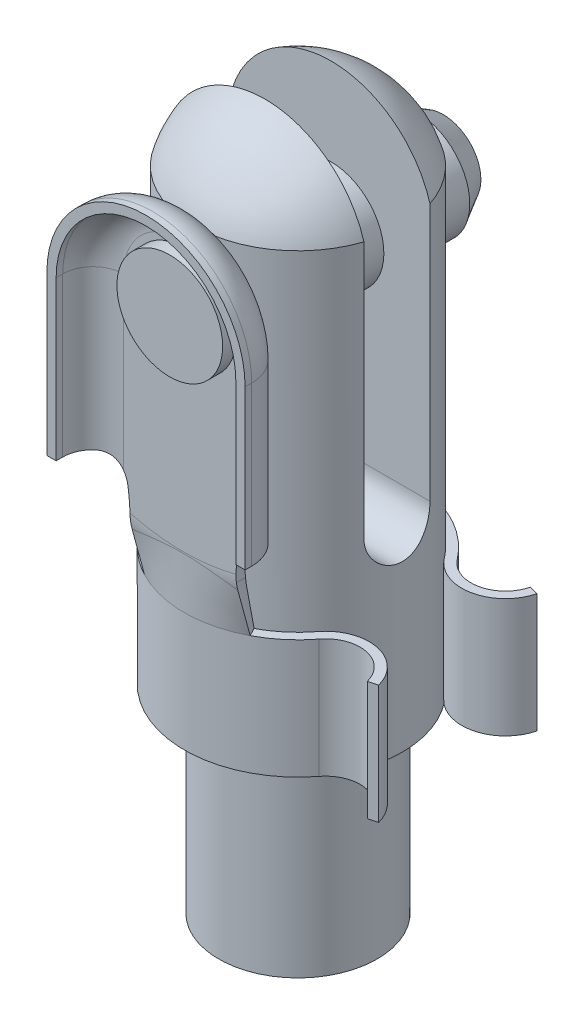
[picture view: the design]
ISO-10303-21;
HEADER;
FILE_DESCRIPTION(('STEP AP214'),'2;1');
FILE_NAME('part.step','',(''),(''),'','','');
FILE_SCHEMA(('AUTOMOTIVE_DESIGN { 1 0 10303 214 1 1 1 1 }'));
ENDSEC;
DATA;
#1=APPLICATION_CONTEXT('core data for automotive mechanical design processes');
#2=APPLICATION_PROTOCOL_DEFINITION('international standard','automotive_design',2000,#1);
#3=PRODUCT_CONTEXT('',#1,'mechanical');
#4=PRODUCT('Part','Part','',(#3));
#5=PRODUCT_RELATED_PRODUCT_CATEGORY('part','',(#4));
#6=PRODUCT_DEFINITION_FORMATION('','',#4);
#7=PRODUCT_DEFINITION_CONTEXT('part definition',#1,'design');
#8=PRODUCT_DEFINITION('design','',#6,#7);
#9=PRODUCT_DEFINITION_SHAPE('','',#8);
#10=(LENGTH_UNIT() NAMED_UNIT(*) SI_UNIT(.MILLI.,.METRE.));
#11=(NAMED_UNIT(*) PLANE_ANGLE_UNIT() SI_UNIT($,.RADIAN.));
#12=(NAMED_UNIT(*) SI_UNIT($,.STERADIAN.) SOLID_ANGLE_UNIT());
#13=UNCERTAINTY_MEASURE_WITH_UNIT(LENGTH_MEASURE(1.E-05),#10,'distance_accuracy_value','');
#14=(GEOMETRIC_REPRESENTATION_CONTEXT(3) GLOBAL_UNCERTAINTY_ASSIGNED_CONTEXT((#13)) GLOBAL_UNIT_ASSIGNED_CONTEXT((#10,
#11,#12)) REPRESENTATION_CONTEXT('',''));
#15=CARTESIAN_POINT('',(0.,0.,0.));
#16=DIRECTION('',(0.,0.,1.));
#17=DIRECTION('',(1.,0.,0.));
#18=AXIS2_PLACEMENT_3D('',#15,#16,#17);
#19=CARTESIAN_POINT('',(0.,22.,4.35));
#20=DIRECTION('',(0.,0.,1.));
#21=DIRECTION('',(1.,0.,0.));
#22=AXIS2_PLACEMENT_3D('',#19,#20,#21);
#23=PLANE('',#22);
#24=CARTESIAN_POINT('',(-10.125,14.,4.35));
#25=DIRECTION('',(0.,0.,-1.));
#26=DIRECTION('',(-1.,0.,0.));
#27=AXIS2_PLACEMENT_3D('',#24,#25,#26);
#28=CIRCLE('',#27,8.12500000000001);
#29=CARTESIAN_POINT('',(-2.08042264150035,15.140350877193,4.35));
#30=VERTEX_POINT('',#29);
#31=CARTESIAN_POINT('',(-2.00490939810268,14.2824068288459,4.35));
#32=VERTEX_POINT('',#31);
#33=EDGE_CURVE('E390',#30,#32,#28,.T.);
#34=ORIENTED_EDGE('',*,*,#33,.T.);
#35=CARTESIAN_POINT('',(3.48211562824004,14.5940291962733,4.35));
#36=CARTESIAN_POINT('',(3.59794180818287,13.9723308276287,4.35));
#37=CARTESIAN_POINT('',(3.69271229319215,13.4636491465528,3.98642597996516));
#38=CARTESIAN_POINT('',(3.36408920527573,14.5720505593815,4.35));
#39=CARTESIAN_POINT('',(3.47870250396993,13.9726457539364,4.35));
#40=CARTESIAN_POINT('',(3.57308567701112,13.474977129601,4.00961729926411));
#41=CARTESIAN_POINT('',(3.2461966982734,14.5493560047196,4.35));
#42=CARTESIAN_POINT('',(3.35875531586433,13.9730784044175,4.35));
#43=CARTESIAN_POINT('',(3.4527952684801,13.4878586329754,4.03300707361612));
#44=CARTESIAN_POINT('',(3.01068838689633,14.5025898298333,4.35));
#45=CARTESIAN_POINT('',(3.1182084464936,13.974228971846,4.35));
#46=CARTESIAN_POINT('',(3.21052336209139,13.5170837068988,4.07940973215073));
#47=CARTESIAN_POINT('',(2.89307257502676,14.4785182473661,4.35));
#48=CARTESIAN_POINT('',(2.9975937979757,13.974945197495,4.35));
#49=CARTESIAN_POINT('',(3.08854191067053,13.5334271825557,4.10242262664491));
#50=CARTESIAN_POINT('',(2.65814533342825,14.4290568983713,4.35));
#51=CARTESIAN_POINT('',(2.75560555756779,13.9767106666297,4.35));
#52=CARTESIAN_POINT('',(2.84254436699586,13.5699278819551,4.14729425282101));
#53=CARTESIAN_POINT('',(2.54083384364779,14.4036674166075,4.35));
#54=CARTESIAN_POINT('',(2.63419382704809,13.9777581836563,4.35));
#55=CARTESIAN_POINT('',(2.71852871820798,13.5900842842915,4.16915323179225));
#56=CARTESIAN_POINT('',(2.30647303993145,14.3517078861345,4.35));
#57=CARTESIAN_POINT('',(2.39056256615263,13.9801899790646,4.35));
#58=CARTESIAN_POINT('',(2.46820849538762,13.6342865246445,4.21063104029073));
#59=CARTESIAN_POINT('',(2.18942372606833,14.3251378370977,4.35));
#60=CARTESIAN_POINT('',(2.26827130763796,13.9815732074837,4.35));
#61=CARTESIAN_POINT('',(2.34190392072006,13.6583323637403,4.23024986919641));
#62=CARTESIAN_POINT('',(2.03983028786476,14.2905384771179,4.35));
#63=CARTESIAN_POINT('',(2.11111568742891,13.9835138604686,4.35));
#64=CARTESIAN_POINT('',(2.17890874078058,13.6913414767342,4.25312173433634));
#65=CARTESIAN_POINT('',(2.00718388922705,14.2829485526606,4.35));
#66=CARTESIAN_POINT('',(2.07683337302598,13.9839470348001,4.35));
#67=CARTESIAN_POINT('',(2.14324163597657,13.6986841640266,4.25797881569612));
#68=CARTESIAN_POINT('',(1.94190588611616,14.2677007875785,4.35));
#69=CARTESIAN_POINT('',(2.00821149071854,13.9848304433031,4.35));
#70=CARTESIAN_POINT('',(2.07174220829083,13.7136250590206,4.26739464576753));
#71=CARTESIAN_POINT('',(1.90927428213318,14.2600429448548,4.35));
#72=CARTESIAN_POINT('',(1.97386929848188,13.9852806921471,4.35));
#73=CARTESIAN_POINT('',(2.03590988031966,13.7212232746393,4.27195338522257));
#74=CARTESIAN_POINT('',(1.87664983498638,14.2523545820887,4.35));
#75=CARTESIAN_POINT('',(1.93948182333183,13.9857380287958,4.35));
#76=CARTESIAN_POINT('',(2.00000000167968,13.7289397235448,4.276349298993));
#77=CARTESIAN_POINT('',(1.7929895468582,14.2326289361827,4.35));
#78=CARTESIAN_POINT('',(1.84827499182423,13.9882844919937,4.35));
#79=CARTESIAN_POINT('',(1.90167102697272,13.7513374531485,4.28869521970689));
#80=CARTESIAN_POINT('',(1.70906782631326,14.2139880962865,4.35));
#81=CARTESIAN_POINT('',(1.75755424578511,13.990321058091,4.35));
#82=CARTESIAN_POINT('',(1.80464823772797,13.7723292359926,4.29867394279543));
#83=CARTESIAN_POINT('',(1.54071808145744,14.1790623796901,4.35));
#84=CARTESIAN_POINT('',(1.57730460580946,13.993609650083,4.35));
#85=CARTESIAN_POINT('',(1.61307967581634,13.8113201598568,4.31497721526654));
#86=CARTESIAN_POINT('',(1.4562899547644,14.1627779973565,4.35));
#87=CARTESIAN_POINT('',(1.48768965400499,13.9948646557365,4.35));
#88=CARTESIAN_POINT('',(1.5185344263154,13.8293186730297,4.32130099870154));
#89=CARTESIAN_POINT('',(1.28700243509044,14.1327641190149,4.35));
#90=CARTESIAN_POINT('',(1.30958141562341,13.9968309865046,4.35));
#91=CARTESIAN_POINT('',(1.33185249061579,13.8621282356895,4.33136895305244));
#92=CARTESIAN_POINT('',(1.20214316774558,14.1190339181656,4.35));
#93=CARTESIAN_POINT('',(1.22102866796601,13.9975437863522,4.35));
#94=CARTESIAN_POINT('',(1.23971514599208,13.8769401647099,4.33511383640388));
#95=CARTESIAN_POINT('',(1.03203881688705,14.0942857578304,4.35));
#96=CARTESIAN_POINT('',(1.0448165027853,13.9986190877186,4.35));
#97=CARTESIAN_POINT('',(1.05747616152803,13.9033699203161,4.34088069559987));
#98=CARTESIAN_POINT('',(0.946793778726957,14.0832674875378,4.35));
#99=CARTESIAN_POINT('',(0.957118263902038,13.9989821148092,4.35));
#100=CARTESIAN_POINT('',(0.967374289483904,13.9149881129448,4.34290286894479));
#101=CARTESIAN_POINT('',(0.778062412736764,14.0642810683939,4.35));
#102=CARTESIAN_POINT('',(0.784558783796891,13.9994927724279,4.35));
#103=CARTESIAN_POINT('',(0.791012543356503,13.9348320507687,4.34586056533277));
#104=CARTESIAN_POINT('',(0.694583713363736,14.0562452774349,4.35));
#105=CARTESIAN_POINT('',(0.699659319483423,13.9996455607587,4.35));
#106=CARTESIAN_POINT('',(0.70471251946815,13.943133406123,4.3468213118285));
#107=CARTESIAN_POINT('',(0.527422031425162,14.0428708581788,4.35));
#108=CARTESIAN_POINT('',(0.530332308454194,13.9998525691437,4.35));
#109=CARTESIAN_POINT('',(0.533226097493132,13.9568710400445,4.34818815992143));
#110=CARTESIAN_POINT('',(0.443739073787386,14.0375319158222,4.35));
#111=CARTESIAN_POINT('',(0.445892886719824,13.9999068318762,4.35));
#112=CARTESIAN_POINT('',(0.44803957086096,13.9623076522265,4.34859432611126));
#113=CARTESIAN_POINT('',(0.240084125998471,14.027876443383,4.35));
#114=CARTESIAN_POINT('',(0.240886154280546,13.9999910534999,4.34999999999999));
#115=CARTESIAN_POINT('',(0.241676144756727,13.9721148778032,4.34925858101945));
#116=CARTESIAN_POINT('',(0.120040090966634,14.0249960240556,4.35));
#117=CARTESIAN_POINT('',(0.120438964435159,14.0000004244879,4.34999999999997));
#118=CARTESIAN_POINT('',(0.120836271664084,13.9750123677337,4.34937707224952));
#119=CARTESIAN_POINT('',(-0.115876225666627,14.0249961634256,4.35));
#120=CARTESIAN_POINT('',(-0.116261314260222,13.999999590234,4.35000000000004));
#121=CARTESIAN_POINT('',(-0.116644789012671,13.9750110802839,4.34937357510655));
#122=CARTESIAN_POINT('',(-0.231748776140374,14.0276803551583,4.35));
#123=CARTESIAN_POINT('',(-0.232521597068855,13.9999900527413,4.35000000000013));
#124=CARTESIAN_POINT('',(-0.233286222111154,13.9723098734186,4.34925978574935));
#125=CARTESIAN_POINT('',(-0.472394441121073,14.0386969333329,4.35));
#126=CARTESIAN_POINT('',(-0.474715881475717,13.9998992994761,4.35000000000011));
#127=CARTESIAN_POINT('',(-0.477021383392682,13.9611282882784,4.34852600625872));
#128=CARTESIAN_POINT('',(-0.597148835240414,14.0474580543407,4.35));
#129=CARTESIAN_POINT('',(-0.600705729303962,13.9998124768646,4.34999999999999));
#130=CARTESIAN_POINT('',(-0.604213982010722,13.9522089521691,4.34786680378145));
#131=CARTESIAN_POINT('',(-0.727751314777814,14.0597811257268,4.35));
#132=CARTESIAN_POINT('',(-0.733480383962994,13.999566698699,4.35));
#133=CARTESIAN_POINT('',(-0.739198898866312,13.9394622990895,4.34634505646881));
#134=CARTESIAN_POINT('',(-0.733901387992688,14.0603687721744,4.35));
#135=CARTESIAN_POINT('',(-0.739735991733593,13.9995547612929,4.35));
#136=CARTESIAN_POINT('',(-0.745559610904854,13.9388541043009,4.34627145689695));
#137=CARTESIAN_POINT('',(-0.764648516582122,14.0633433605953,4.35));
#138=CARTESIAN_POINT('',(-0.771022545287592,13.99949306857,4.35));
#139=CARTESIAN_POINT('',(-0.777381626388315,13.9357735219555,4.34589286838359));
#140=CARTESIAN_POINT('',(-0.789235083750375,14.0658392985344,4.35));
#141=CARTESIAN_POINT('',(-0.796074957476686,13.9994373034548,4.35));
#142=CARTESIAN_POINT('',(-0.802897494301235,13.9331823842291,4.34555611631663));
#143=CARTESIAN_POINT('',(-0.9121236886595,14.0789057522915,4.35));
#144=CARTESIAN_POINT('',(-0.921507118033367,13.9991195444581,4.35));
#145=CARTESIAN_POINT('',(-0.930824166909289,13.9195775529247,4.34367552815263));
#146=CARTESIAN_POINT('',(-1.01024394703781,14.0912319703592,4.35));
#147=CARTESIAN_POINT('',(-1.02229643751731,13.9987408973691,4.35));
#148=CARTESIAN_POINT('',(-1.03422629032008,13.9066211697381,4.34154174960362));
#149=CARTESIAN_POINT('',(-1.23721495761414,14.1239933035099,4.35));
#150=CARTESIAN_POINT('',(-1.25734167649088,13.9973412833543,4.35));
#151=CARTESIAN_POINT('',(-1.27716801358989,13.8716557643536,4.33402001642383));
#152=CARTESIAN_POINT('',(-1.36587424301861,14.1457609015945,4.35));
#153=CARTESIAN_POINT('',(-1.39208331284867,13.9961526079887,4.35));
#154=CARTESIAN_POINT('',(-1.41770410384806,13.848077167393,4.32781054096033));
#155=CARTESIAN_POINT('',(-1.55803971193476,14.1826707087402,4.35));
#156=CARTESIAN_POINT('',(-1.5958083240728,13.993255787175,4.35));
#157=CARTESIAN_POINT('',(-1.63281160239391,13.807294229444,4.31322231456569));
#158=CARTESIAN_POINT('',(-1.62196488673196,14.1956854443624,4.35));
#159=CARTESIAN_POINT('',(-1.66410208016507,13.9921021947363,4.35));
#160=CARTESIAN_POINT('',(-1.70523985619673,13.7927954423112,4.30747961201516));
#161=CARTESIAN_POINT('',(-1.74952508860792,14.2230446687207,4.35));
#162=CARTESIAN_POINT('',(-1.80130821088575,13.9893117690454,4.35));
#163=CARTESIAN_POINT('',(-1.85153549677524,13.7621073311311,4.29373451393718));
#164=CARTESIAN_POINT('',(-1.81316013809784,14.2373890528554,4.35));
#165=CARTESIAN_POINT('',(-1.87026127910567,13.9876733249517,4.35));
#166=CARTESIAN_POINT('',(-1.9254027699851,13.7459181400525,4.28573229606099));
#167=CARTESIAN_POINT('',(-1.8766498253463,14.2523545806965,4.35));
#168=CARTESIAN_POINT('',(-1.93948181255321,13.9857380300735,4.35));
#169=CARTESIAN_POINT('',(-1.99999998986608,13.7289397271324,4.27634930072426));
#170=CARTESIAN_POINT('',(-1.90958111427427,14.2601153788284,4.35));
#171=CARTESIAN_POINT('',(-1.97419340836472,13.9852762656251,4.35));
#172=CARTESIAN_POINT('',(-2.03624814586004,13.7211499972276,4.2719120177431));
#173=CARTESIAN_POINT('',(-1.94251977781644,14.2678449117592,4.35));
#174=CARTESIAN_POINT('',(-2.00885818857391,13.9848219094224,4.35));
#175=CARTESIAN_POINT('',(-2.07241656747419,13.7134817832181,4.26730885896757));
#176=CARTESIAN_POINT('',(-2.00841314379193,14.2832349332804,4.35));
#177=CARTESIAN_POINT('',(-2.0781250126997,13.9839306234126,4.35));
#178=CARTESIAN_POINT('',(-2.14458602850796,13.6984056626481,4.25779866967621));
#179=CARTESIAN_POINT('',(-2.04136784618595,14.2908954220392,4.35));
#180=CARTESIAN_POINT('',(-2.11272975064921,13.9834936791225,4.35));
#181=CARTESIAN_POINT('',(-2.18058706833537,13.6909977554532,4.25289163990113));
#182=CARTESIAN_POINT('',(-2.10728748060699,14.306139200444,4.35));
#183=CARTESIAN_POINT('',(-2.18186513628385,13.9826404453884,4.35));
#184=CARTESIAN_POINT('',(-2.25240612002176,13.6764610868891,4.24280267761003));
#185=CARTESIAN_POINT('',(-2.14025240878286,14.3137225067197,4.35));
#186=CARTESIAN_POINT('',(-2.21639825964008,13.9822241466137,4.35));
#187=CARTESIAN_POINT('',(-2.28822417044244,13.6693322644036,4.2376208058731));
#188=CARTESIAN_POINT('',(-2.20620083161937,14.3288083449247,4.35));
#189=CARTESIAN_POINT('',(-2.28539786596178,13.9814139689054,4.35));
#190=CARTESIAN_POINT('',(-2.35968251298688,13.6553620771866,4.22700835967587));
#191=CARTESIAN_POINT('',(-2.23918432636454,14.336310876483,4.35));
#192=CARTESIAN_POINT('',(-2.31986656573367,13.981020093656,4.35));
#193=CARTESIAN_POINT('',(-2.39532280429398,13.6485207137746,4.22157778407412));
#194=CARTESIAN_POINT('',(-2.46536295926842,14.3874420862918,4.35));
#195=CARTESIAN_POINT('',(-2.55672874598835,13.9783989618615,4.34999999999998));
#196=CARTESIAN_POINT('',(-2.63901106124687,13.6026667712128,4.18360528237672));
#197=CARTESIAN_POINT('',(-2.65889262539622,14.4296120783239,4.35));
#198=CARTESIAN_POINT('',(-2.75730030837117,13.9766104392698,4.34999999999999));
#199=CARTESIAN_POINT('',(-2.84397861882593,13.5687290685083,4.14744810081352));
#200=CARTESIAN_POINT('',(-3.04672136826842,14.5102716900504,4.35));
#201=CARTESIAN_POINT('',(-3.15604566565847,13.9739241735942,4.35));
#202=CARTESIAN_POINT('',(-3.2484456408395,13.5111860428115,4.07262212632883));
#203=CARTESIAN_POINT('',(-3.24102045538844,14.5487612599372,4.35));
#204=CARTESIAN_POINT('',(-3.35436070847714,13.9730342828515,4.35));
#205=CARTESIAN_POINT('',(-3.44794503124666,13.487580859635,4.03395329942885));
#206=CARTESIAN_POINT('',(-3.63037590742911,14.6219270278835,4.35));
#207=CARTESIAN_POINT('',(-3.74944820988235,13.9718834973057,4.35));
#208=CARTESIAN_POINT('',(-3.8432984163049,13.448802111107,3.95718756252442));
#209=CARTESIAN_POINT('',(-3.82543241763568,14.6566024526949,4.35));
#210=CARTESIAN_POINT('',(-3.94620516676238,13.9716294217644,4.35));
#211=CARTESIAN_POINT('',(-4.03915166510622,13.43363025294,3.91909076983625));
#212=CARTESIAN_POINT('',(-4.21615981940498,14.7222916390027,4.35));
#213=CARTESIAN_POINT('',(-4.33881906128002,13.9715047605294,4.35));
#214=CARTESIAN_POINT('',(-4.42871715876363,13.409659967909,3.84505695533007));
#215=CARTESIAN_POINT('',(-4.411830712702,14.7533053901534,4.35));
#216=CARTESIAN_POINT('',(-4.53457814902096,13.9716382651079,4.35));
#217=CARTESIAN_POINT('',(-4.62242939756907,13.4008615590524,3.80911993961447));
#218=CARTESIAN_POINT('',(-4.80416974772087,14.8120523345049,4.35));
#219=CARTESIAN_POINT('',(-4.92619485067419,13.9721152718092,4.35));
#220=CARTESIAN_POINT('',(-5.00930561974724,13.3878554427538,3.73999063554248));
#221=CARTESIAN_POINT('',(-5.00083916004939,14.8397770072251,4.35));
#222=CARTESIAN_POINT('',(-5.12190831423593,13.9724612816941,4.35));
#223=CARTESIAN_POINT('',(-5.20246696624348,13.3836594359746,3.70680554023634));
#224=CARTESIAN_POINT('',(-5.39458086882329,14.8922132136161,4.35));
#225=CARTESIAN_POINT('',(-5.51326097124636,13.9732559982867,4.35));
#226=CARTESIAN_POINT('',(-5.58845248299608,13.3785305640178,3.6434523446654));
#227=CARTESIAN_POINT('',(-5.5916531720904,14.9169246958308,4.35));
#228=CARTESIAN_POINT('',(-5.70874702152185,13.9737053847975,4.35));
#229=CARTESIAN_POINT('',(-5.781276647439,13.3775977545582,3.61328429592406));
#230=CARTESIAN_POINT('',(-5.98604389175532,14.9636863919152,4.35));
#231=CARTESIAN_POINT('',(-6.09978369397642,13.9746429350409,4.35));
#232=CARTESIAN_POINT('',(-6.16694081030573,13.3779704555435,3.55588998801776));
#233=CARTESIAN_POINT('',(-6.18336220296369,14.9857374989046,4.35));
#234=CARTESIAN_POINT('',(-6.29518053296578,13.9751310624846,4.35));
#235=CARTESIAN_POINT('',(-6.3597807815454,13.3792752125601,3.52866274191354));
#236=CARTESIAN_POINT('',(-6.57823246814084,15.027512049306,4.35));
#237=CARTESIAN_POINT('',(-6.68618298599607,13.9761149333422,4.35));
#238=CARTESIAN_POINT('',(-6.74572756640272,13.3834343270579,3.47692027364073));
#239=CARTESIAN_POINT('',(-6.7757844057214,15.0472356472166,4.35));
#240=CARTESIAN_POINT('',(-6.88164110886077,13.976610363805,4.35));
#241=CARTESIAN_POINT('',(-6.93883436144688,13.3862885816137,3.45240487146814));
#242=CARTESIAN_POINT('',(-6.9734269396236,15.065958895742,4.35));
#243=CARTESIAN_POINT('',(-7.07654259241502,13.9770913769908,4.35));
#244=CARTESIAN_POINT('',(-7.13218042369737,13.389574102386,3.42913454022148));
#245=(BOUNDED_SURFACE() B_SPLINE_SURFACE(3,2,((#35,#36,#37),(#38,#39,#40),(#41,#42,#43),(#44,
#45,#46),(#47,#48,#49),(#50,#51,#52),(#53,#54,#55),(#56,#57,#58),(#59,#60,#61),(#62,#63,#64),
(#65,#66,#67),(#68,#69,#70),(#71,#72,#73),(#74,#75,#76),(#77,#78,#79),(#80,#81,#82),(#83,#84,
#85),(#86,#87,#88),(#89,#90,#91),(#92,#93,#94),(#95,#96,#97),(#98,#99,#100),(#101,#102,#103),
(#104,#105,#106),(#107,#108,#109),(#110,#111,#112),(#113,#114,#115),(#116,#117,#118),(#119,#120,
#121),(#122,#123,#124),(#125,#126,#127),(#128,#129,#130),(#131,#132,#133),(#134,#135,#136),
(#137,#138,#139),(#140,#141,#142),(#143,#144,#145),(#146,#147,#148),(#149,#150,#151),(#152,#153,
#154),(#155,#156,#157),(#158,#159,#160),(#161,#162,#163),(#164,#165,#166),(#167,#168,#169),
(#170,#171,#172),(#173,#174,#175),(#176,#177,#178),(#179,#180,#181),(#182,#183,#184),(#185,#186,
#187),(#188,#189,#190),(#191,#192,#193),(#194,#195,#196),(#197,#198,#199),(#200,#201,#202),
(#203,#204,#205),(#206,#207,#208),(#209,#210,#211),(#212,#213,#214),(#215,#216,#217),(#218,#219,
#220),(#221,#222,#223),(#224,#225,#226),(#227,#228,#229),(#230,#231,#232),(#233,#234,#235),
(#236,#237,#238),(#239,#240,#241),(#242,#243,#244)),.UNSPECIFIED.,.F.,.F.,
.F.) B_SPLINE_SURFACE_WITH_KNOTS((4,2,2,2,2,2,3,2,2,2,2,2,2,2,2,2,2,2,2,2,2,3,2,2,2,2,2,2,2,2,2,
2,2,4),(3,3),(0.,0.360163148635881,0.720316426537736,1.08039220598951,1.44046808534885,
1.5410192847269,1.64157360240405,1.89943751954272,2.15735545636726,2.4152021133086,
2.67301920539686,2.92456823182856,3.17608795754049,3.53617731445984,3.88377614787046,
4.25878733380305,4.27732162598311,4.3514595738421,4.64806066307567,5.03936749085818,
5.23506565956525,5.43074844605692,5.53224867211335,5.63374865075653,5.73522627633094,
5.83670436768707,6.43088282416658,7.02506932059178,7.61937605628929,8.21368447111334,
8.80950031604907,9.40532633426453,10.0009517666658,10.5965376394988),(0.,1.),
.UNSPECIFIED.) GEOMETRIC_REPRESENTATION_ITEM() RATIONAL_B_SPLINE_SURFACE(((1.,0.953470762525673,
1.),(1.,0.956511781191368,1.),(1.,0.959563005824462,1.),(1.,0.965588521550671,1.),(1.,
0.968562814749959,1.),(1.,0.974336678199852,1.),(1.,0.977136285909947,1.),(1.,0.982427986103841,
1.),(1.,0.984920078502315,1.),(1.,0.987816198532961,1.),(1.,0.988430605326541,1.),(1.,
0.98962064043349,1.),(1.,0.990196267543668,1.),(1.,0.990750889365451,1.),(1.,0.992307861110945,
1.),(1.,0.99356389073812,1.),(1.,0.995613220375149,1.),(1.,0.996406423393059,1.),(1.,
0.997668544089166,1.),(1.,0.99813755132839,1.),(1.,0.998859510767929,1.),(1.,0.999112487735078,
1.),(1.,0.999482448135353,1.),(1.,0.99960258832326,1.),(1.,0.999773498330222,1.),(1.,
0.999824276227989,1.),(1.,0.999907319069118,1.),(1.,0.999922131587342,1.),(1.,0.999921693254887,
1.),(1.,0.999907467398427,1.),(1.,0.999815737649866,1.),(1.,0.999733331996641,1.),(1.,
0.999543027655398,1.),(1.,0.999533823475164,1.),(1.,0.999486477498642,1.),(1.,0.999444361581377,
1.),(1.,0.999209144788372,1.),(1.,0.998942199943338,1.),(1.,0.998000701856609,1.),(1.,
0.997223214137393,1.),(1.,0.995392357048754,1.),(1.,0.994671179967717,1.),(1.,0.992942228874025,
1.),(1.,0.991934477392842,1.),(1.,0.990750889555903,1.),(1.,0.990191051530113,1.),(1.,
0.989609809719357,1.),(1.,0.988407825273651,1.),(1.,0.98778708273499,1.),(1.,0.986509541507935,
1.),(1.,0.985852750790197,1.),(1.,0.984506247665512,1.),(1.,0.983816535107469,1.),(1.,
0.978988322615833,1.),(1.,0.974363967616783,1.),(1.,0.964717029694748,1.),(1.,0.959694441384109,
1.),(1.,0.949643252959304,1.),(1.,0.944614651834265,1.),(1.,0.934766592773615,1.),(1.,
0.929947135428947,1.),(1.,0.920608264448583,1.),(1.,0.916089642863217,1.),(1.,0.907403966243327,
1.),(1.,0.903236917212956,1.),(1.,0.895258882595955,1.),(1.,0.891447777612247,1.),(1.,
0.88416240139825,1.),(1.,0.880688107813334,1.),(1.,0.877373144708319,1.))) REPRESENTATION_ITEM('') SURFACE());
#246=CARTESIAN_POINT('',(-6.9734269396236,15.065958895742,4.35));
#247=CARTESIAN_POINT('',(-6.7757844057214,15.0472356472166,4.35));
#248=CARTESIAN_POINT('',(-6.57823246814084,15.027512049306,4.35));
#249=CARTESIAN_POINT('',(-6.18336220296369,14.9857374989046,4.35));
#250=CARTESIAN_POINT('',(-5.98604389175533,14.9636863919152,4.35));
#251=CARTESIAN_POINT('',(-5.5916531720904,14.9169246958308,4.35));
#252=CARTESIAN_POINT('',(-5.39458086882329,14.8922132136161,4.35));
#253=CARTESIAN_POINT('',(-5.00083916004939,14.8397770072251,4.35));
#254=CARTESIAN_POINT('',(-4.80416974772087,14.8120523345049,4.35));
#255=CARTESIAN_POINT('',(-4.411830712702,14.7533053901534,4.35));
#256=CARTESIAN_POINT('',(-4.21615981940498,14.7222916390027,4.35));
#257=CARTESIAN_POINT('',(-3.82543241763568,14.6566024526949,4.35));
#258=CARTESIAN_POINT('',(-3.63037590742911,14.6219270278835,4.35));
#259=CARTESIAN_POINT('',(-3.24102045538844,14.5487612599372,4.35));
#260=CARTESIAN_POINT('',(-3.04672136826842,14.5102716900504,4.35));
#261=CARTESIAN_POINT('',(-2.65889262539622,14.4296120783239,4.35));
#262=CARTESIAN_POINT('',(-2.46536295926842,14.3874420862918,4.35));
#263=CARTESIAN_POINT('',(-2.23918432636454,14.336310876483,4.35));
#264=CARTESIAN_POINT('',(-2.20620083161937,14.3288083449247,4.35));
#265=CARTESIAN_POINT('',(-2.14025240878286,14.3137225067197,4.35));
#266=CARTESIAN_POINT('',(-2.10728748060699,14.306139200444,4.35));
#267=CARTESIAN_POINT('',(-2.04136784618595,14.2908954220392,4.35));
#268=CARTESIAN_POINT('',(-2.00841314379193,14.2832349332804,4.35));
#269=CARTESIAN_POINT('',(-1.94251977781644,14.2678449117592,4.35));
#270=CARTESIAN_POINT('',(-1.90958111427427,14.2601153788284,4.35));
#271=CARTESIAN_POINT('',(-1.8766498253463,14.2523545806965,4.35));
#272=CARTESIAN_POINT('',(-1.81316013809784,14.2373890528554,4.35));
#273=CARTESIAN_POINT('',(-1.74952508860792,14.2230446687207,4.35));
#274=CARTESIAN_POINT('',(-1.62196488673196,14.1956854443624,4.35));
#275=CARTESIAN_POINT('',(-1.55803971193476,14.1826707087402,4.35));
#276=CARTESIAN_POINT('',(-1.36587424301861,14.1457609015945,4.35));
#277=CARTESIAN_POINT('',(-1.23721495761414,14.1239933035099,4.35));
#278=CARTESIAN_POINT('',(-1.01024394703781,14.0912319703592,4.35));
#279=CARTESIAN_POINT('',(-0.912123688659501,14.0789057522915,4.35));
#280=CARTESIAN_POINT('',(-0.789235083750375,14.0658392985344,4.35));
#281=CARTESIAN_POINT('',(-0.764648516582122,14.0633433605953,4.35));
#282=CARTESIAN_POINT('',(-0.733901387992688,14.0603687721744,4.35));
#283=CARTESIAN_POINT('',(-0.727751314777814,14.0597811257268,4.35));
#284=CARTESIAN_POINT('',(-0.597148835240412,14.0474580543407,4.35));
#285=CARTESIAN_POINT('',(-0.472394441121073,14.0386969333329,4.35));
#286=CARTESIAN_POINT('',(-0.231748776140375,14.0276803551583,4.35));
#287=CARTESIAN_POINT('',(-0.115876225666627,14.0249961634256,4.35));
#288=CARTESIAN_POINT('',(0.120040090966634,14.0249960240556,4.35));
#289=CARTESIAN_POINT('',(0.240084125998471,14.027876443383,4.35));
#290=CARTESIAN_POINT('',(0.443739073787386,14.0375319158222,4.35));
#291=CARTESIAN_POINT('',(0.527422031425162,14.0428708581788,4.35));
#292=CARTESIAN_POINT('',(0.694583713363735,14.0562452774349,4.35));
#293=CARTESIAN_POINT('',(0.778062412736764,14.0642810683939,4.35));
#294=CARTESIAN_POINT('',(0.946793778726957,14.0832674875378,4.35));
#295=CARTESIAN_POINT('',(1.03203881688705,14.0942857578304,4.35));
#296=CARTESIAN_POINT('',(1.20214316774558,14.1190339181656,4.35));
#297=CARTESIAN_POINT('',(1.28700243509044,14.1327641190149,4.35));
#298=CARTESIAN_POINT('',(1.4562899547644,14.1627779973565,4.35));
#299=CARTESIAN_POINT('',(1.54071808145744,14.1790623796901,4.35));
#300=CARTESIAN_POINT('',(1.70906782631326,14.2139880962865,4.35));
#301=CARTESIAN_POINT('',(1.7929895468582,14.2326289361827,4.35));
#302=CARTESIAN_POINT('',(1.87664983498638,14.2523545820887,4.35));
#303=CARTESIAN_POINT('',(1.90927428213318,14.2600429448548,4.35));
#304=CARTESIAN_POINT('',(1.94190588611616,14.2677007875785,4.35));
#305=CARTESIAN_POINT('',(2.00718388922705,14.2829485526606,4.35));
#306=CARTESIAN_POINT('',(2.03983028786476,14.2905384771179,4.35));
#307=CARTESIAN_POINT('',(2.18942372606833,14.3251378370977,4.35));
#308=CARTESIAN_POINT('',(2.30647303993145,14.3517078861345,4.35));
#309=CARTESIAN_POINT('',(2.54083384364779,14.4036674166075,4.35));
#310=CARTESIAN_POINT('',(2.65814533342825,14.4290568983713,4.35));
#311=CARTESIAN_POINT('',(2.89307257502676,14.4785182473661,4.35));
#312=CARTESIAN_POINT('',(3.01068838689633,14.5025898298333,4.35));
#313=CARTESIAN_POINT('',(3.2461966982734,14.5493560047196,4.35));
#314=CARTESIAN_POINT('',(3.36408920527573,14.5720505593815,4.35));
#315=CARTESIAN_POINT('',(3.48211562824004,14.5940291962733,4.35));
#316=B_SPLINE_CURVE_WITH_KNOTS('',3,(#246,#247,#248,#249,#250,#251,#252,#253,#254,#255,#256,
#257,#258,#259,#260,#261,#262,#263,#264,#265,#266,#267,#268,#269,#270,#271,#272,#273,#274,#275,
#276,#277,#278,#279,#280,#281,#282,#283,#284,#285,#286,#287,#288,#289,#290,#291,#292,#293,#294,
#295,#296,#297,#298,#299,#300,#301,#302,#303,#304,#305,#306,#307,#308,#309,#310,#311,#312,#313,
#314,#315),.UNSPECIFIED.,.F.,.F.,(4,2,2,2,2,2,2,2,2,2,2,2,3,2,2,2,2,2,2,2,2,2,2,2,2,2,2,3,2,2,2,
2,2,4),(0.,0.595585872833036,1.19121130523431,1.78703732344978,2.3828531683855,2.97716158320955,
3.57146831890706,4.16565481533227,4.75983327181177,4.8613113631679,4.96278898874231,
5.06428896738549,5.16578919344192,5.3614719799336,5.55717014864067,5.94847697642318,
6.24507806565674,6.31921601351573,6.33775030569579,6.71276149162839,7.060360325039,
7.42044968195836,7.67196940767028,7.92351843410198,8.18133552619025,8.43918218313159,
8.69710011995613,8.95496403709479,9.05551835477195,9.15606955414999,9.51614543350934,
9.87622121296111,10.236374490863,10.5965376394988),.UNSPECIFIED.);
#317=CARTESIAN_POINT('',(2.00490939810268,14.2824068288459,4.35));
#318=VERTEX_POINT('',#317);
#319=EDGE_CURVE('E642',#32,#318,#316,.T.);
#320=ORIENTED_EDGE('',*,*,#319,.T.);
#321=CARTESIAN_POINT('',(10.125,14.,4.35));
#322=DIRECTION('',(0.,0.,-1.));
#323=DIRECTION('',(1.,0.,0.));
#324=AXIS2_PLACEMENT_3D('',#321,#322,#323);
#325=CIRCLE('',#324,8.12500000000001);
#326=CARTESIAN_POINT('',(2.08042264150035,15.140350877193,4.35));
#327=VERTEX_POINT('',#326);
#328=EDGE_CURVE('E394',#318,#327,#325,.T.);
#329=ORIENTED_EDGE('',*,*,#328,.T.);
#330=CARTESIAN_POINT('',(3.07052447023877,15.,4.35));
#331=DIRECTION('',(0.,0.,1.));
#332=DIRECTION('',(1.,0.,0.));
#333=AXIS2_PLACEMENT_3D('',#330,#331,#332);
#334=CIRCLE('',#333,1.);
#335=CARTESIAN_POINT('',(2.25,15.5716114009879,4.35));
#336=VERTEX_POINT('',#335);
#337=EDGE_CURVE('E779',#327,#336,#334,.F.);
#338=ORIENTED_EDGE('',*,*,#337,.T.);
#339=DIRECTION('',(0.,1.,0.));
#340=VECTOR('',#339,1.);
#341=CARTESIAN_POINT('',(2.25,22.,4.35));
#342=LINE('',#341,#340);
#343=CARTESIAN_POINT('',(2.25,22.,4.35));
#344=VERTEX_POINT('',#343);
#345=EDGE_CURVE('E391',#336,#344,#342,.T.);
#346=ORIENTED_EDGE('',*,*,#345,.T.);
#347=CARTESIAN_POINT('',(0.,22.,4.35));
#348=DIRECTION('',(0.,0.,1.));
#349=DIRECTION('',(1.,0.,0.));
#350=AXIS2_PLACEMENT_3D('',#347,#348,#349);
#351=CIRCLE('',#350,2.25);
#352=CARTESIAN_POINT('',(-2.25,22.,4.35));
#353=VERTEX_POINT('',#352);
#354=EDGE_CURVE('E304',#344,#353,#351,.T.);
#355=ORIENTED_EDGE('',*,*,#354,.T.);
#356=DIRECTION('',(0.,-1.,0.));
#357=VECTOR('',#356,1.);
#358=CARTESIAN_POINT('',(-2.25,16.,4.35));
#359=LINE('',#358,#357);
#360=CARTESIAN_POINT('',(-2.25,15.5716114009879,4.35));
#361=VERTEX_POINT('',#360);
#362=EDGE_CURVE('E387',#353,#361,#359,.T.);
#363=ORIENTED_EDGE('',*,*,#362,.T.);
#364=CARTESIAN_POINT('',(-3.07052447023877,15.,4.35));
#365=DIRECTION('',(0.,0.,1.));
#366=DIRECTION('',(1.,0.,0.));
#367=AXIS2_PLACEMENT_3D('',#364,#365,#366);
#368=CIRCLE('',#367,1.);
#369=EDGE_CURVE('E422',#361,#30,#368,.F.);
#370=ORIENTED_EDGE('',*,*,#369,.T.);
#371=EDGE_LOOP('',(#34,#320,#329,#338,#346,#355,#363,#370));
#372=FACE_BOUND('',#371,.T.);
#373=CARTESIAN_POINT('',(0.,22.,4.35));
#374=DIRECTION('',(0.,0.,1.));
#375=DIRECTION('',(1.,0.,0.));
#376=AXIS2_PLACEMENT_3D('',#373,#374,#375);
#377=CIRCLE('',#376,2.);
#378=CARTESIAN_POINT('',(2.,22.,4.35));
#379=VERTEX_POINT('',#378);
#380=EDGE_CURVE('E806',#379,#379,#377,.T.);
#381=ORIENTED_EDGE('',*,*,#380,.F.);
#382=EDGE_LOOP('',(#381));
#383=FACE_BOUND('',#382,.T.);
#384=ADVANCED_FACE('F64',(#372,#383),#23,.T.);
#385=CARTESIAN_POINT('',(4.44934224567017,12.,3.4004931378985));
#386=DIRECTION('',(0.,-1.,0.));
#387=DIRECTION('',(0.,0.,-1.));
#388=AXIS2_PLACEMENT_3D('',#385,#386,#387);
#389=PLANE('',#388);
#390=CARTESIAN_POINT('',(3.41645922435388,12.,-2.61109294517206));
#391=CARTESIAN_POINT('',(3.21272026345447,12.,-2.87753191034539));
#392=CARTESIAN_POINT('',(2.97064777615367,12.,-3.10889880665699));
#393=CARTESIAN_POINT('',(2.72876998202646,12.,-3.34007962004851));
#394=CARTESIAN_POINT('',(2.45309116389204,12.,-3.53162055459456));
#395=CARTESIAN_POINT('',(2.17831570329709,12.,-3.72253383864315));
#396=CARTESIAN_POINT('',(1.8762890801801,12.,-3.86904888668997));
#397=CARTESIAN_POINT('',(1.5752521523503,12.,-4.01508382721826));
#398=CARTESIAN_POINT('',(1.25417207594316,12.,-4.11303445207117));
#399=CARTESIAN_POINT('',(0.934144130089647,12.,-4.21066410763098));
#400=CARTESIAN_POINT('',(0.60176511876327,12.,-4.25768466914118));
#401=CARTESIAN_POINT('',(0.270475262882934,12.,-4.30455115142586));
#402=CARTESIAN_POINT('',(-0.0651752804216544,12.,-4.29950603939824));
#403=CARTESIAN_POINT('',(-0.399725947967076,12.,-4.2944774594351));
#404=CARTESIAN_POINT('',(-0.730541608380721,12.,-4.23748852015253));
#405=CARTESIAN_POINT('',(-1.06027323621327,12.,-4.18068632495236));
#406=CARTESIAN_POINT('',(-1.37826436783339,12.,-4.07312991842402));
#407=CARTESIAN_POINT('',(-1.69521349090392,12.,-3.965925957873));
#408=CARTESIAN_POINT('',(-1.9927001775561,12.,-3.81039971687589));
#409=CARTESIAN_POINT('',(-2.28921204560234,12.,-3.65538311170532));
#410=CARTESIAN_POINT('',(-2.55900958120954,12.,-3.45564320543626));
#411=CARTESIAN_POINT('',(-2.82792303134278,12.,-3.25655781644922));
#412=CARTESIAN_POINT('',(-3.06351544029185,12.,-3.01742823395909));
#413=CARTESIAN_POINT('',(-3.29833584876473,12.,-2.77908224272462));
#414=CARTESIAN_POINT('',(-3.4940332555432,12.,-2.50633828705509));
#415=CARTESIAN_POINT('',(-3.68908939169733,12.,-2.23448807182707));
#416=CARTESIAN_POINT('',(-3.8401654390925,12.,-1.93471687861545));
#417=CARTESIAN_POINT('',(-3.990746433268,12.,-1.63592798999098));
#418=CARTESIAN_POINT('',(-4.09355243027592,12.,-1.3163694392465));
#419=CARTESIAN_POINT('',(-4.19602154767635,12.,-0.997858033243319));
#420=CARTESIAN_POINT('',(-4.2480745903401,12.,-0.666229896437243));
#421=CARTESIAN_POINT('',(-4.29995706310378,12.,-0.335688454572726));
#422=CARTESIAN_POINT('',(-4.3,12.,0.));
#423=CARTESIAN_POINT('',(-4.30004279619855,12.,0.334588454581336));
#424=CARTESIAN_POINT('',(-4.2480745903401,12.,0.666229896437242));
#425=CARTESIAN_POINT('',(-4.19627667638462,12.,0.996784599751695));
#426=CARTESIAN_POINT('',(-4.09355243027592,12.,1.3163694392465));
#427=CARTESIAN_POINT('',(-3.99116479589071,12.,1.63490704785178));
#428=CARTESIAN_POINT('',(-3.8401654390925,12.,1.93471687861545));
#429=CARTESIAN_POINT('',(-3.6896608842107,12.,2.23354427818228));
#430=CARTESIAN_POINT('',(-3.4940332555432,12.,2.50633828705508));
#431=CARTESIAN_POINT('',(-3.29904666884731,12.,2.77823839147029));
#432=CARTESIAN_POINT('',(-3.06351544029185,12.,3.01742823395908));
#433=CARTESIAN_POINT('',(-2.82875601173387,12.,3.25583428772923));
#434=CARTESIAN_POINT('',(-2.55900958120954,12.,3.45564320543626));
#435=CARTESIAN_POINT('',(-2.29014706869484,12.,3.65479737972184));
#436=CARTESIAN_POINT('',(-1.9927001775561,12.,3.81039971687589));
#437=CARTESIAN_POINT('',(-1.69622797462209,12.,3.96549216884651));
#438=CARTESIAN_POINT('',(-1.37826436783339,12.,4.07312991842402));
#439=CARTESIAN_POINT('',(-1.06134267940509,12.,4.18041495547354));
#440=CARTESIAN_POINT('',(-0.730541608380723,12.,4.23748852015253));
#441=CARTESIAN_POINT('',(-0.400824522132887,12.,4.29437506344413));
#442=CARTESIAN_POINT('',(-0.0651752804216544,12.,4.29950603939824));
#443=CARTESIAN_POINT('',(0.269374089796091,12.,4.30462020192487));
#444=CARTESIAN_POINT('',(0.601765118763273,12.,4.25768466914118));
#445=CARTESIAN_POINT('',(0.933066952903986,12.,4.21090293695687));
#446=CARTESIAN_POINT('',(1.25417207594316,12.,4.11303445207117));
#447=CARTESIAN_POINT('',(1.57422498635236,12.,4.01548666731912));
#448=CARTESIAN_POINT('',(1.8762890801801,12.,3.86904888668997));
#449=CARTESIAN_POINT('',(2.17736335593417,12.,3.7230909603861));
#450=CARTESIAN_POINT('',(2.45309116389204,12.,3.53162055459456));
#451=CARTESIAN_POINT('',(2.72791545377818,12.,3.34077756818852));
#452=CARTESIAN_POINT('',(2.97064777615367,12.,3.10889880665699));
#453=CARTESIAN_POINT('',(3.21238415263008,12.,2.87797145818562));
#454=CARTESIAN_POINT('',(3.41645922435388,12.,2.61109294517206));
#455=B_SPLINE_CURVE_WITH_KNOTS('',2,(#390,#391,#392,#393,#394,#395,#396,#397,#398,#399,#400,
#401,#402,#403,#404,#405,#406,#407,#408,#409,#410,#411,#412,#413,#414,#415,#416,#417,#418,#419,
#420,#421,#422,#423,#424,#425,#426,#427,#428,#429,#430,#431,#432,#433,#434,#435,#436,#437,#438,
#439,#440,#441,#442,#443,#444,#445,#446,#447,#448,#449,#450,#451,#452,#453,#454),.UNSPECIFIED.,
.F.,.F.,(3,2,2,2,2,2,2,2,2,2,2,2,2,2,2,2,2,2,2,2,2,2,2,2,2,2,2,2,2,2,2,2,3),(0.,0.03125,0.0625,
0.09375,0.125,0.15625,0.1875,0.21875,0.25,0.28125,0.3125,0.34375,0.375,0.40625,0.4375,0.46875,
0.5,0.53125,0.5625,0.59375,0.625,0.65625,0.6875,0.71875,0.75,0.78125,0.8125,0.84375,0.875,
0.90625,0.9375,0.96875,1.),.UNSPECIFIED.);
#456=CARTESIAN_POINT('',(3.41645922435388,12.,-2.61109294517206));
#457=VERTEX_POINT('',#456);
#458=CARTESIAN_POINT('',(-2.,12.,3.80657326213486));
#459=VERTEX_POINT('',#458);
#460=EDGE_CURVE('E998',#457,#459,#455,.T.);
#461=ORIENTED_EDGE('',*,*,#460,.T.);
#462=DIRECTION('',(-0.465116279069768,0.,0.885249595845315));
#463=VECTOR('',#462,1.);
#464=CARTESIAN_POINT('',(-1.83720930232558,12.,3.496735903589));
#465=LINE('',#464,#463);
#466=CARTESIAN_POINT('',(-1.83720930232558,12.,3.496735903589));
#467=VERTEX_POINT('',#466);
#468=EDGE_CURVE('E421',#467,#459,#465,.T.);
#469=ORIENTED_EDGE('',*,*,#468,.F.);
#470=CARTESIAN_POINT('',(3.13837533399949,12.,2.3985621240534));
#471=CARTESIAN_POINT('',(2.951200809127,12.,2.64332750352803));
#472=CARTESIAN_POINT('',(2.72885086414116,12.,2.85584890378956));
#473=CARTESIAN_POINT('',(2.50669556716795,12.,3.06818426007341));
#474=CARTESIAN_POINT('',(2.25342095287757,12.,3.24416306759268));
#475=CARTESIAN_POINT('',(2.00104968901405,12.,3.41951421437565));
#476=CARTESIAN_POINT('',(1.72356787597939,12.,3.55412630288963));
#477=CARTESIAN_POINT('',(1.44707575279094,12.,3.68825827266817));
#478=CARTESIAN_POINT('',(1.15208830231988,12.,3.77825257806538));
#479=CARTESIAN_POINT('',(0.858152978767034,12.,3.86792590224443));
#480=CARTESIAN_POINT('',(0.552784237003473,12.,3.91112894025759));
#481=CARTESIAN_POINT('',(0.248504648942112,12.,3.95417788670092));
#482=CARTESIAN_POINT('',(-0.0598703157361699,12.,3.94954624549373));
#483=CARTESIAN_POINT('',(-0.367145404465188,12.,3.94493112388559));
#484=CARTESIAN_POINT('',(-0.671078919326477,12.,3.89257666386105));
#485=CARTESIAN_POINT('',(-0.973928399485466,12.,3.8404089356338));
#486=CARTESIAN_POINT('',(-1.26608005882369,12.,3.74159608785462));
#487=CARTESIAN_POINT('',(-1.55718970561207,12.,3.64313567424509));
#488=CARTESIAN_POINT('',(-1.83050365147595,12.,3.50025090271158));
#489=CARTESIAN_POINT('',(-2.10284277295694,12.,3.35787575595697));
#490=CARTESIAN_POINT('',(-2.35071810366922,12.,3.17436992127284));
#491=CARTESIAN_POINT('',(-2.5977093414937,12.,2.99151859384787));
#492=CARTESIAN_POINT('',(-2.81415953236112,12.,2.77182361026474));
#493=CARTESIAN_POINT('',(-3.02983771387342,12.,2.55291220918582));
#494=CARTESIAN_POINT('',(-3.20963519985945,12.,2.30233400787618));
#495=CARTESIAN_POINT('',(-3.3887914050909,12.,2.05264953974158));
#496=CARTESIAN_POINT('',(-3.52759383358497,12.,1.77723992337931));
#497=CARTESIAN_POINT('',(-3.66590119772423,12.,1.50281260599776));
#498=CARTESIAN_POINT('',(-3.7603563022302,12.,1.20922308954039));
#499=CARTESIAN_POINT('',(-3.85447451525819,12.,0.916680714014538));
#500=CARTESIAN_POINT('',(-3.90230107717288,12.,0.612001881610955));
#501=CARTESIAN_POINT('',(-3.94995705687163,12.,0.308409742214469));
#502=CARTESIAN_POINT('',(-3.95,12.,0.));
#503=CARTESIAN_POINT('',(-3.95004278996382,12.,-0.307309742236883));
#504=CARTESIAN_POINT('',(-3.90230107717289,12.,-0.612001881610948));
#505=CARTESIAN_POINT('',(-3.8547296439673,12.,-0.915607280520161));
#506=CARTESIAN_POINT('',(-3.7603563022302,12.,-1.20922308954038));
#507=CARTESIAN_POINT('',(-3.66631956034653,12.,-1.50179166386));
#508=CARTESIAN_POINT('',(-3.52759383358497,12.,-1.7772399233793));
#509=CARTESIAN_POINT('',(-3.38936289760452,12.,-2.05170574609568));
#510=CARTESIAN_POINT('',(-3.20963519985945,12.,-2.30233400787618));
#511=CARTESIAN_POINT('',(-3.03054853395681,12.,-2.55206835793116));
#512=CARTESIAN_POINT('',(-2.81415953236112,12.,-2.77182361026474));
#513=CARTESIAN_POINT('',(-2.5985423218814,12.,-2.99079506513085));
#514=CARTESIAN_POINT('',(-2.35071810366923,12.,-3.17436992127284));
#515=CARTESIAN_POINT('',(-2.10377779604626,12.,-3.35729002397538));
#516=CARTESIAN_POINT('',(-1.83050365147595,12.,-3.50025090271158));
#517=CARTESIAN_POINT('',(-1.55820418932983,12.,-3.64270188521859));
#518=CARTESIAN_POINT('',(-1.26608005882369,12.,-3.74159608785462));
#519=CARTESIAN_POINT('',(-0.974997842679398,12.,-3.84013756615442));
#520=CARTESIAN_POINT('',(-0.671078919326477,12.,-3.89257666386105));
#521=CARTESIAN_POINT('',(-0.368243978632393,12.,-3.94482872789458));
#522=CARTESIAN_POINT('',(-0.0598703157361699,12.,-3.94954624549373));
#523=CARTESIAN_POINT('',(0.247403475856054,12.,-3.95424693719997));
#524=CARTESIAN_POINT('',(0.552784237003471,12.,-3.91112894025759));
#525=CARTESIAN_POINT('',(0.857075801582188,12.,-3.86816473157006));
#526=CARTESIAN_POINT('',(1.15208830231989,12.,-3.77825257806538));
#527=CARTESIAN_POINT('',(1.44604858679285,12.,-3.68866111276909));
#528=CARTESIAN_POINT('',(1.7235678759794,12.,-3.55412630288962));
#529=CARTESIAN_POINT('',(2.0000973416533,12.,-3.42007133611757));
#530=CARTESIAN_POINT('',(2.25342095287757,12.,-3.24416306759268));
#531=CARTESIAN_POINT('',(2.50584103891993,12.,-3.06888220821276));
#532=CARTESIAN_POINT('',(2.72885086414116,12.,-2.85584890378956));
#533=CARTESIAN_POINT('',(2.95086468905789,12.,-2.64376704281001));
#534=CARTESIAN_POINT('',(3.13837533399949,12.,-2.3985621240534));
#535=B_SPLINE_CURVE_WITH_KNOTS('',2,(#470,#471,#472,#473,#474,#475,#476,#477,#478,#479,#480,
#481,#482,#483,#484,#485,#486,#487,#488,#489,#490,#491,#492,#493,#494,#495,#496,#497,#498,#499,
#500,#501,#502,#503,#504,#505,#506,#507,#508,#509,#510,#511,#512,#513,#514,#515,#516,#517,#518,
#519,#520,#521,#522,#523,#524,#525,#526,#527,#528,#529,#530,#531,#532,#533,#534),.UNSPECIFIED.,
.F.,.F.,(3,2,2,2,2,2,2,2,2,2,2,2,2,2,2,2,2,2,2,2,2,2,2,2,2,2,2,2,2,2,2,2,3),(0.,0.03125,0.0625,
0.09375,0.125,0.15625,0.1875,0.21875,0.25,0.28125,0.3125,0.34375,0.375,0.40625,0.4375,0.46875,
0.5,0.53125,0.5625,0.59375,0.625,0.65625,0.6875,0.71875,0.75,0.78125,0.8125,0.84375,0.875,
0.90625,0.9375,0.96875,1.),.UNSPECIFIED.);
#536=CARTESIAN_POINT('',(3.13837533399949,12.,-2.3985621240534));
#537=VERTEX_POINT('',#536);
#538=EDGE_CURVE('E856',#467,#537,#535,.T.);
#539=ORIENTED_EDGE('',*,*,#538,.T.);
#540=CARTESIAN_POINT('',(4.44934224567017,12.,-3.4004931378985));
#541=DIRECTION('',(0.,1.,0.));
#542=DIRECTION('',(0.,0.,1.));
#543=AXIS2_PLACEMENT_3D('',#540,#541,#542);
#544=CIRCLE('',#543,1.65);
#545=CARTESIAN_POINT('',(6.05,12.,-3.));
#546=VERTEX_POINT('',#545);
#547=EDGE_CURVE('E855',#537,#546,#544,.T.);
#548=ORIENTED_EDGE('',*,*,#547,.T.);
#549=DIRECTION('',(-0.970095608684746,0.,-0.242723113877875));
#550=VECTOR('',#549,1.);
#551=CARTESIAN_POINT('',(5.71046653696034,12.,-3.08495308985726));
#552=LINE('',#551,#550);
#553=CARTESIAN_POINT('',(5.71046653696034,12.,-3.08495308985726));
#554=VERTEX_POINT('',#553);
#555=EDGE_CURVE('E943',#546,#554,#552,.T.);
#556=ORIENTED_EDGE('',*,*,#555,.T.);
#557=CARTESIAN_POINT('',(4.44934224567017,12.,-3.4004931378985));
#558=DIRECTION('',(0.,-1.,0.));
#559=DIRECTION('',(0.,0.,1.));
#560=AXIS2_PLACEMENT_3D('',#557,#558,#559);
#561=CIRCLE('',#560,1.3);
#562=EDGE_CURVE('E917',#554,#457,#561,.T.);
#563=ORIENTED_EDGE('',*,*,#562,.T.);
#564=EDGE_LOOP('',(#461,#469,#539,#548,#556,#563));
#565=FACE_BOUND('',#564,.T.);
#566=ADVANCED_FACE('F819',(#565),#389,.F.);
#567=CARTESIAN_POINT('',(4.44934224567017,12.,3.4004931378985));
#568=DIRECTION('',(0.,-1.,0.));
#569=DIRECTION('',(0.,0.,-1.));
#570=AXIS2_PLACEMENT_3D('',#567,#568,#569);
#571=CYLINDRICAL_SURFACE('',#570,1.65);
#572=CARTESIAN_POINT('',(4.44934224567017,7.5,3.4004931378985));
#573=DIRECTION('',(0.,1.,0.));
#574=DIRECTION('',(0.,0.,-1.));
#575=AXIS2_PLACEMENT_3D('',#572,#573,#574);
#576=CIRCLE('',#575,1.65);
#577=CARTESIAN_POINT('',(6.05,7.5,3.));
#578=VERTEX_POINT('',#577);
#579=CARTESIAN_POINT('',(3.13837533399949,7.5,2.3985621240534));
#580=VERTEX_POINT('',#579);
#581=EDGE_CURVE('E637',#578,#580,#576,.T.);
#582=ORIENTED_EDGE('',*,*,#581,.T.);
#583=DIRECTION('',(0.,-1.,0.));
#584=VECTOR('',#583,1.);
#585=CARTESIAN_POINT('',(3.13837533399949,12.,2.3985621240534));
#586=LINE('',#585,#584);
#587=CARTESIAN_POINT('',(3.13837533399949,12.,2.3985621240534));
#588=VERTEX_POINT('',#587);
#589=EDGE_CURVE('E678',#588,#580,#586,.T.);
#590=ORIENTED_EDGE('',*,*,#589,.F.);
#591=CARTESIAN_POINT('',(4.44934224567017,12.,3.4004931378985));
#592=DIRECTION('',(0.,1.,0.));
#593=DIRECTION('',(0.,0.,-1.));
#594=AXIS2_PLACEMENT_3D('',#591,#592,#593);
#595=CIRCLE('',#594,1.65);
#596=CARTESIAN_POINT('',(6.05,12.,3.));
#597=VERTEX_POINT('',#596);
#598=EDGE_CURVE('E850',#597,#588,#595,.T.);
#599=ORIENTED_EDGE('',*,*,#598,.F.);
#600=DIRECTION('',(0.,-1.,0.));
#601=VECTOR('',#600,1.);
#602=CARTESIAN_POINT('',(6.05,12.,3.));
#603=LINE('',#602,#601);
#604=EDGE_CURVE('E973',#597,#578,#603,.T.);
#605=ORIENTED_EDGE('',*,*,#604,.T.);
#606=EDGE_LOOP('',(#582,#590,#599,#605));
#607=FACE_BOUND('',#606,.T.);
#608=ADVANCED_FACE('F771',(#607),#571,.T.);
#609=CARTESIAN_POINT('',(0.,12.,0.));
#610=DIRECTION('',(0.,-1.,0.));
#611=DIRECTION('',(0.,0.,-1.));
#612=AXIS2_PLACEMENT_3D('',#609,#610,#611);
#613=CYLINDRICAL_SURFACE('',#612,3.95);
#614=CARTESIAN_POINT('',(0.,7.5,0.));
#615=DIRECTION('',(0.,-1.,0.));
#616=DIRECTION('',(0.,0.,1.));
#617=AXIS2_PLACEMENT_3D('',#614,#615,#616);
#618=CIRCLE('',#617,3.95);
#619=CARTESIAN_POINT('',(3.13837533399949,7.5,-2.3985621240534));
#620=VERTEX_POINT('',#619);
#621=EDGE_CURVE('E946',#580,#620,#618,.T.);
#622=ORIENTED_EDGE('',*,*,#621,.T.);
#623=DIRECTION('',(0.,-1.,0.));
#624=VECTOR('',#623,1.);
#625=CARTESIAN_POINT('',(3.13837533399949,12.,-2.3985621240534));
#626=LINE('',#625,#624);
#627=EDGE_CURVE('E948',#537,#620,#626,.T.);
#628=ORIENTED_EDGE('',*,*,#627,.F.);
#629=ORIENTED_EDGE('',*,*,#538,.F.);
#630=CARTESIAN_POINT('',(0.,12.,0.));
#631=DIRECTION('',(0.,-1.,0.));
#632=DIRECTION('',(0.,0.,1.));
#633=AXIS2_PLACEMENT_3D('',#630,#631,#632);
#634=CIRCLE('',#633,3.95);
#635=CARTESIAN_POINT('',(1.83720930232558,12.,3.496735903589));
#636=VERTEX_POINT('',#635);
#637=EDGE_CURVE('E621',#636,#467,#634,.T.);
#638=ORIENTED_EDGE('',*,*,#637,.F.);
#639=CARTESIAN_POINT('',(3.13837533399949,12.,2.3985621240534));
#640=CARTESIAN_POINT('',(2.951200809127,12.,2.64332750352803));
#641=CARTESIAN_POINT('',(2.72885086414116,12.,2.85584890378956));
#642=CARTESIAN_POINT('',(2.50669556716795,12.,3.06818426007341));
#643=CARTESIAN_POINT('',(2.25342095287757,12.,3.24416306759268));
#644=CARTESIAN_POINT('',(2.00104968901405,12.,3.41951421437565));
#645=CARTESIAN_POINT('',(1.72356787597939,12.,3.55412630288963));
#646=CARTESIAN_POINT('',(1.44707575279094,12.,3.68825827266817));
#647=CARTESIAN_POINT('',(1.15208830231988,12.,3.77825257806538));
#648=CARTESIAN_POINT('',(0.858152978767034,12.,3.86792590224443));
#649=CARTESIAN_POINT('',(0.552784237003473,12.,3.91112894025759));
#650=CARTESIAN_POINT('',(0.248504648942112,12.,3.95417788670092));
#651=CARTESIAN_POINT('',(-0.0598703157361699,12.,3.94954624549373));
#652=CARTESIAN_POINT('',(-0.367145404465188,12.,3.94493112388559));
#653=CARTESIAN_POINT('',(-0.671078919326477,12.,3.89257666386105));
#654=CARTESIAN_POINT('',(-0.973928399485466,12.,3.8404089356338));
#655=CARTESIAN_POINT('',(-1.26608005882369,12.,3.74159608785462));
#656=CARTESIAN_POINT('',(-1.55718970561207,12.,3.64313567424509));
#657=CARTESIAN_POINT('',(-1.83050365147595,12.,3.50025090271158));
#658=CARTESIAN_POINT('',(-2.10284277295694,12.,3.35787575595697));
#659=CARTESIAN_POINT('',(-2.35071810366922,12.,3.17436992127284));
#660=CARTESIAN_POINT('',(-2.5977093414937,12.,2.99151859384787));
#661=CARTESIAN_POINT('',(-2.81415953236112,12.,2.77182361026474));
#662=CARTESIAN_POINT('',(-3.02983771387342,12.,2.55291220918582));
#663=CARTESIAN_POINT('',(-3.20963519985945,12.,2.30233400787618));
#664=CARTESIAN_POINT('',(-3.3887914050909,12.,2.05264953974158));
#665=CARTESIAN_POINT('',(-3.52759383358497,12.,1.77723992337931));
#666=CARTESIAN_POINT('',(-3.66590119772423,12.,1.50281260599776));
#667=CARTESIAN_POINT('',(-3.7603563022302,12.,1.20922308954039));
#668=CARTESIAN_POINT('',(-3.85447451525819,12.,0.916680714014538));
#669=CARTESIAN_POINT('',(-3.90230107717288,12.,0.612001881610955));
#670=CARTESIAN_POINT('',(-3.94995705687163,12.,0.308409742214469));
#671=CARTESIAN_POINT('',(-3.95,12.,0.));
#672=CARTESIAN_POINT('',(-3.95004278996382,12.,-0.307309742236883));
#673=CARTESIAN_POINT('',(-3.90230107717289,12.,-0.612001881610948));
#674=CARTESIAN_POINT('',(-3.8547296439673,12.,-0.915607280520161));
#675=CARTESIAN_POINT('',(-3.7603563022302,12.,-1.20922308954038));
#676=CARTESIAN_POINT('',(-3.66631956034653,12.,-1.50179166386));
#677=CARTESIAN_POINT('',(-3.52759383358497,12.,-1.7772399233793));
#678=CARTESIAN_POINT('',(-3.38936289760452,12.,-2.05170574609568));
#679=CARTESIAN_POINT('',(-3.20963519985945,12.,-2.30233400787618));
#680=CARTESIAN_POINT('',(-3.03054853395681,12.,-2.55206835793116));
#681=CARTESIAN_POINT('',(-2.81415953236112,12.,-2.77182361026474));
#682=CARTESIAN_POINT('',(-2.5985423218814,12.,-2.99079506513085));
#683=CARTESIAN_POINT('',(-2.35071810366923,12.,-3.17436992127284));
#684=CARTESIAN_POINT('',(-2.10377779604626,12.,-3.35729002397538));
#685=CARTESIAN_POINT('',(-1.83050365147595,12.,-3.50025090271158));
#686=CARTESIAN_POINT('',(-1.55820418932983,12.,-3.64270188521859));
#687=CARTESIAN_POINT('',(-1.26608005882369,12.,-3.74159608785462));
#688=CARTESIAN_POINT('',(-0.974997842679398,12.,-3.84013756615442));
#689=CARTESIAN_POINT('',(-0.671078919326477,12.,-3.89257666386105));
#690=CARTESIAN_POINT('',(-0.368243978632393,12.,-3.94482872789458));
#691=CARTESIAN_POINT('',(-0.0598703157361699,12.,-3.94954624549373));
#692=CARTESIAN_POINT('',(0.247403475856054,12.,-3.95424693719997));
#693=CARTESIAN_POINT('',(0.552784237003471,12.,-3.91112894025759));
#694=CARTESIAN_POINT('',(0.857075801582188,12.,-3.86816473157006));
#695=CARTESIAN_POINT('',(1.15208830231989,12.,-3.77825257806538));
#696=CARTESIAN_POINT('',(1.44604858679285,12.,-3.68866111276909));
#697=CARTESIAN_POINT('',(1.7235678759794,12.,-3.55412630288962));
#698=CARTESIAN_POINT('',(2.0000973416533,12.,-3.42007133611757));
#699=CARTESIAN_POINT('',(2.25342095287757,12.,-3.24416306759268));
#700=CARTESIAN_POINT('',(2.50584103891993,12.,-3.06888220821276));
#701=CARTESIAN_POINT('',(2.72885086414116,12.,-2.85584890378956));
#702=CARTESIAN_POINT('',(2.95086468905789,12.,-2.64376704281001));
#703=CARTESIAN_POINT('',(3.13837533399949,12.,-2.3985621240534));
#704=B_SPLINE_CURVE_WITH_KNOTS('',2,(#639,#640,#641,#642,#643,#644,#645,#646,#647,#648,#649,
#650,#651,#652,#653,#654,#655,#656,#657,#658,#659,#660,#661,#662,#663,#664,#665,#666,#667,#668,
#669,#670,#671,#672,#673,#674,#675,#676,#677,#678,#679,#680,#681,#682,#683,#684,#685,#686,#687,
#688,#689,#690,#691,#692,#693,#694,#695,#696,#697,#698,#699,#700,#701,#702,#703),.UNSPECIFIED.,
.F.,.F.,(3,2,2,2,2,2,2,2,2,2,2,2,2,2,2,2,2,2,2,2,2,2,2,2,2,2,2,2,2,2,2,2,3),(0.,0.03125,0.0625,
0.09375,0.125,0.15625,0.1875,0.21875,0.25,0.28125,0.3125,0.34375,0.375,0.40625,0.4375,0.46875,
0.5,0.53125,0.5625,0.59375,0.625,0.65625,0.6875,0.71875,0.75,0.78125,0.8125,0.84375,0.875,
0.90625,0.9375,0.96875,1.),.UNSPECIFIED.);
#705=EDGE_CURVE('E844',#588,#636,#704,.T.);
#706=ORIENTED_EDGE('',*,*,#705,.F.);
#707=ORIENTED_EDGE('',*,*,#589,.T.);
#708=EDGE_LOOP('',(#622,#628,#629,#638,#706,#707));
#709=FACE_BOUND('',#708,.T.);
#710=ADVANCED_FACE('F827',(#709),#613,.F.);
#711=CARTESIAN_POINT('',(4.44934224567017,12.,-3.4004931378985));
#712=DIRECTION('',(0.,-1.,0.));
#713=DIRECTION('',(0.,0.,-1.));
#714=AXIS2_PLACEMENT_3D('',#711,#712,#713);
#715=CYLINDRICAL_SURFACE('',#714,1.65);
#716=CARTESIAN_POINT('',(4.44934224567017,7.5,-3.4004931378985));
#717=DIRECTION('',(0.,1.,0.));
#718=DIRECTION('',(0.,0.,1.));
#719=AXIS2_PLACEMENT_3D('',#716,#717,#718);
#720=CIRCLE('',#719,1.65);
#721=CARTESIAN_POINT('',(6.05,7.5,-3.));
#722=VERTEX_POINT('',#721);
#723=EDGE_CURVE('E953',#620,#722,#720,.T.);
#724=ORIENTED_EDGE('',*,*,#723,.T.);
#725=DIRECTION('',(0.,-1.,0.));
#726=VECTOR('',#725,1.);
#727=CARTESIAN_POINT('',(6.05,12.,-3.));
#728=LINE('',#727,#726);
#729=EDGE_CURVE('E859',#546,#722,#728,.T.);
#730=ORIENTED_EDGE('',*,*,#729,.F.);
#731=ORIENTED_EDGE('',*,*,#547,.F.);
#732=ORIENTED_EDGE('',*,*,#627,.T.);
#733=EDGE_LOOP('',(#724,#730,#731,#732));
#734=FACE_BOUND('',#733,.T.);
#735=ADVANCED_FACE('F894',(#734),#715,.T.);
#736=CARTESIAN_POINT('',(5.71046653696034,12.,-3.08495308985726));
#737=DIRECTION('',(-0.242723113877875,0.,0.970095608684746));
#738=DIRECTION('',(0.970095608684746,0.,0.242723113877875));
#739=AXIS2_PLACEMENT_3D('',#736,#737,#738);
#740=PLANE('',#739);
#741=DIRECTION('',(-0.970095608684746,0.,-0.242723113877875));
#742=VECTOR('',#741,1.);
#743=CARTESIAN_POINT('',(5.71046653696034,7.5,-3.08495308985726));
#744=LINE('',#743,#742);
#745=CARTESIAN_POINT('',(5.71046653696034,7.5,-3.08495308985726));
#746=VERTEX_POINT('',#745);
#747=EDGE_CURVE('E960',#722,#746,#744,.T.);
#748=ORIENTED_EDGE('',*,*,#747,.T.);
#749=DIRECTION('',(0.,-1.,0.));
#750=VECTOR('',#749,1.);
#751=CARTESIAN_POINT('',(5.71046653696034,12.,-3.08495308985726));
#752=LINE('',#751,#750);
#753=EDGE_CURVE('E980',#554,#746,#752,.T.);
#754=ORIENTED_EDGE('',*,*,#753,.F.);
#755=ORIENTED_EDGE('',*,*,#555,.F.);
#756=ORIENTED_EDGE('',*,*,#729,.T.);
#757=EDGE_LOOP('',(#748,#754,#755,#756));
#758=FACE_BOUND('',#757,.T.);
#759=ADVANCED_FACE('F897',(#758),#740,.F.);
#760=CARTESIAN_POINT('',(4.44934224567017,12.,-3.4004931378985));
#761=DIRECTION('',(0.,-1.,0.));
#762=DIRECTION('',(0.,0.,-1.));
#763=AXIS2_PLACEMENT_3D('',#760,#761,#762);
#764=CYLINDRICAL_SURFACE('',#763,1.3);
#765=CARTESIAN_POINT('',(4.44934224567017,7.5,-3.4004931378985));
#766=DIRECTION('',(0.,-1.,0.));
#767=DIRECTION('',(0.,0.,1.));
#768=AXIS2_PLACEMENT_3D('',#765,#766,#767);
#769=CIRCLE('',#768,1.3);
#770=CARTESIAN_POINT('',(3.41645922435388,7.5,-2.61109294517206));
#771=VERTEX_POINT('',#770);
#772=EDGE_CURVE('E962',#746,#771,#769,.T.);
#773=ORIENTED_EDGE('',*,*,#772,.T.);
#774=DIRECTION('',(0.,-1.,0.));
#775=VECTOR('',#774,1.);
#776=CARTESIAN_POINT('',(3.41645922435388,12.,-2.61109294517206));
#777=LINE('',#776,#775);
#778=EDGE_CURVE('E982',#457,#771,#777,.T.);
#779=ORIENTED_EDGE('',*,*,#778,.F.);
#780=ORIENTED_EDGE('',*,*,#562,.F.);
#781=ORIENTED_EDGE('',*,*,#753,.T.);
#782=EDGE_LOOP('',(#773,#779,#780,#781));
#783=FACE_BOUND('',#782,.T.);
#784=ADVANCED_FACE('F901',(#783),#764,.F.);
#785=CARTESIAN_POINT('',(0.,12.,0.));
#786=DIRECTION('',(0.,-1.,0.));
#787=DIRECTION('',(0.,0.,-1.));
#788=AXIS2_PLACEMENT_3D('',#785,#786,#787);
#789=CYLINDRICAL_SURFACE('',#788,4.3);
#790=CARTESIAN_POINT('',(0.,7.5,0.));
#791=DIRECTION('',(0.,1.,0.));
#792=DIRECTION('',(0.,0.,1.));
#793=AXIS2_PLACEMENT_3D('',#790,#791,#792);
#794=CIRCLE('',#793,4.3);
#795=CARTESIAN_POINT('',(3.41645922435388,7.5,2.61109294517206));
#796=VERTEX_POINT('',#795);
#797=EDGE_CURVE('E967',#771,#796,#794,.T.);
#798=ORIENTED_EDGE('',*,*,#797,.T.);
#799=DIRECTION('',(0.,-1.,0.));
#800=VECTOR('',#799,1.);
#801=CARTESIAN_POINT('',(3.41645922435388,12.,2.61109294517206));
#802=LINE('',#801,#800);
#803=CARTESIAN_POINT('',(3.41645922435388,12.,2.61109294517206));
#804=VERTEX_POINT('',#803);
#805=EDGE_CURVE('E979',#804,#796,#802,.T.);
#806=ORIENTED_EDGE('',*,*,#805,.F.);
#807=CARTESIAN_POINT('',(3.41645922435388,12.,-2.61109294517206));
#808=CARTESIAN_POINT('',(3.21272026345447,12.,-2.87753191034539));
#809=CARTESIAN_POINT('',(2.97064777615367,12.,-3.10889880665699));
#810=CARTESIAN_POINT('',(2.72876998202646,12.,-3.34007962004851));
#811=CARTESIAN_POINT('',(2.45309116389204,12.,-3.53162055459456));
#812=CARTESIAN_POINT('',(2.17831570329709,12.,-3.72253383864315));
#813=CARTESIAN_POINT('',(1.8762890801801,12.,-3.86904888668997));
#814=CARTESIAN_POINT('',(1.5752521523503,12.,-4.01508382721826));
#815=CARTESIAN_POINT('',(1.25417207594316,12.,-4.11303445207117));
#816=CARTESIAN_POINT('',(0.934144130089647,12.,-4.21066410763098));
#817=CARTESIAN_POINT('',(0.60176511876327,12.,-4.25768466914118));
#818=CARTESIAN_POINT('',(0.270475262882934,12.,-4.30455115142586));
#819=CARTESIAN_POINT('',(-0.0651752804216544,12.,-4.29950603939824));
#820=CARTESIAN_POINT('',(-0.399725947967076,12.,-4.2944774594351));
#821=CARTESIAN_POINT('',(-0.730541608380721,12.,-4.23748852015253));
#822=CARTESIAN_POINT('',(-1.06027323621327,12.,-4.18068632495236));
#823=CARTESIAN_POINT('',(-1.37826436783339,12.,-4.07312991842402));
#824=CARTESIAN_POINT('',(-1.69521349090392,12.,-3.965925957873));
#825=CARTESIAN_POINT('',(-1.9927001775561,12.,-3.81039971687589));
#826=CARTESIAN_POINT('',(-2.28921204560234,12.,-3.65538311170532));
#827=CARTESIAN_POINT('',(-2.55900958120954,12.,-3.45564320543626));
#828=CARTESIAN_POINT('',(-2.82792303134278,12.,-3.25655781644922));
#829=CARTESIAN_POINT('',(-3.06351544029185,12.,-3.01742823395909));
#830=CARTESIAN_POINT('',(-3.29833584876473,12.,-2.77908224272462));
#831=CARTESIAN_POINT('',(-3.4940332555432,12.,-2.50633828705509));
#832=CARTESIAN_POINT('',(-3.68908939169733,12.,-2.23448807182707));
#833=CARTESIAN_POINT('',(-3.8401654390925,12.,-1.93471687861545));
#834=CARTESIAN_POINT('',(-3.990746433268,12.,-1.63592798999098));
#835=CARTESIAN_POINT('',(-4.09355243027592,12.,-1.3163694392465));
#836=CARTESIAN_POINT('',(-4.19602154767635,12.,-0.997858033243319));
#837=CARTESIAN_POINT('',(-4.2480745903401,12.,-0.666229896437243));
#838=CARTESIAN_POINT('',(-4.29995706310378,12.,-0.335688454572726));
#839=CARTESIAN_POINT('',(-4.3,12.,0.));
#840=CARTESIAN_POINT('',(-4.30004279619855,12.,0.334588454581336));
#841=CARTESIAN_POINT('',(-4.2480745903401,12.,0.666229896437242));
#842=CARTESIAN_POINT('',(-4.19627667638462,12.,0.996784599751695));
#843=CARTESIAN_POINT('',(-4.09355243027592,12.,1.3163694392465));
#844=CARTESIAN_POINT('',(-3.99116479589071,12.,1.63490704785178));
#845=CARTESIAN_POINT('',(-3.8401654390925,12.,1.93471687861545));
#846=CARTESIAN_POINT('',(-3.6896608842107,12.,2.23354427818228));
#847=CARTESIAN_POINT('',(-3.4940332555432,12.,2.50633828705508));
#848=CARTESIAN_POINT('',(-3.29904666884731,12.,2.77823839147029));
#849=CARTESIAN_POINT('',(-3.06351544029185,12.,3.01742823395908));
#850=CARTESIAN_POINT('',(-2.82875601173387,12.,3.25583428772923));
#851=CARTESIAN_POINT('',(-2.55900958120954,12.,3.45564320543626));
#852=CARTESIAN_POINT('',(-2.29014706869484,12.,3.65479737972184));
#853=CARTESIAN_POINT('',(-1.9927001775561,12.,3.81039971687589));
#854=CARTESIAN_POINT('',(-1.69622797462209,12.,3.96549216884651));
#855=CARTESIAN_POINT('',(-1.37826436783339,12.,4.07312991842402));
#856=CARTESIAN_POINT('',(-1.06134267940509,12.,4.18041495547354));
#857=CARTESIAN_POINT('',(-0.730541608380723,12.,4.23748852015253));
#858=CARTESIAN_POINT('',(-0.400824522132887,12.,4.29437506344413));
#859=CARTESIAN_POINT('',(-0.0651752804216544,12.,4.29950603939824));
#860=CARTESIAN_POINT('',(0.269374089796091,12.,4.30462020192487));
#861=CARTESIAN_POINT('',(0.601765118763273,12.,4.25768466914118));
#862=CARTESIAN_POINT('',(0.933066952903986,12.,4.21090293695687));
#863=CARTESIAN_POINT('',(1.25417207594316,12.,4.11303445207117));
#864=CARTESIAN_POINT('',(1.57422498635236,12.,4.01548666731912));
#865=CARTESIAN_POINT('',(1.8762890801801,12.,3.86904888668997));
#866=CARTESIAN_POINT('',(2.17736335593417,12.,3.7230909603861));
#867=CARTESIAN_POINT('',(2.45309116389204,12.,3.53162055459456));
#868=CARTESIAN_POINT('',(2.72791545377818,12.,3.34077756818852));
#869=CARTESIAN_POINT('',(2.97064777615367,12.,3.10889880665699));
#870=CARTESIAN_POINT('',(3.21238415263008,12.,2.87797145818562));
#871=CARTESIAN_POINT('',(3.41645922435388,12.,2.61109294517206));
#872=B_SPLINE_CURVE_WITH_KNOTS('',2,(#807,#808,#809,#810,#811,#812,#813,#814,#815,#816,#817,
#818,#819,#820,#821,#822,#823,#824,#825,#826,#827,#828,#829,#830,#831,#832,#833,#834,#835,#836,
#837,#838,#839,#840,#841,#842,#843,#844,#845,#846,#847,#848,#849,#850,#851,#852,#853,#854,#855,
#856,#857,#858,#859,#860,#861,#862,#863,#864,#865,#866,#867,#868,#869,#870,#871),.UNSPECIFIED.,
.F.,.F.,(3,2,2,2,2,2,2,2,2,2,2,2,2,2,2,2,2,2,2,2,2,2,2,2,2,2,2,2,2,2,2,2,3),(0.,0.03125,0.0625,
0.09375,0.125,0.15625,0.1875,0.21875,0.25,0.28125,0.3125,0.34375,0.375,0.40625,0.4375,0.46875,
0.5,0.53125,0.5625,0.59375,0.625,0.65625,0.6875,0.71875,0.75,0.78125,0.8125,0.84375,0.875,
0.90625,0.9375,0.96875,1.),.UNSPECIFIED.);
#873=CARTESIAN_POINT('',(2.00000389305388,12.,3.8065806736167));
#874=VERTEX_POINT('',#873);
#875=EDGE_CURVE('E929',#874,#804,#872,.T.);
#876=ORIENTED_EDGE('',*,*,#875,.F.);
#877=CARTESIAN_POINT('',(0.,12.,0.));
#878=DIRECTION('',(0.,1.,0.));
#879=DIRECTION('',(0.,0.,1.));
#880=AXIS2_PLACEMENT_3D('',#877,#878,#879);
#881=CIRCLE('',#880,4.3);
#882=EDGE_CURVE('E411',#459,#874,#881,.T.);
#883=ORIENTED_EDGE('',*,*,#882,.F.);
#884=ORIENTED_EDGE('',*,*,#460,.F.);
#885=ORIENTED_EDGE('',*,*,#778,.T.);
#886=EDGE_LOOP('',(#798,#806,#876,#883,#884,#885));
#887=FACE_BOUND('',#886,.T.);
#888=ADVANCED_FACE('F905',(#887),#789,.T.);
#889=CARTESIAN_POINT('',(4.44934224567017,12.,3.4004931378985));
#890=DIRECTION('',(0.,-1.,0.));
#891=DIRECTION('',(0.,0.,-1.));
#892=AXIS2_PLACEMENT_3D('',#889,#890,#891);
#893=CYLINDRICAL_SURFACE('',#892,1.3);
#894=CARTESIAN_POINT('',(4.44934224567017,7.5,3.4004931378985));
#895=DIRECTION('',(0.,-1.,0.));
#896=DIRECTION('',(0.,0.,-1.));
#897=AXIS2_PLACEMENT_3D('',#894,#895,#896);
#898=CIRCLE('',#897,1.3);
#899=CARTESIAN_POINT('',(5.71046653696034,7.5,3.08495308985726));
#900=VERTEX_POINT('',#899);
#901=EDGE_CURVE('E969',#796,#900,#898,.T.);
#902=ORIENTED_EDGE('',*,*,#901,.T.);
#903=DIRECTION('',(0.,-1.,0.));
#904=VECTOR('',#903,1.);
#905=CARTESIAN_POINT('',(5.71046653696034,12.,3.08495308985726));
#906=LINE('',#905,#904);
#907=CARTESIAN_POINT('',(5.71046653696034,12.,3.08495308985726));
#908=VERTEX_POINT('',#907);
#909=EDGE_CURVE('E976',#908,#900,#906,.T.);
#910=ORIENTED_EDGE('',*,*,#909,.F.);
#911=CARTESIAN_POINT('',(4.44934224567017,12.,3.4004931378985));
#912=DIRECTION('',(0.,-1.,0.));
#913=DIRECTION('',(0.,0.,-1.));
#914=AXIS2_PLACEMENT_3D('',#911,#912,#913);
#915=CIRCLE('',#914,1.3);
#916=EDGE_CURVE('E997',#804,#908,#915,.T.);
#917=ORIENTED_EDGE('',*,*,#916,.F.);
#918=ORIENTED_EDGE('',*,*,#805,.T.);
#919=EDGE_LOOP('',(#902,#910,#917,#918));
#920=FACE_BOUND('',#919,.T.);
#921=ADVANCED_FACE('F838',(#920),#893,.F.);
#922=CARTESIAN_POINT('',(5.71046653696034,12.,3.08495308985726));
#923=DIRECTION('',(-0.242723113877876,0.,-0.970095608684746));
#924=DIRECTION('',(-0.970095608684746,0.,0.242723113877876));
#925=AXIS2_PLACEMENT_3D('',#922,#923,#924);
#926=PLANE('',#925);
#927=DIRECTION('',(0.970095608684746,0.,-0.242723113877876));
#928=VECTOR('',#927,1.);
#929=CARTESIAN_POINT('',(5.71046653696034,7.5,3.08495308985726));
#930=LINE('',#929,#928);
#931=EDGE_CURVE('E971',#900,#578,#930,.T.);
#932=ORIENTED_EDGE('',*,*,#931,.T.);
#933=ORIENTED_EDGE('',*,*,#604,.F.);
#934=DIRECTION('',(0.970095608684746,0.,-0.242723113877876));
#935=VECTOR('',#934,1.);
#936=CARTESIAN_POINT('',(5.71046653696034,12.,3.08495308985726));
#937=LINE('',#936,#935);
#938=EDGE_CURVE('E977',#908,#597,#937,.T.);
#939=ORIENTED_EDGE('',*,*,#938,.F.);
#940=ORIENTED_EDGE('',*,*,#909,.T.);
#941=EDGE_LOOP('',(#932,#933,#939,#940));
#942=FACE_BOUND('',#941,.T.);
#943=ADVANCED_FACE('F831',(#942),#926,.F.);
#944=ORIENTED_EDGE('',*,*,#705,.T.);
#945=DIRECTION('',(-0.465116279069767,0.,-0.885249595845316));
#946=VECTOR('',#945,1.);
#947=CARTESIAN_POINT('',(1.83720930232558,12.,3.496735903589));
#948=LINE('',#947,#946);
#949=EDGE_CURVE('E847',#874,#636,#948,.T.);
#950=ORIENTED_EDGE('',*,*,#949,.F.);
#951=ORIENTED_EDGE('',*,*,#875,.T.);
#952=ORIENTED_EDGE('',*,*,#916,.T.);
#953=ORIENTED_EDGE('',*,*,#938,.T.);
#954=ORIENTED_EDGE('',*,*,#598,.T.);
#955=EDGE_LOOP('',(#944,#950,#951,#952,#953,#954));
#956=FACE_BOUND('',#955,.T.);
#957=ADVANCED_FACE('F533',(#956),#389,.F.);
#958=CARTESIAN_POINT('',(4.44934224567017,7.5,3.4004931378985));
#959=DIRECTION('',(0.,-1.,0.));
#960=DIRECTION('',(0.,0.,-1.));
#961=AXIS2_PLACEMENT_3D('',#958,#959,#960);
#962=PLANE('',#961);
#963=ORIENTED_EDGE('',*,*,#581,.F.);
#964=ORIENTED_EDGE('',*,*,#931,.F.);
#965=ORIENTED_EDGE('',*,*,#901,.F.);
#966=ORIENTED_EDGE('',*,*,#797,.F.);
#967=ORIENTED_EDGE('',*,*,#772,.F.);
#968=ORIENTED_EDGE('',*,*,#747,.F.);
#969=ORIENTED_EDGE('',*,*,#723,.F.);
#970=ORIENTED_EDGE('',*,*,#621,.F.);
#971=EDGE_LOOP('',(#963,#964,#965,#966,#967,#968,#969,#970));
#972=FACE_BOUND('',#971,.T.);
#973=ADVANCED_FACE('F569',(#972),#962,.T.);
#974=CARTESIAN_POINT('',(-2.,14.,4.35));
#975=CARTESIAN_POINT('',(-2.,12.,3.80657326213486));
#976=CARTESIAN_POINT('',(-2.,14.,4.29166666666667));
#977=CARTESIAN_POINT('',(-1.97286821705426,12.,3.75493370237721));
#978=CARTESIAN_POINT('',(-2.,14.,4.23333333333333));
#979=CARTESIAN_POINT('',(-1.94573643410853,12.,3.70329414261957));
#980=CARTESIAN_POINT('',(-2.,14.,4.11666666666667));
#981=CARTESIAN_POINT('',(-1.89147286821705,12.,3.60001502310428));
#982=CARTESIAN_POINT('',(-2.,14.,4.05833333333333));
#983=CARTESIAN_POINT('',(-1.86434108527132,12.,3.54837546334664));
#984=CARTESIAN_POINT('',(-2.,14.,4.));
#985=CARTESIAN_POINT('',(-1.83720930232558,12.,3.496735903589));
#986=CARTESIAN_POINT('',(-2.,14.,3.99369032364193));
#987=CARTESIAN_POINT('',(-1.83427456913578,12.,3.4911502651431));
#988=CARTESIAN_POINT('',(-2.,14.,3.98738064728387));
#989=CARTESIAN_POINT('',(-1.83133983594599,12.,3.48556462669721));
#990=CARTESIAN_POINT('',(-2.,14.,3.9810709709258));
#991=CARTESIAN_POINT('',(-1.82840510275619,12.,3.47997898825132));
#992=B_SPLINE_SURFACE_WITH_KNOTS('',3,1,((#974,#975),(#976,#977),(#978,#979),(#980,#981),(#982,
#983),(#984,#985),(#986,#987),(#988,#989),(#990,#991)),.UNSPECIFIED.,.F.,.F.,.F.,(4,2,3,4),(2,
2),(0.,0.5,1.,1.05408294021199),(0.,1.),.UNSPECIFIED.);
#993=DIRECTION('',(0.,0.965011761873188,0.26220659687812));
#994=VECTOR('',#993,1.);
#995=CARTESIAN_POINT('',(-2.,13.,4.07828663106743));
#996=LINE('',#995,#994);
#997=CARTESIAN_POINT('',(-2.,13.7289397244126,4.27634929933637));
#998=VERTEX_POINT('',#997);
#999=EDGE_CURVE('E414',#459,#998,#996,.T.);
#1000=CARTESIAN_POINT('',(-2.,13.7289397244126,4.27634929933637));
#1001=CARTESIAN_POINT('',(-2.00000002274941,13.7512069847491,4.28239992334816));
#1002=CARTESIAN_POINT('',(-1.99997486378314,13.7735737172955,4.28808447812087));
#1003=CARTESIAN_POINT('',(-1.99991204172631,13.8184577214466,4.29870887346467));
#1004=CARTESIAN_POINT('',(-1.99987439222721,13.8409748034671,4.30364951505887));
#1005=CARTESIAN_POINT('',(-1.99982428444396,13.886159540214,4.31278666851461));
#1006=CARTESIAN_POINT('',(-1.9998118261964,13.9088271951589,4.31698317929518));
#1007=CARTESIAN_POINT('',(-1.99984949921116,13.9543129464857,4.32463209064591));
#1008=CARTESIAN_POINT('',(-1.99989969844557,13.9771311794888,4.3280836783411));
#1009=CARTESIAN_POINT('',(-2.,14.,4.33115825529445));
#1010=B_SPLINE_CURVE_WITH_KNOTS('',3,(#1000,#1001,#1002,#1003,#1004,#1005,#1006,#1007,#1008,
#1009),.UNSPECIFIED.,.F.,.F.,(4,2,2,2,4),(0.,0.0692209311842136,0.138366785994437,
0.207512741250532,0.276733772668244),.UNSPECIFIED.);
#1011=CARTESIAN_POINT('',(-2.,14.,4.33115825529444));
#1012=VERTEX_POINT('',#1011);
#1013=EDGE_CURVE('E432',#998,#1012,#1010,.T.);
#1014=DIRECTION('',(0.,0.,-1.));
#1015=VECTOR('',#1014,1.);
#1016=CARTESIAN_POINT('',(-2.,14.,4.35));
#1017=LINE('',#1016,#1015);
#1018=CARTESIAN_POINT('',(-2.,14.,4.));
#1019=VERTEX_POINT('',#1018);
#1020=EDGE_CURVE('E476',#1012,#1019,#1017,.T.);
#1021=CARTESIAN_POINT('',(-2.,14.,4.));
#1022=CARTESIAN_POINT('',(-2.,14.,3.99442378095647));
#1023=CARTESIAN_POINT('',(-2.,14.,3.98884756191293));
#1024=CARTESIAN_POINT('',(-2.,14.,3.9832713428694));
#1025=B_SPLINE_CURVE_WITH_KNOTS('',3,(#1021,#1022,#1023,#1024),.UNSPECIFIED.,.F.,.F.,(4,4),(0.,
0.0167286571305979),.UNSPECIFIED.);
#1026=CARTESIAN_POINT('',(-2.00000000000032,14.0000000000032,3.9832713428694));
#1027=VERTEX_POINT('',#1026);
#1028=EDGE_CURVE('E13',#1019,#1027,#1025,.T.);
#1029=CARTESIAN_POINT('',(-7.17857757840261,13.3699722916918,3.09355494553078));
#1030=CARTESIAN_POINT('',(-7.12329571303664,13.9593317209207,4.));
#1031=CARTESIAN_POINT('',(-7.02219084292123,15.0372097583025,4.));
#1032=CARTESIAN_POINT('',(-6.97907195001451,13.366697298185,3.11701178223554));
#1033=CARTESIAN_POINT('',(-6.92228907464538,13.9586150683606,4.));
#1034=CARTESIAN_POINT('',(-6.81848099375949,15.0180952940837,4.));
#1035=CARTESIAN_POINT('',(-6.77980571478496,13.3638828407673,3.14176437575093));
#1036=CARTESIAN_POINT('',(-6.72071258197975,13.9578994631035,4.));
#1037=CARTESIAN_POINT('',(-6.61486306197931,14.997955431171,4.));
#1038=CARTESIAN_POINT('',(-6.38150886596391,13.3599759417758,3.19413818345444));
#1039=CARTESIAN_POINT('',(-6.31743963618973,13.9565648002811,4.));
#1040=CARTESIAN_POINT('',(-6.20786480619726,14.9552869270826,4.));
#1041=CARTESIAN_POINT('',(-6.18247826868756,13.3588836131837,3.22175958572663));
#1042=CARTESIAN_POINT('',(-6.11590431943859,13.9559454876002,4.));
#1043=CARTESIAN_POINT('',(-6.00448449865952,14.9327581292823,4.));
#1044=CARTESIAN_POINT('',(-5.78442756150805,13.3592225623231,3.28014629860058));
#1045=CARTESIAN_POINT('',(-5.71259752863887,13.9548888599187,4.));
#1046=CARTESIAN_POINT('',(-5.59803375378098,14.8849752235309,4.));
#1047=CARTESIAN_POINT('',(-5.58540745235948,13.3606539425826,3.31091173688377));
#1048=CARTESIAN_POINT('',(-5.51099714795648,13.9544503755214,4.));
#1049=CARTESIAN_POINT('',(-5.3949633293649,14.8597210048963,4.));
#1050=CARTESIAN_POINT('',(-5.18689478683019,13.3672669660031,3.37571865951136));
#1051=CARTESIAN_POINT('',(-5.10732346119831,13.9539052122,4.));
#1052=CARTESIAN_POINT('',(-4.98923243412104,14.8061227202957,4.));
#1053=CARTESIAN_POINT('',(-4.98740223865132,13.3724485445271,3.40976008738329));
#1054=CARTESIAN_POINT('',(-4.90542248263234,13.9537955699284,4.));
#1055=CARTESIAN_POINT('',(-4.78657195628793,14.7777787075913,4.));
#1056=CARTESIAN_POINT('',(-4.58749312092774,13.388213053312,3.48086875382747));
#1057=CARTESIAN_POINT('',(-4.50117065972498,13.9541292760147,4.));
#1058=CARTESIAN_POINT('',(-4.38215543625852,14.7177124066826,4.));
#1059=CARTESIAN_POINT('',(-4.38707912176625,13.3987853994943,3.51792994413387));
#1060=CARTESIAN_POINT('',(-4.29898109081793,13.9545657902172,4.));
#1061=CARTESIAN_POINT('',(-4.1803984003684,14.6859968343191,4.));
#1062=CARTESIAN_POINT('',(-3.98363975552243,13.4274478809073,3.59427913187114));
#1063=CARTESIAN_POINT('',(-3.89326918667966,13.9562851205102,4.));
#1064=CARTESIAN_POINT('',(-3.77749676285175,14.6188915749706,4.));
#1065=CARTESIAN_POINT('',(-3.78061440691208,13.4455379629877,3.63356711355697));
#1066=CARTESIAN_POINT('',(-3.68985163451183,13.9575585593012,4.));
#1067=CARTESIAN_POINT('',(-3.5763521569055,14.5835019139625,4.));
#1068=CARTESIAN_POINT('',(-3.37020604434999,13.4915720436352,3.71223733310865));
#1069=CARTESIAN_POINT('',(-3.28110717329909,13.9612639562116,4.));
#1070=CARTESIAN_POINT('',(-3.17477192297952,14.5090281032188,4.));
#1071=CARTESIAN_POINT('',(-3.16282352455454,13.5195149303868,3.75161955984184));
#1072=CARTESIAN_POINT('',(-3.07577085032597,13.9636837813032,4.));
#1073=CARTESIAN_POINT('',(-2.97433621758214,14.4699443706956,4.));
#1074=CARTESIAN_POINT('',(-2.84736617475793,13.569708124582,3.80763379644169));
#1075=CARTESIAN_POINT('',(-2.76539141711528,13.9682017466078,4.));
#1076=CARTESIAN_POINT('',(-2.67418293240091,14.4088804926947,4.));
#1077=CARTESIAN_POINT('',(-2.74148275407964,13.5878190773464,3.82579541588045));
#1078=CARTESIAN_POINT('',(-2.66187451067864,13.9698487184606,4.));
#1079=CARTESIAN_POINT('',(-2.57421486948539,14.3881194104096,4.));
#1080=CARTESIAN_POINT('',(-2.52822876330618,13.626648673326,3.86037644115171));
#1081=CARTESIAN_POINT('',(-2.45432289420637,13.9733671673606,4.));
#1082=CARTESIAN_POINT('',(-2.3744252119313,14.345904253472,4.));
#1083=CARTESIAN_POINT('',(-2.42085819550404,13.6473673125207,3.87679584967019));
#1084=CARTESIAN_POINT('',(-2.35024051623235,13.9752384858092,4.));
#1085=CARTESIAN_POINT('',(-2.27460361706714,14.3244501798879,4.));
#1086=CARTESIAN_POINT('',(-2.28513978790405,13.6747910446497,3.89587610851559));
#1087=CARTESIAN_POINT('',(-2.21904535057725,13.9776651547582,4.));
#1088=CARTESIAN_POINT('',(-2.14929561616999,14.2971613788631,4.));
#1089=CARTESIAN_POINT('',(-2.25742700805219,13.6804548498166,3.89968532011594));
#1090=CARTESIAN_POINT('',(-2.19232125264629,13.9781629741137,4.));
#1091=CARTESIAN_POINT('',(-2.12375361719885,14.291580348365,4.));
#1092=CARTESIAN_POINT('',(-2.20191774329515,13.6919175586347,3.90713104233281));
#1093=CARTESIAN_POINT('',(-2.13884486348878,13.979163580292,4.));
#1094=CARTESIAN_POINT('',(-2.07267691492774,14.2803858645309,4.));
#1095=CARTESIAN_POINT('',(-2.1741212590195,13.6977164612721,3.91076755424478));
#1096=CARTESIAN_POINT('',(-2.11209138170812,13.9796663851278,4.));
#1097=CARTESIAN_POINT('',(-2.04714221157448,14.2747724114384,4.));
#1098=CARTESIAN_POINT('',(-2.11844526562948,13.7094403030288,3.91785728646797));
#1099=CARTESIAN_POINT('',(-2.05855440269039,13.9806746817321,4.));
#1100=CARTESIAN_POINT('',(-1.99607590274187,14.2635152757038,4.));
#1101=CARTESIAN_POINT('',(-2.09056574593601,13.7153652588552,3.92131048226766));
#1102=CARTESIAN_POINT('',(-2.03176963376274,13.9811801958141,4.));
#1103=CARTESIAN_POINT('',(-1.97054429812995,14.2578715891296,4.));
#1104=CARTESIAN_POINT('',(-2.03473308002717,13.7273288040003,3.92802284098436));
#1105=CARTESIAN_POINT('',(-1.97817618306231,13.9821912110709,4.));
#1106=CARTESIAN_POINT('',(-1.91948675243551,14.2465578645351,4.));
#1107=CARTESIAN_POINT('',(-2.00677993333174,13.7333673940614,3.93128200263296));
#1108=CARTESIAN_POINT('',(-1.95136616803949,13.9826967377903,4.));
#1109=CARTESIAN_POINT('',(-1.89396081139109,14.2408878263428,4.));
#1110=CARTESIAN_POINT('',(-1.97879300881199,13.739456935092,3.9344390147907));
#1111=CARTESIAN_POINT('',(-1.92453467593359,13.9832011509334,4.));
#1112=CARTESIAN_POINT('',(-1.86843744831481,14.2352062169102,4.));
#1113=CARTESIAN_POINT('',(-1.88274753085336,13.7618990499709,3.94561109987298));
#1114=CARTESIAN_POINT('',(-1.83514719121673,13.986280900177,4.));
#1115=CARTESIAN_POINT('',(-1.78604224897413,14.2168587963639,4.));
#1116=CARTESIAN_POINT('',(-1.78814600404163,13.7825510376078,3.95453725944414));
#1117=CARTESIAN_POINT('',(-1.7463256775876,13.9887063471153,4.));
#1118=CARTESIAN_POINT('',(-1.70340103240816,14.1996033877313,4.));
#1119=CARTESIAN_POINT('',(-1.60148175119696,13.8204238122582,3.96900994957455));
#1120=CARTESIAN_POINT('',(-1.56989827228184,13.9925824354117,4.));
#1121=CARTESIAN_POINT('',(-1.53766334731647,14.1673781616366,4.));
#1122=CARTESIAN_POINT('',(-1.50941935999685,13.8376441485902,3.9745560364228));
#1123=CARTESIAN_POINT('',(-1.48221462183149,13.9940363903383,4.));
#1124=CARTESIAN_POINT('',(-1.454566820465,14.1524086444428,4.));
#1125=CARTESIAN_POINT('',(-1.32753720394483,13.8687920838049,3.98337710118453));
#1126=CARTESIAN_POINT('',(-1.30789439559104,13.9963089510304,4.));
#1127=CARTESIAN_POINT('',(-1.28800249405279,14.1248658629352,4.));
#1128=CARTESIAN_POINT('',(-1.23771676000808,13.882720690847,3.98665277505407));
#1129=CARTESIAN_POINT('',(-1.2212066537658,13.9971291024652,4.));
#1130=CARTESIAN_POINT('',(-1.20453481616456,14.1122918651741,4.));
#1131=CARTESIAN_POINT('',(-1.05987885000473,13.9074685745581,3.99170912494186));
#1132=CARTESIAN_POINT('',(-1.04862341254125,13.998367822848,4.));
#1133=CARTESIAN_POINT('',(-1.03726901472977,14.0896301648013,4.));
#1134=CARTESIAN_POINT('',(-0.971861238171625,13.918288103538,3.99348992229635));
#1135=CARTESIAN_POINT('',(-0.962694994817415,13.9987869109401,4.));
#1136=CARTESIAN_POINT('',(-0.953470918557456,14.0795422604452,4.));
#1137=CARTESIAN_POINT('',(-0.795516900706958,13.9371674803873,3.99617259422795));
#1138=CARTESIAN_POINT('',(-0.789741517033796,13.9993947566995,4.));
#1139=CARTESIAN_POINT('',(-0.783927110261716,14.0617355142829,4.));
#1140=CARTESIAN_POINT('',(-0.707219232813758,13.9451677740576,3.99705616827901));
#1141=CARTESIAN_POINT('',(-0.702707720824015,13.999578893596,4.));
#1142=CARTESIAN_POINT('',(-0.698175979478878,14.0540681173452,4.));
#1143=CARTESIAN_POINT('',(-0.531642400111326,13.9583159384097,3.99831004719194));
#1144=CARTESIAN_POINT('',(-0.529073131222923,13.9998273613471,4.));
#1145=CARTESIAN_POINT('',(-0.526488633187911,14.0413719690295,4.));
#1146=CARTESIAN_POINT('',(-0.444363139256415,13.9634640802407,3.99868040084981));
#1147=CARTESIAN_POINT('',(-0.44246108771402,13.9998917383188,4.));
#1148=CARTESIAN_POINT('',(-0.440552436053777,14.0363429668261,4.));
#1149=CARTESIAN_POINT('',(-0.237886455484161,13.9724216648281,3.99926861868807));
#1150=CARTESIAN_POINT('',(-0.237170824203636,13.9999888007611,4.));
#1151=CARTESIAN_POINT('',(-0.23644499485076,14.0275651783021,4.));
#1152=CARTESIAN_POINT('',(-0.118941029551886,13.9750132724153,3.99937789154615));
#1153=CARTESIAN_POINT('',(-0.11858112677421,14.0000006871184,4.00000000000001));
#1154=CARTESIAN_POINT('',(-0.118220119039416,14.0249957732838,4.));
#1155=CARTESIAN_POINT('',(0.0915140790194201,13.9750105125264,3.99937329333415));
#1156=CARTESIAN_POINT('',(0.0912372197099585,13.9999994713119,4.00000000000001));
#1157=CARTESIAN_POINT('',(0.0909594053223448,14.0249963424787,4.));
#1158=CARTESIAN_POINT('',(0.183025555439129,13.9734741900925,3.99930506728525));
#1159=CARTESIAN_POINT('',(0.182472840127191,13.999991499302,4.));
#1160=CARTESIAN_POINT('',(0.181915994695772,14.0265178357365,4.));
#1161=CARTESIAN_POINT('',(0.366557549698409,13.9673423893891,3.99894479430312));
#1162=CARTESIAN_POINT('',(0.365154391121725,13.9999363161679,4.));
#1163=CARTESIAN_POINT('',(0.363746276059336,14.0325470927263,4.));
#1164=CARTESIAN_POINT('',(0.458578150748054,13.9627463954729,3.9986527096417));
#1165=CARTESIAN_POINT('',(0.456605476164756,13.9998890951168,4.));
#1166=CARTESIAN_POINT('',(0.454619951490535,14.037055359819,4.));
#1167=CARTESIAN_POINT('',(0.643794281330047,13.9503997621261,3.99759062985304));
#1168=CARTESIAN_POINT('',(0.640080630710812,13.9996877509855,4.));
#1169=CARTESIAN_POINT('',(0.636350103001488,14.0490334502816,4.));
#1170=CARTESIAN_POINT('',(0.736991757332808,13.9426429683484,3.99681970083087));
#1171=CARTESIAN_POINT('',(0.732116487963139,13.9995333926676,4.));
#1172=CARTESIAN_POINT('',(0.727206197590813,14.0565090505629,4.));
#1173=CARTESIAN_POINT('',(0.924960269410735,13.9237450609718,3.99433695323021));
#1174=CARTESIAN_POINT('',(0.916818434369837,13.9989827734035,4.));
#1175=CARTESIAN_POINT('',(0.908625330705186,14.0744281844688,4.));
#1176=CARTESIAN_POINT('',(1.01973130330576,13.9126039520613,3.99262513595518));
#1177=CARTESIAN_POINT('',(1.00950648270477,13.9985863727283,4.));
#1178=CARTESIAN_POINT('',(0.999188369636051,14.0848717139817,4.));
#1179=CARTESIAN_POINT('',(1.21132156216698,13.8867133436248,3.98756159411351));
#1180=CARTESIAN_POINT('',(1.19570430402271,13.9973557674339,4.));
#1181=CARTESIAN_POINT('',(1.17993325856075,14.108674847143,4.));
#1182=CARTESIAN_POINT('',(1.30814088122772,13.8719636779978,3.98420979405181));
#1183=CARTESIAN_POINT('',(1.28925296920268,13.99652101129,4.00000000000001));
#1184=CARTESIAN_POINT('',(1.27011509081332,14.1220345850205,4.));
#1185=CARTESIAN_POINT('',(1.50432886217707,13.8386479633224,3.97489882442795));
#1186=CARTESIAN_POINT('',(1.47739407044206,13.9941267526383,3.99999999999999));
#1187=CARTESIAN_POINT('',(1.45001474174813,14.1515444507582,4.));
#1188=CARTESIAN_POINT('',(1.60369733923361,13.8200821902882,3.96893984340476));
#1189=CARTESIAN_POINT('',(1.57204954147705,13.992565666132,3.99999999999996));
#1190=CARTESIAN_POINT('',(1.53973259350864,14.1676943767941,4.));
#1191=CARTESIAN_POINT('',(1.74965921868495,13.7903032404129,3.95746962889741));
#1192=CARTESIAN_POINT('',(1.70986619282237,13.989491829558,3.99999999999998));
#1193=CARTESIAN_POINT('',(1.66917538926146,14.1929936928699,4.));
#1194=CARTESIAN_POINT('',(1.79505163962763,13.7807011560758,3.95353286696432));
#1195=CARTESIAN_POINT('',(1.75260745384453,13.9884283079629,3.99999999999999));
#1196=CARTESIAN_POINT('',(1.70911176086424,14.2010760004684,4.));
#1197=CARTESIAN_POINT('',(1.88645085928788,13.7606880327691,3.94472444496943));
#1198=CARTESIAN_POINT('',(1.83836111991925,13.9860299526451,4.00000000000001));
#1199=CARTESIAN_POINT('',(1.78886310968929,14.2177569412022,4.));
#1200=CARTESIAN_POINT('',(1.93245745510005,13.7502772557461,3.93985308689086));
#1201=CARTESIAN_POINT('',(1.88138401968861,13.9846946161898,4.00000000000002));
#1202=CARTESIAN_POINT('',(1.82867812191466,14.2263554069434,4.));
#1203=CARTESIAN_POINT('',(1.9787930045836,13.7394569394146,3.93443901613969));
#1204=CARTESIAN_POINT('',(1.92453467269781,13.9832011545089,4.));
#1205=CARTESIAN_POINT('',(1.86843744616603,14.2352062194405,4.));
#1206=CARTESIAN_POINT('',(2.05430633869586,13.7230188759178,3.92592667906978));
#1207=CARTESIAN_POINT('',(1.99697962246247,13.9818379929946,4.));
#1208=CARTESIAN_POINT('',(1.93729737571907,14.2505357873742,4.));
#1209=CARTESIAN_POINT('',(2.12956187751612,13.7069678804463,3.91666162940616));
#1210=CARTESIAN_POINT('',(2.06926583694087,13.9804690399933,4.));
#1211=CARTESIAN_POINT('',(2.00617665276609,14.2657793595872,4.));
#1212=CARTESIAN_POINT('',(2.27947316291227,13.6758254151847,3.89685242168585));
#1213=CARTESIAN_POINT('',(2.21360446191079,13.977762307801,4.));
#1214=CARTESIAN_POINT('',(2.14398439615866,14.2960367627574,4.));
#1215=CARTESIAN_POINT('',(2.35412891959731,13.6607339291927,3.88630828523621));
#1216=CARTESIAN_POINT('',(2.28568067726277,13.9764241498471,4.));
#1217=CARTESIAN_POINT('',(2.21291286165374,14.3110505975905,4.));
#1218=CARTESIAN_POINT('',(2.50276005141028,13.6316950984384,3.86416676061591));
#1219=CARTESIAN_POINT('',(2.42956099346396,13.9738246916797,4.));
#1220=CARTESIAN_POINT('',(2.35083278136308,14.3407915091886,4.));
#1221=CARTESIAN_POINT('',(2.57673541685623,13.6177477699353,3.8525693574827));
#1222=CARTESIAN_POINT('',(2.50138480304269,13.9725632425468,4.));
#1223=CARTESIAN_POINT('',(2.41982423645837,14.3555185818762,4.));
#1224=CARTESIAN_POINT('',(2.72398526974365,13.5910908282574,3.82856040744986));
#1225=CARTESIAN_POINT('',(2.64475570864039,13.9701467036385,4.));
#1226=CARTESIAN_POINT('',(2.55787837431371,14.3846406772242,4.));
#1227=CARTESIAN_POINT('',(2.79725974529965,13.5783812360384,3.81614884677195));
#1228=CARTESIAN_POINT('',(2.71631821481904,13.9689916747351,4.));
#1229=CARTESIAN_POINT('',(2.62694105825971,14.3990356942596,4.));
#1230=CARTESIAN_POINT('',(2.87017281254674,13.566337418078,3.80344990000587));
#1231=CARTESIAN_POINT('',(2.78760704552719,13.9679070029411,4.));
#1232=CARTESIAN_POINT('',(2.6960427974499,14.4132418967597,4.));
#1233=(BOUNDED_SURFACE() B_SPLINE_SURFACE(3,2,((#1029,#1030,#1031),(#1032,#1033,#1034),(#1035,
#1036,#1037),(#1038,#1039,#1040),(#1041,#1042,#1043),(#1044,#1045,#1046),(#1047,#1048,#1049),
(#1050,#1051,#1052),(#1053,#1054,#1055),(#1056,#1057,#1058),(#1059,#1060,#1061),(#1062,#1063,
#1064),(#1065,#1066,#1067),(#1068,#1069,#1070),(#1071,#1072,#1073),(#1074,#1075,#1076),(#1077,
#1078,#1079),(#1080,#1081,#1082),(#1083,#1084,#1085),(#1086,#1087,#1088),(#1089,#1090,#1091),
(#1092,#1093,#1094),(#1095,#1096,#1097),(#1098,#1099,#1100),(#1101,#1102,#1103),(#1104,#1105,
#1106),(#1107,#1108,#1109),(#1110,#1111,#1112),(#1113,#1114,#1115),(#1116,#1117,#1118),(#1119,
#1120,#1121),(#1122,#1123,#1124),(#1125,#1126,#1127),(#1128,#1129,#1130),(#1131,#1132,#1133),
(#1134,#1135,#1136),(#1137,#1138,#1139),(#1140,#1141,#1142),(#1143,#1144,#1145),(#1146,#1147,
#1148),(#1149,#1150,#1151),(#1152,#1153,#1154),(#1155,#1156,#1157),(#1158,#1159,#1160),(#1161,
#1162,#1163),(#1164,#1165,#1166),(#1167,#1168,#1169),(#1170,#1171,#1172),(#1173,#1174,#1175),
(#1176,#1177,#1178),(#1179,#1180,#1181),(#1182,#1183,#1184),(#1185,#1186,#1187),(#1188,#1189,
#1190),(#1191,#1192,#1193),(#1194,#1195,#1196),(#1197,#1198,#1199),(#1200,#1201,#1202),(#1203,
#1204,#1205),(#1206,#1207,#1208),(#1209,#1210,#1211),(#1212,#1213,#1214),(#1215,#1216,#1217),
(#1218,#1219,#1220),(#1221,#1222,#1223),(#1224,#1225,#1226),(#1227,#1228,#1229),(#1230,#1231,
#1232)),.UNSPECIFIED.,.F.,.F.,.F.) B_SPLINE_SURFACE_WITH_KNOTS((4,2,2,2,2,2,2,2,2,2,2,2,2,3,2,2,
2,2,2,2,2,2,2,2,2,2,2,2,3,2,2,2,4),(3,3),(0.,0.613817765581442,1.22767579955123,
1.84155877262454,2.45543116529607,3.06810291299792,3.68077032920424,4.29336863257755,
4.59966991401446,4.90597072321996,4.98440461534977,5.06283791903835,5.14128168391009,
5.21972596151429,5.47296240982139,5.72623209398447,5.97942410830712,6.23259556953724,
6.49083305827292,6.7490459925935,7.10368420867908,7.37654538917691,7.64945256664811,
7.92289367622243,8.19633440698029,8.46978772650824,8.74322127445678,8.86545649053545,
8.98765227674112,9.1992894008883,9.41092295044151,9.62255950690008,9.83419964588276),(0.,1.),
.UNSPECIFIED.) GEOMETRIC_REPRESENTATION_ITEM() RATIONAL_B_SPLINE_SURFACE(((1.,0.879425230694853,
1.),(1.,0.882758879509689,1.),(1.,0.886258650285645,1.),(1.,0.893615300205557,1.),(1.,
0.897472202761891,1.),(1.,0.905567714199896,1.),(1.,0.909806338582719,1.),(1.,0.918667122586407,
1.),(1.,0.923289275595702,1.),(1.,0.932866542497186,1.),(1.,0.937820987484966,1.),(1.,
0.947942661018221,1.),(1.,0.953109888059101,1.),(1.,0.963371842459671,1.),(1.,0.968466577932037,
1.),(1.,0.975661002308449,1.),(1.,0.97798453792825,1.),(1.,0.982394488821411,1.),(1.,
0.984480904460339,1.),(1.,0.986898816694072,1.),(1.,0.987381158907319,1.),(1.,0.988323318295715,
1.),(1.,0.988783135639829,1.),(1.,0.989679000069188,1.),(1.,0.990115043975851,1.),(1.,
0.990962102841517,1.),(1.,0.991373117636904,1.),(1.,0.991771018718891,1.),(1.,0.993178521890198,
1.),(1.,0.994301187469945,1.),(1.,0.996119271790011,1.),(1.,0.996814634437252,1.),(1.,
0.997920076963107,1.),(1.,0.99833024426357,1.),(1.,0.998963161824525,1.),(1.,0.999185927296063,
1.),(1.,0.99952146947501,1.),(1.,0.999631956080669,1.),(1.,0.999788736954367,1.),(1.,
0.999835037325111,1.),(1.,0.99990857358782,1.),(1.,0.999922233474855,1.),(1.,0.999921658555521,
1.),(1.,0.999913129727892,1.),(1.,0.999868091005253,1.),(1.,0.999831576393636,1.),(1.,
0.99969878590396,1.),(1.,0.999602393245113,1.),(1.,0.999291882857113,1.),(1.,0.999077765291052,
1.),(1.,0.998444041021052,1.),(1.,0.998024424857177,1.),(1.,0.996857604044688,1.),(1.,
0.996110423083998,1.),(1.,0.994669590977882,1.),(1.,0.994174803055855,1.),(1.,0.993066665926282,
1.),(1.,0.992453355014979,1.),(1.,0.991771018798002,1.),(1.,0.990698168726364,1.),(1.,
0.989528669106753,1.),(1.,0.98702313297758,1.),(1.,0.985687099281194,1.),(1.,0.982875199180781,
1.),(1.,0.981399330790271,1.),(1.,0.978336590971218,1.),(1.,0.97674971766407,1.),(1.,
0.975121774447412,1.))) REPRESENTATION_ITEM('') SURFACE());
#1234=CARTESIAN_POINT('',(-2.00000000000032,14.0000000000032,3.9832713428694));
#1235=CARTESIAN_POINT('',(-1.99812908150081,13.9780640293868,3.98053680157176));
#1236=CARTESIAN_POINT('',(-1.99630390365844,13.9561661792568,3.97746580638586));
#1237=CARTESIAN_POINT('',(-1.99271671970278,13.9124902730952,3.97065696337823));
#1238=CARTESIAN_POINT('',(-1.99095465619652,13.8907121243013,3.96691974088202));
#1239=CARTESIAN_POINT('',(-1.98746201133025,13.8472781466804,3.95877938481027));
#1240=CARTESIAN_POINT('',(-1.98573142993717,13.8256223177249,3.95437625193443));
#1241=CARTESIAN_POINT('',(-1.98226978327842,13.7824352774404,3.94490492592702));
#1242=CARTESIAN_POINT('',(-1.98053871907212,13.7609042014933,3.93983611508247));
#1243=CARTESIAN_POINT('',(-1.97879300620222,13.7394569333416,3.93443901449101));
#1244=B_SPLINE_CURVE_WITH_KNOTS('',3,(#1234,#1235,#1236,#1237,#1238,#1239,#1240,#1241,#1242,
#1243),.UNSPECIFIED.,.F.,.F.,(4,2,2,2,4),(0.,0.0665516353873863,0.133041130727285,
0.199530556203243,0.266082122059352),.UNSPECIFIED.);
#1245=CARTESIAN_POINT('',(-1.97879300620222,13.7394569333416,3.93443901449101));
#1246=VERTEX_POINT('',#1245);
#1247=EDGE_CURVE('E591',#1027,#1246,#1244,.T.);
#1248=DIRECTION('',(0.0786899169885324,-0.966761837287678,-0.243268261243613));
#1249=VECTOR('',#1248,1.);
#1250=CARTESIAN_POINT('',(-1.91860465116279,13.,3.7483679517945));
#1251=LINE('',#1250,#1249);
#1252=EDGE_CURVE('E617',#1246,#467,#1251,.T.);
#1253=ORIENTED_EDGE('',*,*,#999,.T.);
#1254=ORIENTED_EDGE('',*,*,#1013,.T.);
#1255=ORIENTED_EDGE('',*,*,#1020,.T.);
#1256=ORIENTED_EDGE('',*,*,#1028,.T.);
#1257=ORIENTED_EDGE('',*,*,#1247,.T.);
#1258=ORIENTED_EDGE('',*,*,#1252,.T.);
#1259=ORIENTED_EDGE('',*,*,#468,.T.);
#1260=EDGE_LOOP('',(#1253,#1254,#1255,#1256,#1257,#1258,#1259));
#1261=FACE_BOUND('',#1260,.T.);
#1262=ADVANCED_FACE('F563',(#1261),#992,.T.);
#1263=CARTESIAN_POINT('',(-2.,14.,4.));
#1264=CARTESIAN_POINT('',(-1.83720930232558,12.,3.496735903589));
#1265=CARTESIAN_POINT('',(-1.66666666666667,14.,4.));
#1266=CARTESIAN_POINT('',(-1.56614450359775,12.,3.63915522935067));
#1267=CARTESIAN_POINT('',(-1.33333333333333,14.,4.));
#1268=CARTESIAN_POINT('',(-1.2702893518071,12.,3.75383083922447));
#1269=CARTESIAN_POINT('',(-0.666666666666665,14.,4.));
#1270=CARTESIAN_POINT('',(-0.649532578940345,12.,3.90934629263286));
#1271=CARTESIAN_POINT('',(-0.333333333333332,14.,4.));
#1272=CARTESIAN_POINT('',(-0.324839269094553,12.,3.95));
#1273=CARTESIAN_POINT('',(0.333333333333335,14.,4.));
#1274=CARTESIAN_POINT('',(0.324839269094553,12.,3.95));
#1275=CARTESIAN_POINT('',(0.666666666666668,14.,4.));
#1276=CARTESIAN_POINT('',(0.649532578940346,12.,3.90934629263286));
#1277=CARTESIAN_POINT('',(1.33333333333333,14.,4.));
#1278=CARTESIAN_POINT('',(1.2702893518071,12.,3.75383083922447));
#1279=CARTESIAN_POINT('',(1.66666666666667,14.,4.));
#1280=CARTESIAN_POINT('',(1.56614450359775,12.,3.63915522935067));
#1281=CARTESIAN_POINT('',(2.,14.,4.));
#1282=CARTESIAN_POINT('',(1.83720930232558,12.,3.496735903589));
#1283=B_SPLINE_SURFACE_WITH_KNOTS('',3,1,((#1263,#1264),(#1265,#1266),(#1267,#1268),(#1269,
#1270),(#1271,#1272),(#1273,#1274),(#1275,#1276),(#1277,#1278),(#1279,#1280),(#1281,#1282)),
.UNSPECIFIED.,.F.,.F.,.F.,(4,2,2,2,4),(2,2),(0.,0.25,0.5,0.75,1.),(0.,1.),.UNSPECIFIED.);
#1284=CARTESIAN_POINT('',(-7.17857757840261,13.3699722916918,3.09355494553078));
#1285=CARTESIAN_POINT('',(-6.97907195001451,13.366697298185,3.11701178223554));
#1286=CARTESIAN_POINT('',(-6.77980571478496,13.3638828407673,3.14176437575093));
#1287=CARTESIAN_POINT('',(-6.38150886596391,13.3599759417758,3.19413818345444));
#1288=CARTESIAN_POINT('',(-6.18247826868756,13.3588836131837,3.22175958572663));
#1289=CARTESIAN_POINT('',(-5.78442756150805,13.3592225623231,3.28014629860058));
#1290=CARTESIAN_POINT('',(-5.58540745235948,13.3606539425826,3.31091173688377));
#1291=CARTESIAN_POINT('',(-5.18689478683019,13.3672669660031,3.37571865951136));
#1292=CARTESIAN_POINT('',(-4.98740223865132,13.3724485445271,3.40976008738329));
#1293=CARTESIAN_POINT('',(-4.58749312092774,13.388213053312,3.48086875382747));
#1294=CARTESIAN_POINT('',(-4.38707912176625,13.3987853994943,3.51792994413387));
#1295=CARTESIAN_POINT('',(-3.98363975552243,13.4274478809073,3.59427913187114));
#1296=CARTESIAN_POINT('',(-3.78061440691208,13.4455379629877,3.63356711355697));
#1297=CARTESIAN_POINT('',(-3.37020604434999,13.4915720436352,3.71223733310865));
#1298=CARTESIAN_POINT('',(-3.16282352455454,13.5195149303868,3.75161955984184));
#1299=CARTESIAN_POINT('',(-2.84736617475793,13.569708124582,3.80763379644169));
#1300=CARTESIAN_POINT('',(-2.74148275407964,13.5878190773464,3.82579541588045));
#1301=CARTESIAN_POINT('',(-2.52822876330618,13.626648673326,3.86037644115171));
#1302=CARTESIAN_POINT('',(-2.42085819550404,13.6473673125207,3.87679584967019));
#1303=CARTESIAN_POINT('',(-2.28513978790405,13.6747910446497,3.89587610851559));
#1304=CARTESIAN_POINT('',(-2.25742700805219,13.6804548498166,3.89968532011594));
#1305=CARTESIAN_POINT('',(-2.20191774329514,13.6919175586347,3.90713104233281));
#1306=CARTESIAN_POINT('',(-2.1741212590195,13.6977164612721,3.91076755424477));
#1307=CARTESIAN_POINT('',(-2.11844526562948,13.7094403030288,3.91785728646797));
#1308=CARTESIAN_POINT('',(-2.09056574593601,13.7153652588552,3.92131048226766));
#1309=CARTESIAN_POINT('',(-2.03473308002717,13.7273288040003,3.92802284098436));
#1310=CARTESIAN_POINT('',(-2.00677993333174,13.7333673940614,3.93128200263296));
#1311=CARTESIAN_POINT('',(-1.97879300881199,13.739456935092,3.9344390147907));
#1312=CARTESIAN_POINT('',(-1.88274753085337,13.7618990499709,3.94561109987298));
#1313=CARTESIAN_POINT('',(-1.78814600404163,13.7825510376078,3.95453725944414));
#1314=CARTESIAN_POINT('',(-1.60148175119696,13.8204238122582,3.96900994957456));
#1315=CARTESIAN_POINT('',(-1.50941935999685,13.8376441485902,3.9745560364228));
#1316=CARTESIAN_POINT('',(-1.32753720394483,13.8687920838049,3.98337710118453));
#1317=CARTESIAN_POINT('',(-1.23771676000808,13.882720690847,3.98665277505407));
#1318=CARTESIAN_POINT('',(-1.05987885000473,13.9074685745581,3.99170912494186));
#1319=CARTESIAN_POINT('',(-0.971861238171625,13.918288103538,3.99348992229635));
#1320=CARTESIAN_POINT('',(-0.795516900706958,13.9371674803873,3.99617259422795));
#1321=CARTESIAN_POINT('',(-0.707219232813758,13.9451677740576,3.99705616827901));
#1322=CARTESIAN_POINT('',(-0.531642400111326,13.9583159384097,3.99831004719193));
#1323=CARTESIAN_POINT('',(-0.444363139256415,13.9634640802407,3.99868040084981));
#1324=CARTESIAN_POINT('',(-0.237886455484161,13.9724216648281,3.99926861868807));
#1325=CARTESIAN_POINT('',(-0.118941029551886,13.9750132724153,3.99937789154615));
#1326=CARTESIAN_POINT('',(0.0915140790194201,13.9750105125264,3.99937329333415));
#1327=CARTESIAN_POINT('',(0.183025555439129,13.9734741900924,3.99930506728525));
#1328=CARTESIAN_POINT('',(0.366557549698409,13.9673423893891,3.99894479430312));
#1329=CARTESIAN_POINT('',(0.458578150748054,13.9627463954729,3.9986527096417));
#1330=CARTESIAN_POINT('',(0.643794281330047,13.9503997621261,3.99759062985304));
#1331=CARTESIAN_POINT('',(0.736991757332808,13.9426429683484,3.99681970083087));
#1332=CARTESIAN_POINT('',(0.924960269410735,13.9237450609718,3.99433695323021));
#1333=CARTESIAN_POINT('',(1.01973130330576,13.9126039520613,3.99262513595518));
#1334=CARTESIAN_POINT('',(1.21132156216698,13.8867133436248,3.98756159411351));
#1335=CARTESIAN_POINT('',(1.30814088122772,13.8719636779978,3.98420979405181));
#1336=CARTESIAN_POINT('',(1.50432886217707,13.8386479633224,3.97489882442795));
#1337=CARTESIAN_POINT('',(1.60369733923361,13.8200821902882,3.96893984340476));
#1338=CARTESIAN_POINT('',(1.74965921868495,13.7903032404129,3.95746962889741));
#1339=CARTESIAN_POINT('',(1.79505163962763,13.7807011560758,3.95353286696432));
#1340=CARTESIAN_POINT('',(1.88645085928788,13.7606880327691,3.94472444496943));
#1341=CARTESIAN_POINT('',(1.93245745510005,13.7502772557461,3.93985308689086));
#1342=CARTESIAN_POINT('',(1.9787930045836,13.7394569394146,3.93443901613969));
#1343=CARTESIAN_POINT('',(2.05430633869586,13.7230188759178,3.92592667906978));
#1344=CARTESIAN_POINT('',(2.12956187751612,13.7069678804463,3.91666162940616));
#1345=CARTESIAN_POINT('',(2.27947316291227,13.6758254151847,3.89685242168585));
#1346=CARTESIAN_POINT('',(2.35412891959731,13.6607339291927,3.88630828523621));
#1347=CARTESIAN_POINT('',(2.50276005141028,13.6316950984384,3.86416676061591));
#1348=CARTESIAN_POINT('',(2.57673541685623,13.6177477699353,3.8525693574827));
#1349=CARTESIAN_POINT('',(2.72398526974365,13.5910908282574,3.82856040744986));
#1350=CARTESIAN_POINT('',(2.79725974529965,13.5783812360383,3.81614884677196));
#1351=CARTESIAN_POINT('',(2.87017281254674,13.566337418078,3.80344990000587));
#1352=B_SPLINE_CURVE_WITH_KNOTS('',3,(#1284,#1285,#1286,#1287,#1288,#1289,#1290,#1291,#1292,
#1293,#1294,#1295,#1296,#1297,#1298,#1299,#1300,#1301,#1302,#1303,#1304,#1305,#1306,#1307,#1308,
#1309,#1310,#1311,#1312,#1313,#1314,#1315,#1316,#1317,#1318,#1319,#1320,#1321,#1322,#1323,#1324,
#1325,#1326,#1327,#1328,#1329,#1330,#1331,#1332,#1333,#1334,#1335,#1336,#1337,#1338,#1339,#1340,
#1341,#1342,#1343,#1344,#1345,#1346,#1347,#1348,#1349,#1350,#1351),.UNSPECIFIED.,.F.,.F.,(4,2,2,
2,2,2,2,2,2,2,2,2,2,3,2,2,2,2,2,2,2,2,2,2,2,2,2,2,3,2,2,2,4),(0.,0.613817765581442,
1.22767579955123,1.84155877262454,2.45543116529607,3.06810291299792,3.68077032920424,
4.29336863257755,4.59966991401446,4.90597072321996,4.98440461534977,5.06283791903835,
5.14128168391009,5.21972596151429,5.47296240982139,5.72623209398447,5.97942410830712,
6.23259556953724,6.49083305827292,6.7490459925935,7.10368420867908,7.37654538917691,
7.64945256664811,7.92289367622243,8.19633440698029,8.46978772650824,8.74322127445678,
8.86545649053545,8.98765227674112,9.1992894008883,9.41092295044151,9.62255950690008,
9.83419964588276),.UNSPECIFIED.);
#1353=CARTESIAN_POINT('',(1.97879300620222,13.7394569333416,3.93443901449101));
#1354=VERTEX_POINT('',#1353);
#1355=EDGE_CURVE('E515',#1246,#1354,#1352,.T.);
#1356=DIRECTION('',(-0.078689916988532,-0.966761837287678,-0.243268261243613));
#1357=VECTOR('',#1356,1.);
#1358=CARTESIAN_POINT('',(1.91860465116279,13.,3.7483679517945));
#1359=LINE('',#1358,#1357);
#1360=EDGE_CURVE('E420',#1354,#636,#1359,.T.);
#1361=ORIENTED_EDGE('',*,*,#1252,.F.);
#1362=ORIENTED_EDGE('',*,*,#1355,.T.);
#1363=ORIENTED_EDGE('',*,*,#1360,.T.);
#1364=ORIENTED_EDGE('',*,*,#637,.T.);
#1365=EDGE_LOOP('',(#1361,#1362,#1363,#1364));
#1366=FACE_BOUND('',#1365,.T.);
#1367=ADVANCED_FACE('F493',(#1366),#1283,.T.);
#1368=CARTESIAN_POINT('',(2.,14.,4.35));
#1369=CARTESIAN_POINT('',(2.,12.,3.80657326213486));
#1370=CARTESIAN_POINT('',(1.66666666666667,14.,4.35));
#1371=CARTESIAN_POINT('',(1.7049168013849,12.,3.96161202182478));
#1372=CARTESIAN_POINT('',(1.33333333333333,14.,4.35));
#1373=CARTESIAN_POINT('',(1.38284663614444,12.,4.0864487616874));
#1374=CARTESIAN_POINT('',(0.666666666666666,14.,4.35));
#1375=CARTESIAN_POINT('',(0.707086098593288,12.,4.2557440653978));
#1376=CARTESIAN_POINT('',(0.333333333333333,14.,4.35));
#1377=CARTESIAN_POINT('',(0.353622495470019,12.,4.3));
#1378=CARTESIAN_POINT('',(-0.333333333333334,14.,4.35));
#1379=CARTESIAN_POINT('',(-0.35362249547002,12.,4.3));
#1380=CARTESIAN_POINT('',(-0.666666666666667,14.,4.35));
#1381=CARTESIAN_POINT('',(-0.707086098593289,12.,4.2557440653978));
#1382=CARTESIAN_POINT('',(-1.33333333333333,14.,4.35));
#1383=CARTESIAN_POINT('',(-1.38284663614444,12.,4.0864487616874));
#1384=CARTESIAN_POINT('',(-1.66666666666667,14.,4.35));
#1385=CARTESIAN_POINT('',(-1.7049168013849,12.,3.96161202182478));
#1386=CARTESIAN_POINT('',(-2.,14.,4.35));
#1387=CARTESIAN_POINT('',(-2.,12.,3.80657326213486));
#1388=B_SPLINE_SURFACE_WITH_KNOTS('',3,1,((#1368,#1369),(#1370,#1371),(#1372,#1373),(#1374,
#1375),(#1376,#1377),(#1378,#1379),(#1380,#1381),(#1382,#1383),(#1384,#1385),(#1386,#1387)),
.UNSPECIFIED.,.F.,.F.,.F.,(4,2,2,2,4),(2,2),(0.,0.25,0.5,0.75,1.),(0.,1.),.UNSPECIFIED.);
#1389=DIRECTION('',(0.,-0.965011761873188,-0.26220659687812));
#1390=VECTOR('',#1389,1.);
#1391=CARTESIAN_POINT('',(2.,13.,4.07828663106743));
#1392=LINE('',#1391,#1390);
#1393=CARTESIAN_POINT('',(2.,13.7289397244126,4.27634929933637));
#1394=VERTEX_POINT('',#1393);
#1395=EDGE_CURVE('E417',#1394,#874,#1392,.T.);
#1396=CARTESIAN_POINT('',(3.69271229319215,13.4636491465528,3.98642597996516));
#1397=CARTESIAN_POINT('',(3.57308567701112,13.474977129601,4.00961729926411));
#1398=CARTESIAN_POINT('',(3.4527952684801,13.4878586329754,4.03300707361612));
#1399=CARTESIAN_POINT('',(3.21052336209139,13.5170837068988,4.07940973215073));
#1400=CARTESIAN_POINT('',(3.08854191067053,13.5334271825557,4.10242262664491));
#1401=CARTESIAN_POINT('',(2.84254436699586,13.5699278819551,4.14729425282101));
#1402=CARTESIAN_POINT('',(2.71852871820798,13.5900842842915,4.16915323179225));
#1403=CARTESIAN_POINT('',(2.46820849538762,13.6342865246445,4.21063104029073));
#1404=CARTESIAN_POINT('',(2.34190392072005,13.6583323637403,4.23024986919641));
#1405=CARTESIAN_POINT('',(2.17890874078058,13.6913414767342,4.25312173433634));
#1406=CARTESIAN_POINT('',(2.14324163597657,13.6986841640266,4.25797881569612));
#1407=CARTESIAN_POINT('',(2.07174220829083,13.7136250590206,4.26739464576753));
#1408=CARTESIAN_POINT('',(2.03590988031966,13.7212232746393,4.27195338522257));
#1409=CARTESIAN_POINT('',(2.00000000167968,13.7289397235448,4.276349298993));
#1410=CARTESIAN_POINT('',(1.90167102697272,13.7513374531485,4.28869521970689));
#1411=CARTESIAN_POINT('',(1.80464823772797,13.7723292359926,4.29867394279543));
#1412=CARTESIAN_POINT('',(1.61307967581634,13.8113201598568,4.31497721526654));
#1413=CARTESIAN_POINT('',(1.5185344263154,13.8293186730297,4.32130099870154));
#1414=CARTESIAN_POINT('',(1.33185249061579,13.8621282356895,4.33136895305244));
#1415=CARTESIAN_POINT('',(1.23971514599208,13.8769401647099,4.33511383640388));
#1416=CARTESIAN_POINT('',(1.05747616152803,13.9033699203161,4.34088069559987));
#1417=CARTESIAN_POINT('',(0.967374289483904,13.9149881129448,4.34290286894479));
#1418=CARTESIAN_POINT('',(0.791012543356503,13.9348320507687,4.34586056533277));
#1419=CARTESIAN_POINT('',(0.70471251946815,13.943133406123,4.3468213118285));
#1420=CARTESIAN_POINT('',(0.533226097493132,13.9568710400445,4.34818815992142));
#1421=CARTESIAN_POINT('',(0.44803957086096,13.9623076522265,4.34859432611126));
#1422=CARTESIAN_POINT('',(0.241676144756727,13.9721148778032,4.34925858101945));
#1423=CARTESIAN_POINT('',(0.120836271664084,13.9750123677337,4.34937707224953));
#1424=CARTESIAN_POINT('',(-0.116644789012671,13.9750110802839,4.34937357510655));
#1425=CARTESIAN_POINT('',(-0.233286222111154,13.9723098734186,4.34925978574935));
#1426=CARTESIAN_POINT('',(-0.477021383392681,13.9611282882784,4.34852600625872));
#1427=CARTESIAN_POINT('',(-0.604213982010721,13.9522089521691,4.34786680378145));
#1428=CARTESIAN_POINT('',(-0.739198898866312,13.9394622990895,4.34634505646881));
#1429=CARTESIAN_POINT('',(-0.745559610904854,13.9388541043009,4.34627145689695));
#1430=CARTESIAN_POINT('',(-0.777381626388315,13.9357735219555,4.34589286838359));
#1431=CARTESIAN_POINT('',(-0.802897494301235,13.9331823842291,4.34555611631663));
#1432=CARTESIAN_POINT('',(-0.930824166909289,13.9195775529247,4.34367552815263));
#1433=CARTESIAN_POINT('',(-1.03422629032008,13.9066211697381,4.34154174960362));
#1434=CARTESIAN_POINT('',(-1.27716801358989,13.8716557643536,4.33402001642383));
#1435=CARTESIAN_POINT('',(-1.41770410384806,13.848077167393,4.32781054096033));
#1436=CARTESIAN_POINT('',(-1.63281160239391,13.807294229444,4.31322231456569));
#1437=CARTESIAN_POINT('',(-1.70523985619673,13.7927954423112,4.30747961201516));
#1438=CARTESIAN_POINT('',(-1.85153549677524,13.7621073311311,4.29373451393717));
#1439=CARTESIAN_POINT('',(-1.9254027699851,13.7459181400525,4.28573229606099));
#1440=CARTESIAN_POINT('',(-1.99999998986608,13.7289397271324,4.27634930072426));
#1441=CARTESIAN_POINT('',(-2.03624814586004,13.7211499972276,4.2719120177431));
#1442=CARTESIAN_POINT('',(-2.07241656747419,13.7134817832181,4.26730885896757));
#1443=CARTESIAN_POINT('',(-2.14458602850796,13.6984056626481,4.25779866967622));
#1444=CARTESIAN_POINT('',(-2.18058706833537,13.6909977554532,4.25289163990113));
#1445=CARTESIAN_POINT('',(-2.25240612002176,13.6764610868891,4.24280267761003));
#1446=CARTESIAN_POINT('',(-2.28822417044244,13.6693322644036,4.2376208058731));
#1447=CARTESIAN_POINT('',(-2.35968251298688,13.6553620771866,4.22700835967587));
#1448=CARTESIAN_POINT('',(-2.39532280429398,13.6485207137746,4.22157778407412));
#1449=CARTESIAN_POINT('',(-2.63901106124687,13.6026667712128,4.18360528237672));
#1450=CARTESIAN_POINT('',(-2.84397861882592,13.5687290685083,4.14744810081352));
#1451=CARTESIAN_POINT('',(-3.2484456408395,13.5111860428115,4.07262212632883));
#1452=CARTESIAN_POINT('',(-3.44794503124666,13.487580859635,4.03395329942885));
#1453=CARTESIAN_POINT('',(-3.8432984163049,13.448802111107,3.95718756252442));
#1454=CARTESIAN_POINT('',(-4.03915166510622,13.43363025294,3.91909076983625));
#1455=CARTESIAN_POINT('',(-4.42871715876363,13.409659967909,3.84505695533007));
#1456=CARTESIAN_POINT('',(-4.62242939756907,13.4008615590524,3.80911993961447));
#1457=CARTESIAN_POINT('',(-5.00930561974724,13.3878554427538,3.73999063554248));
#1458=CARTESIAN_POINT('',(-5.20246696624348,13.3836594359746,3.70680554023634));
#1459=CARTESIAN_POINT('',(-5.58845248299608,13.3785305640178,3.6434523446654));
#1460=CARTESIAN_POINT('',(-5.781276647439,13.3775977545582,3.61328429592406));
#1461=CARTESIAN_POINT('',(-6.16694081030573,13.3779704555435,3.55588998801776));
#1462=CARTESIAN_POINT('',(-6.3597807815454,13.3792752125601,3.52866274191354));
#1463=CARTESIAN_POINT('',(-6.74572756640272,13.3834343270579,3.47692027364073));
#1464=CARTESIAN_POINT('',(-6.93883436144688,13.3862885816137,3.45240487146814));
#1465=CARTESIAN_POINT('',(-7.13218042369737,13.389574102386,3.42913454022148));
#1466=B_SPLINE_CURVE_WITH_KNOTS('',3,(#1396,#1397,#1398,#1399,#1400,#1401,#1402,#1403,#1404,
#1405,#1406,#1407,#1408,#1409,#1410,#1411,#1412,#1413,#1414,#1415,#1416,#1417,#1418,#1419,#1420,
#1421,#1422,#1423,#1424,#1425,#1426,#1427,#1428,#1429,#1430,#1431,#1432,#1433,#1434,#1435,#1436,
#1437,#1438,#1439,#1440,#1441,#1442,#1443,#1444,#1445,#1446,#1447,#1448,#1449,#1450,#1451,#1452,
#1453,#1454,#1455,#1456,#1457,#1458,#1459,#1460,#1461,#1462,#1463,#1464,#1465),.UNSPECIFIED.,
.F.,.F.,(4,2,2,2,2,2,3,2,2,2,2,2,2,2,2,2,2,2,2,2,2,3,2,2,2,2,2,2,2,2,2,2,2,4),(0.,
0.360163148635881,0.720316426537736,1.08039220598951,1.44046808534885,1.5410192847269,
1.64157360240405,1.89943751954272,2.15735545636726,2.4152021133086,2.67301920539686,
2.92456823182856,3.17608795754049,3.53617731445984,3.88377614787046,4.25878733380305,
4.27732162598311,4.3514595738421,4.64806066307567,5.03936749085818,5.23506565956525,
5.43074844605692,5.53224867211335,5.63374865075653,5.73522627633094,5.83670436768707,
6.43088282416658,7.02506932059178,7.61937605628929,8.21368447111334,8.80950031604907,
9.40532633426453,10.0009517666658,10.5965376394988),.UNSPECIFIED.);
#1467=EDGE_CURVE('E424',#1394,#998,#1466,.T.);
#1468=ORIENTED_EDGE('',*,*,#1395,.F.);
#1469=ORIENTED_EDGE('',*,*,#1467,.T.);
#1470=ORIENTED_EDGE('',*,*,#999,.F.);
#1471=ORIENTED_EDGE('',*,*,#882,.T.);
#1472=EDGE_LOOP('',(#1468,#1469,#1470,#1471));
#1473=FACE_BOUND('',#1472,.T.);
#1474=ADVANCED_FACE('F436',(#1473),#1388,.T.);
#1475=CARTESIAN_POINT('',(2.,14.,3.98107097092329));
#1476=CARTESIAN_POINT('',(1.82840510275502,12.,3.4799789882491));
#1477=CARTESIAN_POINT('',(2.,14.,3.9873806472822));
#1478=CARTESIAN_POINT('',(1.83133983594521,12.,3.48556462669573));
#1479=CARTESIAN_POINT('',(2.,14.,3.9936903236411));
#1480=CARTESIAN_POINT('',(1.83427456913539,12.,3.49115026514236));
#1481=CARTESIAN_POINT('',(2.,14.,4.));
#1482=CARTESIAN_POINT('',(1.83720930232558,12.,3.496735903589));
#1483=CARTESIAN_POINT('',(2.,14.,4.05833333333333));
#1484=CARTESIAN_POINT('',(1.86434108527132,12.,3.54837546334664));
#1485=CARTESIAN_POINT('',(2.,14.,4.11666666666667));
#1486=CARTESIAN_POINT('',(1.89147286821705,12.,3.60001502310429));
#1487=CARTESIAN_POINT('',(2.,14.,4.23333333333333));
#1488=CARTESIAN_POINT('',(1.94573643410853,12.,3.70329414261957));
#1489=CARTESIAN_POINT('',(2.,14.,4.29166666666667));
#1490=CARTESIAN_POINT('',(1.97286821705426,12.,3.75493370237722));
#1491=CARTESIAN_POINT('',(2.,14.,4.35));
#1492=CARTESIAN_POINT('',(2.,12.,3.80657326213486));
#1493=B_SPLINE_SURFACE_WITH_KNOTS('',3,1,((#1475,#1476),(#1477,#1478),(#1479,#1480),(#1481,
#1482),(#1483,#1484),(#1485,#1486),(#1487,#1488),(#1489,#1490),(#1491,#1492)),.UNSPECIFIED.,.F.,
.F.,.F.,(4,3,2,4),(2,2),(-0.054082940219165,0.,0.5,1.),(0.,1.),.UNSPECIFIED.);
#1494=DIRECTION('',(0.,0.,1.));
#1495=VECTOR('',#1494,1.);
#1496=CARTESIAN_POINT('',(2.,14.,4.));
#1497=LINE('',#1496,#1495);
#1498=CARTESIAN_POINT('',(2.,14.,4.));
#1499=VERTEX_POINT('',#1498);
#1500=CARTESIAN_POINT('',(2.,14.,4.33115825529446));
#1501=VERTEX_POINT('',#1500);
#1502=EDGE_CURVE('E624',#1499,#1501,#1497,.T.);
#1503=CARTESIAN_POINT('',(2.,14.,4.33115825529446));
#1504=CARTESIAN_POINT('',(1.99989969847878,13.9771311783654,4.32808368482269));
#1505=CARTESIAN_POINT('',(1.99984949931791,13.9543129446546,4.32463210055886));
#1506=CARTESIAN_POINT('',(1.99981182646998,13.9088271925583,4.31698319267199));
#1507=CARTESIAN_POINT('',(1.9998242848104,13.8861595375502,4.31278668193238));
#1508=CARTESIAN_POINT('',(1.99987439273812,13.8409748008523,4.30364952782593));
#1509=CARTESIAN_POINT('',(1.99991204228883,13.8184577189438,4.29870888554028));
#1510=CARTESIAN_POINT('',(1.9999748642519,13.7735737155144,4.28808448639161));
#1511=CARTESIAN_POINT('',(2.0000000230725,13.7512069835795,4.28239992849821));
#1512=CARTESIAN_POINT('',(2.,13.7289397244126,4.27634929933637));
#1513=B_SPLINE_CURVE_WITH_KNOTS('',3,(#1503,#1504,#1505,#1506,#1507,#1508,#1509,#1510,#1511,
#1512),.UNSPECIFIED.,.F.,.F.,(4,2,2,2,4),(0.,0.0692210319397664,0.13836698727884,
0.207512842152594,0.276733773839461),.UNSPECIFIED.);
#1514=EDGE_CURVE('E634',#1501,#1394,#1513,.T.);
#1515=CARTESIAN_POINT('',(1.97879300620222,13.7394569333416,3.93443901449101));
#1516=CARTESIAN_POINT('',(1.98053871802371,13.7609042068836,3.93983608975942));
#1517=CARTESIAN_POINT('',(1.98226978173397,13.7824352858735,3.94490488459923));
#1518=CARTESIAN_POINT('',(1.98573142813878,13.8256223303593,3.95437618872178));
#1519=CARTESIAN_POINT('',(1.98746200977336,13.8472781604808,3.95877931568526));
#1520=CARTESIAN_POINT('',(1.99095465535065,13.8907121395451,3.96691966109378));
#1521=CARTESIAN_POINT('',(1.99271671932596,13.9124902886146,3.97065687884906));
#1522=CARTESIAN_POINT('',(1.99630390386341,13.9561661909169,3.9774657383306));
#1523=CARTESIAN_POINT('',(1.99812908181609,13.9780640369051,3.980536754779));
#1524=CARTESIAN_POINT('',(2.00000000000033,14.0000000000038,3.98327134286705));
#1525=B_SPLINE_CURVE_WITH_KNOTS('',3,(#1515,#1516,#1517,#1518,#1519,#1520,#1521,#1522,#1523,
#1524),.UNSPECIFIED.,.F.,.F.,(4,2,2,2,4),(0.,0.066551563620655,0.133040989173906,
0.199530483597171,0.26608211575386),.UNSPECIFIED.);
#1526=CARTESIAN_POINT('',(2.00000000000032,14.0000000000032,3.9832713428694));
#1527=VERTEX_POINT('',#1526);
#1528=EDGE_CURVE('E91',#1354,#1527,#1525,.T.);
#1529=CARTESIAN_POINT('',(2.,14.,4.));
#1530=CARTESIAN_POINT('',(2.,14.,3.99442378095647));
#1531=CARTESIAN_POINT('',(2.,14.,3.98884756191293));
#1532=CARTESIAN_POINT('',(2.,14.,3.9832713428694));
#1533=B_SPLINE_CURVE_WITH_KNOTS('',3,(#1529,#1530,#1531,#1532),.UNSPECIFIED.,.F.,.F.,(4,4),(0.,
0.0167286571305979),.UNSPECIFIED.);
#1534=EDGE_CURVE('E76',#1499,#1527,#1533,.T.);
#1535=ORIENTED_EDGE('',*,*,#1502,.T.);
#1536=ORIENTED_EDGE('',*,*,#1514,.T.);
#1537=ORIENTED_EDGE('',*,*,#1395,.T.);
#1538=ORIENTED_EDGE('',*,*,#949,.T.);
#1539=ORIENTED_EDGE('',*,*,#1360,.F.);
#1540=ORIENTED_EDGE('',*,*,#1528,.T.);
#1541=ORIENTED_EDGE('',*,*,#1534,.F.);
#1542=EDGE_LOOP('',(#1535,#1536,#1537,#1538,#1539,#1540,#1541));
#1543=FACE_BOUND('',#1542,.T.);
#1544=ADVANCED_FACE('F526',(#1543),#1493,.T.);
#1545=CARTESIAN_POINT('',(0.,22.,-5.5));
#1546=DIRECTION('',(0.,0.,1.));
#1547=DIRECTION('',(1.,0.,0.));
#1548=AXIS2_PLACEMENT_3D('',#1545,#1546,#1547);
#1549=CYLINDRICAL_SURFACE('',#1548,2.);
#1550=CARTESIAN_POINT('',(0.,22.,-4.5));
#1551=DIRECTION('',(0.,0.,1.));
#1552=DIRECTION('',(1.,0.,0.));
#1553=AXIS2_PLACEMENT_3D('',#1550,#1551,#1552);
#1554=CIRCLE('',#1553,2.);
#1555=CARTESIAN_POINT('',(2.,22.,-4.5));
#1556=VERTEX_POINT('',#1555);
#1557=EDGE_CURVE('E405',#1556,#1556,#1554,.T.);
#1558=ORIENTED_EDGE('',*,*,#1557,.T.);
#1559=EDGE_LOOP('',(#1558));
#1560=FACE_BOUND('',#1559,.T.);
#1561=CARTESIAN_POINT('',(0.,22.,4.));
#1562=DIRECTION('',(0.,0.,1.));
#1563=DIRECTION('',(1.,0.,0.));
#1564=AXIS2_PLACEMENT_3D('',#1561,#1562,#1563);
#1565=CIRCLE('',#1564,2.);
#1566=CARTESIAN_POINT('',(2.,22.,4.));
#1567=VERTEX_POINT('',#1566);
#1568=EDGE_CURVE('E393',#1567,#1567,#1565,.T.);
#1569=ORIENTED_EDGE('',*,*,#1568,.F.);
#1570=EDGE_LOOP('',(#1569));
#1571=FACE_BOUND('',#1570,.T.);
#1572=ADVANCED_FACE('F532',(#1560,#1571),#1549,.T.);
#1573=CARTESIAN_POINT('',(0.,22.,-5.5));
#1574=DIRECTION('',(0.,0.,1.));
#1575=DIRECTION('',(1.,0.,0.));
#1576=AXIS2_PLACEMENT_3D('',#1573,#1574,#1575);
#1577=PLANE('',#1576);
#1578=CARTESIAN_POINT('',(0.,22.,-5.5));
#1579=DIRECTION('',(0.,0.,1.));
#1580=DIRECTION('',(1.,0.,0.));
#1581=AXIS2_PLACEMENT_3D('',#1578,#1579,#1580);
#1582=CIRCLE('',#1581,1.42264973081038);
#1583=CARTESIAN_POINT('',(1.42264973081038,22.,-5.5));
#1584=VERTEX_POINT('',#1583);
#1585=EDGE_CURVE('E408',#1584,#1584,#1582,.F.);
#1586=ORIENTED_EDGE('',*,*,#1585,.T.);
#1587=EDGE_LOOP('',(#1586));
#1588=FACE_BOUND('',#1587,.T.);
#1589=ADVANCED_FACE('F1116',(#1588),#1577,.F.);
#1590=CARTESIAN_POINT('',(0.,22.,-4.5));
#1591=DIRECTION('',(0.,0.,1.));
#1592=DIRECTION('',(1.,0.,0.));
#1593=AXIS2_PLACEMENT_3D('',#1590,#1591,#1592);
#1594=CONICAL_SURFACE('',#1593,2.,0.523598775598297);
#1595=ORIENTED_EDGE('',*,*,#1585,.F.);
#1596=EDGE_LOOP('',(#1595));
#1597=FACE_BOUND('',#1596,.T.);
#1598=ORIENTED_EDGE('',*,*,#1557,.F.);
#1599=EDGE_LOOP('',(#1598));
#1600=FACE_BOUND('',#1599,.T.);
#1601=ADVANCED_FACE('F571',(#1597,#1600),#1594,.T.);
#1602=CARTESIAN_POINT('',(-10.125,14.,4.35));
#1603=DIRECTION('',(0.,0.,-1.));
#1604=DIRECTION('',(-1.,0.,0.));
#1605=AXIS2_PLACEMENT_3D('',#1602,#1603,#1604);
#1606=CYLINDRICAL_SURFACE('',#1605,8.12500000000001);
#1607=ORIENTED_EDGE('',*,*,#1020,.F.);
#1608=CARTESIAN_POINT('',(-2.,14.,4.33115825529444));
#1609=CARTESIAN_POINT('',(-1.99999641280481,14.0468718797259,4.33744913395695));
#1610=CARTESIAN_POINT('',(-2.00040373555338,14.0938417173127,4.34216471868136));
#1611=CARTESIAN_POINT('',(-2.00204020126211,14.1879773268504,4.34844530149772));
#1612=CARTESIAN_POINT('',(-2.00326934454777,14.2351430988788,4.35001029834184));
#1613=CARTESIAN_POINT('',(-2.00490939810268,14.2824068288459,4.35));
#1614=B_SPLINE_CURVE_WITH_KNOTS('',3,(#1608,#1609,#1610,#1611,#1612,#1613),.UNSPECIFIED.,.F.,
.F.,(4,2,4),(0.,0.141623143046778,0.283246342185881),.UNSPECIFIED.);
#1615=EDGE_CURVE('E654',#1012,#32,#1614,.T.);
#1616=ORIENTED_EDGE('',*,*,#1615,.T.);
#1617=ORIENTED_EDGE('',*,*,#33,.F.);
#1618=DIRECTION('',(0.,0.,-1.));
#1619=VECTOR('',#1618,1.);
#1620=CARTESIAN_POINT('',(-2.08042264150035,15.140350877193,4.35));
#1621=LINE('',#1620,#1619);
#1622=CARTESIAN_POINT('',(-2.08042264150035,15.140350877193,4.));
#1623=VERTEX_POINT('',#1622);
#1624=EDGE_CURVE('E680',#30,#1623,#1621,.T.);
#1625=ORIENTED_EDGE('',*,*,#1624,.T.);
#1626=CARTESIAN_POINT('',(-10.125,14.,4.));
#1627=DIRECTION('',(0.,0.,-1.));
#1628=DIRECTION('',(-1.,0.,0.));
#1629=AXIS2_PLACEMENT_3D('',#1626,#1627,#1628);
#1630=CIRCLE('',#1629,8.12500000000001);
#1631=CARTESIAN_POINT('',(-2.00433357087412,14.265333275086,4.));
#1632=VERTEX_POINT('',#1631);
#1633=EDGE_CURVE('E399',#1623,#1632,#1630,.T.);
#1634=ORIENTED_EDGE('',*,*,#1633,.T.);
#1635=CARTESIAN_POINT('',(-2.00433357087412,14.265333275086,4.));
#1636=CARTESIAN_POINT('',(-2.00288621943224,14.2209465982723,4.00000822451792));
#1637=CARTESIAN_POINT('',(-2.00180141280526,14.1766421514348,3.99861828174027));
#1638=CARTESIAN_POINT('',(-2.00035688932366,14.0881977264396,3.99304206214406));
#1639=CARTESIAN_POINT('',(-1.99999717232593,14.0440577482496,3.98885578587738));
#1640=CARTESIAN_POINT('',(-2.,14.0000000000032,3.983271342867));
#1641=B_SPLINE_CURVE_WITH_KNOTS('',3,(#1635,#1636,#1637,#1638,#1639,#1640),.UNSPECIFIED.,.F.,
.F.,(4,2,4),(0.,0.133018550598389,0.266037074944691),.UNSPECIFIED.);
#1642=EDGE_CURVE('E84',#1632,#1027,#1641,.T.);
#1643=ORIENTED_EDGE('',*,*,#1642,.T.);
#1644=ORIENTED_EDGE('',*,*,#1028,.F.);
#1645=EDGE_LOOP('',(#1607,#1616,#1617,#1625,#1634,#1643,#1644));
#1646=FACE_BOUND('',#1645,.T.);
#1647=ADVANCED_FACE('F560',(#1646),#1606,.F.);
#1648=CARTESIAN_POINT('',(10.125,14.,4.35));
#1649=DIRECTION('',(0.,0.,-1.));
#1650=DIRECTION('',(-1.,0.,0.));
#1651=AXIS2_PLACEMENT_3D('',#1648,#1649,#1650);
#1652=CYLINDRICAL_SURFACE('',#1651,8.12500000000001);
#1653=ORIENTED_EDGE('',*,*,#328,.F.);
#1654=CARTESIAN_POINT('',(2.00490939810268,14.2824068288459,4.35));
#1655=CARTESIAN_POINT('',(2.0032693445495,14.2351430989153,4.35001029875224));
#1656=CARTESIAN_POINT('',(2.00204020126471,14.1879773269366,4.34844530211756));
#1657=CARTESIAN_POINT('',(2.00040373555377,14.0938417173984,4.34216471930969));
#1658=CARTESIAN_POINT('',(1.99999641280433,14.0468718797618,4.33744913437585));
#1659=CARTESIAN_POINT('',(2.,14.,4.33115825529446));
#1660=B_SPLINE_CURVE_WITH_KNOTS('',3,(#1654,#1655,#1656,#1657,#1658,#1659),.UNSPECIFIED.,.F.,
.F.,(4,2,4),(0.,0.141623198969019,0.283246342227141),.UNSPECIFIED.);
#1661=EDGE_CURVE('E641',#318,#1501,#1660,.T.);
#1662=ORIENTED_EDGE('',*,*,#1661,.T.);
#1663=ORIENTED_EDGE('',*,*,#1502,.F.);
#1664=ORIENTED_EDGE('',*,*,#1534,.T.);
#1665=CARTESIAN_POINT('',(2.00000000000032,14.0000000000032,3.9832713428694));
#1666=CARTESIAN_POINT('',(1.99999717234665,14.0440577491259,3.9888557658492));
#1667=CARTESIAN_POINT('',(2.00035688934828,14.0881977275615,3.99304203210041));
#1668=CARTESIAN_POINT('',(2.00180141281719,14.1766421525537,3.99861825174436));
#1669=CARTESIAN_POINT('',(2.00288621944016,14.2209465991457,4.00000820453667));
#1670=CARTESIAN_POINT('',(2.00433357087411,14.265333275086,4.));
#1671=B_SPLINE_CURVE_WITH_KNOTS('',3,(#1665,#1666,#1667,#1668,#1669,#1670),.UNSPECIFIED.,.F.,
.F.,(4,2,4),(0.,0.133018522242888,0.266037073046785),.UNSPECIFIED.);
#1672=CARTESIAN_POINT('',(2.00433357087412,14.265333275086,4.));
#1673=VERTEX_POINT('',#1672);
#1674=EDGE_CURVE('E521',#1527,#1673,#1671,.T.);
#1675=ORIENTED_EDGE('',*,*,#1674,.T.);
#1676=CARTESIAN_POINT('',(10.125,14.,4.));
#1677=DIRECTION('',(0.,0.,-1.));
#1678=DIRECTION('',(1.,0.,0.));
#1679=AXIS2_PLACEMENT_3D('',#1676,#1677,#1678);
#1680=CIRCLE('',#1679,8.12500000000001);
#1681=CARTESIAN_POINT('',(2.08042264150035,15.140350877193,4.));
#1682=VERTEX_POINT('',#1681);
#1683=EDGE_CURVE('E402',#1673,#1682,#1680,.T.);
#1684=ORIENTED_EDGE('',*,*,#1683,.T.);
#1685=DIRECTION('',(0.,0.,-1.));
#1686=VECTOR('',#1685,1.);
#1687=CARTESIAN_POINT('',(2.08042264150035,15.140350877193,4.35));
#1688=LINE('',#1687,#1686);
#1689=EDGE_CURVE('E677',#1682,#327,#1688,.F.);
#1690=ORIENTED_EDGE('',*,*,#1689,.T.);
#1691=EDGE_LOOP('',(#1653,#1662,#1663,#1664,#1675,#1684,#1690));
#1692=FACE_BOUND('',#1691,.T.);
#1693=ADVANCED_FACE('F503',(#1692),#1652,.F.);
#1694=CARTESIAN_POINT('',(0.,22.,4.));
#1695=DIRECTION('',(0.,0.,1.));
#1696=DIRECTION('',(1.,0.,0.));
#1697=AXIS2_PLACEMENT_3D('',#1694,#1695,#1696);
#1698=PLANE('',#1697);
#1699=ORIENTED_EDGE('',*,*,#1568,.T.);
#1700=EDGE_LOOP('',(#1699));
#1701=FACE_BOUND('',#1700,.T.);
#1702=ORIENTED_EDGE('',*,*,#1683,.F.);
#1703=CARTESIAN_POINT('',(2.6960427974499,14.4132418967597,4.));
#1704=CARTESIAN_POINT('',(2.62694105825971,14.3990356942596,4.));
#1705=CARTESIAN_POINT('',(2.55787837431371,14.3846406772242,4.));
#1706=CARTESIAN_POINT('',(2.41982423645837,14.3555185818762,4.));
#1707=CARTESIAN_POINT('',(2.35083278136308,14.3407915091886,4.));
#1708=CARTESIAN_POINT('',(2.21291286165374,14.3110505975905,4.));
#1709=CARTESIAN_POINT('',(2.14398439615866,14.2960367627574,4.));
#1710=CARTESIAN_POINT('',(2.00617665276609,14.2657793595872,4.));
#1711=CARTESIAN_POINT('',(1.93729737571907,14.2505357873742,4.));
#1712=CARTESIAN_POINT('',(1.86843744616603,14.2352062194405,4.));
#1713=CARTESIAN_POINT('',(1.82867812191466,14.2263554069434,4.));
#1714=CARTESIAN_POINT('',(1.78886310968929,14.2177569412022,4.));
#1715=CARTESIAN_POINT('',(1.70911176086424,14.2010760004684,4.));
#1716=CARTESIAN_POINT('',(1.66917538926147,14.1929936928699,4.));
#1717=CARTESIAN_POINT('',(1.53973259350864,14.1676943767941,4.));
#1718=CARTESIAN_POINT('',(1.45001474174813,14.1515444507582,4.));
#1719=CARTESIAN_POINT('',(1.27011509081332,14.1220345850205,4.));
#1720=CARTESIAN_POINT('',(1.17993325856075,14.108674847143,4.));
#1721=CARTESIAN_POINT('',(0.999188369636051,14.0848717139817,4.));
#1722=CARTESIAN_POINT('',(0.908625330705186,14.0744281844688,4.));
#1723=CARTESIAN_POINT('',(0.727206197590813,14.0565090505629,4.));
#1724=CARTESIAN_POINT('',(0.636350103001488,14.0490334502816,4.));
#1725=CARTESIAN_POINT('',(0.454619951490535,14.037055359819,4.));
#1726=CARTESIAN_POINT('',(0.363746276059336,14.0325470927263,4.));
#1727=CARTESIAN_POINT('',(0.181915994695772,14.0265178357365,4.));
#1728=CARTESIAN_POINT('',(0.0909594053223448,14.0249963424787,4.));
#1729=CARTESIAN_POINT('',(-0.118220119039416,14.0249957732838,4.));
#1730=CARTESIAN_POINT('',(-0.23644499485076,14.0275651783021,4.));
#1731=CARTESIAN_POINT('',(-0.440552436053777,14.0363429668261,4.));
#1732=CARTESIAN_POINT('',(-0.526488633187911,14.0413719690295,4.));
#1733=CARTESIAN_POINT('',(-0.698175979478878,14.0540681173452,4.));
#1734=CARTESIAN_POINT('',(-0.783927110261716,14.0617355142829,4.));
#1735=CARTESIAN_POINT('',(-0.953470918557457,14.0795422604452,4.));
#1736=CARTESIAN_POINT('',(-1.03726901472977,14.0896301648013,4.));
#1737=CARTESIAN_POINT('',(-1.20453481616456,14.1122918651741,4.));
#1738=CARTESIAN_POINT('',(-1.28800249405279,14.1248658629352,4.));
#1739=CARTESIAN_POINT('',(-1.454566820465,14.1524086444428,4.));
#1740=CARTESIAN_POINT('',(-1.53766334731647,14.1673781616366,4.));
#1741=CARTESIAN_POINT('',(-1.70340103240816,14.1996033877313,4.));
#1742=CARTESIAN_POINT('',(-1.78604224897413,14.2168587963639,4.));
#1743=CARTESIAN_POINT('',(-1.86843744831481,14.2352062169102,4.));
#1744=CARTESIAN_POINT('',(-1.89396081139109,14.2408878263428,4.));
#1745=CARTESIAN_POINT('',(-1.91948675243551,14.2465578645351,4.));
#1746=CARTESIAN_POINT('',(-1.97054429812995,14.2578715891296,4.));
#1747=CARTESIAN_POINT('',(-1.99607590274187,14.2635152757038,4.));
#1748=CARTESIAN_POINT('',(-2.04714221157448,14.2747724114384,4.));
#1749=CARTESIAN_POINT('',(-2.07267691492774,14.2803858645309,4.));
#1750=CARTESIAN_POINT('',(-2.12375361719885,14.291580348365,4.));
#1751=CARTESIAN_POINT('',(-2.14929561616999,14.2971613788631,4.));
#1752=CARTESIAN_POINT('',(-2.27460361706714,14.3244501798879,4.));
#1753=CARTESIAN_POINT('',(-2.3744252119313,14.345904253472,4.));
#1754=CARTESIAN_POINT('',(-2.57421486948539,14.3881194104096,4.));
#1755=CARTESIAN_POINT('',(-2.67418293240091,14.4088804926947,4.));
#1756=CARTESIAN_POINT('',(-2.97433621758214,14.4699443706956,4.));
#1757=CARTESIAN_POINT('',(-3.17477192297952,14.5090281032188,4.));
#1758=CARTESIAN_POINT('',(-3.5763521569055,14.5835019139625,4.));
#1759=CARTESIAN_POINT('',(-3.77749676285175,14.6188915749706,4.));
#1760=CARTESIAN_POINT('',(-4.1803984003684,14.6859968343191,4.));
#1761=CARTESIAN_POINT('',(-4.38215543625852,14.7177124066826,4.));
#1762=CARTESIAN_POINT('',(-4.78657195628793,14.7777787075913,4.));
#1763=CARTESIAN_POINT('',(-4.98923243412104,14.8061227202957,4.));
#1764=CARTESIAN_POINT('',(-5.3949633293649,14.8597210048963,4.));
#1765=CARTESIAN_POINT('',(-5.59803375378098,14.8849752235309,4.));
#1766=CARTESIAN_POINT('',(-6.00448449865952,14.9327581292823,4.));
#1767=CARTESIAN_POINT('',(-6.20786480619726,14.9552869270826,4.));
#1768=CARTESIAN_POINT('',(-6.61486306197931,14.997955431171,4.));
#1769=CARTESIAN_POINT('',(-6.81848099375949,15.0180952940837,4.));
#1770=CARTESIAN_POINT('',(-7.02219084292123,15.0372097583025,4.));
#1771=B_SPLINE_CURVE_WITH_KNOTS('',3,(#1703,#1704,#1705,#1706,#1707,#1708,#1709,#1710,#1711,
#1712,#1713,#1714,#1715,#1716,#1717,#1718,#1719,#1720,#1721,#1722,#1723,#1724,#1725,#1726,#1727,
#1728,#1729,#1730,#1731,#1732,#1733,#1734,#1735,#1736,#1737,#1738,#1739,#1740,#1741,#1742,#1743,
#1744,#1745,#1746,#1747,#1748,#1749,#1750,#1751,#1752,#1753,#1754,#1755,#1756,#1757,#1758,#1759,
#1760,#1761,#1762,#1763,#1764,#1765,#1766,#1767,#1768,#1769,#1770),.UNSPECIFIED.,.F.,.F.,(4,2,2,
2,3,2,2,2,2,2,2,2,2,2,2,2,2,2,2,3,2,2,2,2,2,2,2,2,2,2,2,2,4),(0.,0.211640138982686,
0.42327669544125,0.634910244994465,0.846547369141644,0.968743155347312,1.09097837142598,
1.36441191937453,1.63786523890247,1.91130596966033,2.18474707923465,2.45765425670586,
2.73051543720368,3.08515365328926,3.34336658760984,3.60160407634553,3.85477553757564,
4.1079675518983,4.36123723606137,4.61447368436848,4.69291796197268,4.77136172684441,
4.849795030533,4.9282289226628,5.2345297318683,5.54083101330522,6.15342931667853,
6.76609673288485,7.3787684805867,7.99264087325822,8.60652384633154,9.22038188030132,
9.83419964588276),.UNSPECIFIED.);
#1772=EDGE_CURVE('E509',#1673,#1632,#1771,.T.);
#1773=ORIENTED_EDGE('',*,*,#1772,.T.);
#1774=ORIENTED_EDGE('',*,*,#1633,.F.);
#1775=CARTESIAN_POINT('',(-3.07052447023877,15.,4.));
#1776=DIRECTION('',(0.,0.,1.));
#1777=DIRECTION('',(1.,0.,0.));
#1778=AXIS2_PLACEMENT_3D('',#1775,#1776,#1777);
#1779=CIRCLE('',#1778,1.);
#1780=CARTESIAN_POINT('',(-2.25,15.5716114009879,4.));
#1781=VERTEX_POINT('',#1780);
#1782=EDGE_CURVE('E711',#1623,#1781,#1779,.T.);
#1783=ORIENTED_EDGE('',*,*,#1782,.T.);
#1784=DIRECTION('',(0.,-1.,0.));
#1785=VECTOR('',#1784,1.);
#1786=CARTESIAN_POINT('',(-2.25,16.,4.));
#1787=LINE('',#1786,#1785);
#1788=CARTESIAN_POINT('',(-2.25,22.,4.));
#1789=VERTEX_POINT('',#1788);
#1790=EDGE_CURVE('E397',#1789,#1781,#1787,.T.);
#1791=ORIENTED_EDGE('',*,*,#1790,.F.);
#1792=CARTESIAN_POINT('',(0.,22.,4.));
#1793=DIRECTION('',(0.,0.,1.));
#1794=DIRECTION('',(1.,0.,0.));
#1795=AXIS2_PLACEMENT_3D('',#1792,#1793,#1794);
#1796=CIRCLE('',#1795,2.25);
#1797=CARTESIAN_POINT('',(2.25,22.,4.));
#1798=VERTEX_POINT('',#1797);
#1799=EDGE_CURVE('E385',#1798,#1789,#1796,.T.);
#1800=ORIENTED_EDGE('',*,*,#1799,.F.);
#1801=DIRECTION('',(0.,1.,0.));
#1802=VECTOR('',#1801,1.);
#1803=CARTESIAN_POINT('',(2.25,22.,4.));
#1804=LINE('',#1803,#1802);
#1805=CARTESIAN_POINT('',(2.25,15.5716114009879,4.));
#1806=VERTEX_POINT('',#1805);
#1807=EDGE_CURVE('E388',#1806,#1798,#1804,.T.);
#1808=ORIENTED_EDGE('',*,*,#1807,.F.);
#1809=CARTESIAN_POINT('',(3.07052447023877,15.,4.));
#1810=DIRECTION('',(0.,0.,1.));
#1811=DIRECTION('',(1.,0.,0.));
#1812=AXIS2_PLACEMENT_3D('',#1809,#1810,#1811);
#1813=CIRCLE('',#1812,1.);
#1814=EDGE_CURVE('E609',#1806,#1682,#1813,.T.);
#1815=ORIENTED_EDGE('',*,*,#1814,.T.);
#1816=EDGE_LOOP('',(#1702,#1773,#1774,#1783,#1791,#1800,#1808,#1815));
#1817=FACE_BOUND('',#1816,.T.);
#1818=ADVANCED_FACE('F498',(#1701,#1817),#1698,.F.);
#1819=CARTESIAN_POINT('',(-2.25,22.,5.5));
#1820=DIRECTION('',(0.,-1.,0.));
#1821=DIRECTION('',(1.,0.,0.));
#1822=AXIS2_PLACEMENT_3D('',#1819,#1820,#1821);
#1823=CYLINDRICAL_SURFACE('',#1822,1.15);
#1824=CARTESIAN_POINT('',(-2.25,22.,5.5));
#1825=DIRECTION('',(0.,1.,0.));
#1826=DIRECTION('',(-1.,0.,0.));
#1827=AXIS2_PLACEMENT_3D('',#1824,#1825,#1826);
#1828=CIRCLE('',#1827,1.15);
#1829=CARTESIAN_POINT('',(-3.4,22.,5.5));
#1830=VERTEX_POINT('',#1829);
#1831=EDGE_CURVE('E350',#353,#1830,#1828,.T.);
#1832=ORIENTED_EDGE('',*,*,#1831,.T.);
#1833=DIRECTION('',(0.,-1.,0.));
#1834=VECTOR('',#1833,1.);
#1835=CARTESIAN_POINT('',(-3.4,22.,5.5));
#1836=LINE('',#1835,#1834);
#1837=CARTESIAN_POINT('',(-3.4,16.,5.5));
#1838=VERTEX_POINT('',#1837);
#1839=EDGE_CURVE('E382',#1830,#1838,#1836,.T.);
#1840=ORIENTED_EDGE('',*,*,#1839,.T.);
#1841=CARTESIAN_POINT('',(-2.25,16.,5.5));
#1842=DIRECTION('',(0.,1.,0.));
#1843=DIRECTION('',(-1.,0.,0.));
#1844=AXIS2_PLACEMENT_3D('',#1841,#1842,#1843);
#1845=CIRCLE('',#1844,1.15);
#1846=CARTESIAN_POINT('',(-3.07052447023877,16.,4.69424594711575));
#1847=VERTEX_POINT('',#1846);
#1848=EDGE_CURVE('E371',#1847,#1838,#1845,.T.);
#1849=ORIENTED_EDGE('',*,*,#1848,.F.);
#1850=CARTESIAN_POINT('',(-3.07052447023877,16.,4.69424594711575));
#1851=CARTESIAN_POINT('',(-3.05340682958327,15.999999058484,4.67681368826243));
#1852=CARTESIAN_POINT('',(-3.03573594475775,15.9995598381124,4.65993220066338));
#1853=CARTESIAN_POINT('',(-2.99937606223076,15.9976325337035,4.62734157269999));
#1854=CARTESIAN_POINT('',(-2.98068631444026,15.9961436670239,4.61163331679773));
#1855=CARTESIAN_POINT('',(-2.92318853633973,15.9898365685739,4.56635542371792));
#1856=CARTESIAN_POINT('',(-2.88301781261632,15.9831765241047,4.53869957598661));
#1857=CARTESIAN_POINT('',(-2.80037097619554,15.9637562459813,4.48909580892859));
#1858=CARTESIAN_POINT('',(-2.7578842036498,15.9509652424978,4.46717755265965));
#1859=CARTESIAN_POINT('',(-2.67285086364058,15.918648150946,4.42955540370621));
#1860=CARTESIAN_POINT('',(-2.6303047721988,15.8991404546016,4.41383479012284));
#1861=CARTESIAN_POINT('',(-2.55023490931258,15.8551211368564,4.38915014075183));
#1862=CARTESIAN_POINT('',(-2.51257275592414,15.8310883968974,4.3797712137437));
#1863=CARTESIAN_POINT('',(-2.44025535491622,15.7776786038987,4.36524614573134));
#1864=CARTESIAN_POINT('',(-2.40560541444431,15.7482923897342,4.36010734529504));
#1865=CARTESIAN_POINT('',(-2.35030077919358,15.6944702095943,4.35415273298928));
#1866=CARTESIAN_POINT('',(-2.32857226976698,15.6712055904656,4.35250138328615));
#1867=CARTESIAN_POINT('',(-2.28748591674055,15.6227817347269,4.35042863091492));
#1868=CARTESIAN_POINT('',(-2.26811867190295,15.5976307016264,4.35000218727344));
#1869=CARTESIAN_POINT('',(-2.25,15.5716114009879,4.35));
#1870=B_SPLINE_CURVE_WITH_KNOTS('',3,(#1850,#1851,#1852,#1853,#1854,#1855,#1856,#1857,#1858,
#1859,#1860,#1861,#1862,#1863,#1864,#1865,#1866,#1867,#1868,#1869),.UNSPECIFIED.,.F.,.F.,(4,2,2,
2,2,2,2,2,2,4),(0.,0.0732637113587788,0.146582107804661,0.293497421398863,0.44115791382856,
0.588417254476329,0.724746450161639,0.861311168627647,0.95678115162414,1.05185767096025),.UNSPECIFIED.);
#1871=EDGE_CURVE('E707',#1847,#361,#1870,.T.);
#1872=ORIENTED_EDGE('',*,*,#1871,.T.);
#1873=ORIENTED_EDGE('',*,*,#362,.F.);
#1874=EDGE_LOOP('',(#1832,#1840,#1849,#1872,#1873));
#1875=FACE_BOUND('',#1874,.T.);
#1876=ADVANCED_FACE('F502',(#1875),#1823,.F.);
#1877=CARTESIAN_POINT('',(-3.4,22.,5.5));
#1878=DIRECTION('',(1.,0.,0.));
#1879=DIRECTION('',(0.,1.,0.));
#1880=AXIS2_PLACEMENT_3D('',#1877,#1878,#1879);
#1881=PLANE('',#1880);
#1882=DIRECTION('',(0.,0.,1.));
#1883=VECTOR('',#1882,1.);
#1884=CARTESIAN_POINT('',(-3.4,22.,5.5));
#1885=LINE('',#1884,#1883);
#1886=CARTESIAN_POINT('',(-3.4,22.,5.75));
#1887=VERTEX_POINT('',#1886);
#1888=EDGE_CURVE('E293',#1830,#1887,#1885,.T.);
#1889=ORIENTED_EDGE('',*,*,#1888,.T.);
#1890=DIRECTION('',(0.,-1.,0.));
#1891=VECTOR('',#1890,1.);
#1892=CARTESIAN_POINT('',(-3.4,22.,5.75));
#1893=LINE('',#1892,#1891);
#1894=CARTESIAN_POINT('',(-3.4,16.,5.75));
#1895=VERTEX_POINT('',#1894);
#1896=EDGE_CURVE('E379',#1887,#1895,#1893,.T.);
#1897=ORIENTED_EDGE('',*,*,#1896,.T.);
#1898=DIRECTION('',(0.,0.,1.));
#1899=VECTOR('',#1898,1.);
#1900=CARTESIAN_POINT('',(-3.4,16.,5.5));
#1901=LINE('',#1900,#1899);
#1902=EDGE_CURVE('E368',#1838,#1895,#1901,.T.);
#1903=ORIENTED_EDGE('',*,*,#1902,.F.);
#1904=ORIENTED_EDGE('',*,*,#1839,.F.);
#1905=EDGE_LOOP('',(#1889,#1897,#1903,#1904));
#1906=FACE_BOUND('',#1905,.T.);
#1907=ADVANCED_FACE('F724',(#1906),#1881,.T.);
#1908=CARTESIAN_POINT('',(-3.75,22.,5.75));
#1909=DIRECTION('',(-1.,0.,0.));
#1910=DIRECTION('',(0.,-1.,0.));
#1911=AXIS2_PLACEMENT_3D('',#1908,#1909,#1910);
#1912=PLANE('',#1911);
#1913=DIRECTION('',(0.,0.,-1.));
#1914=VECTOR('',#1913,1.);
#1915=CARTESIAN_POINT('',(-3.75,22.,5.75));
#1916=LINE('',#1915,#1914);
#1917=CARTESIAN_POINT('',(-3.75,22.,5.75));
#1918=VERTEX_POINT('',#1917);
#1919=CARTESIAN_POINT('',(-3.75,22.,5.5));
#1920=VERTEX_POINT('',#1919);
#1921=EDGE_CURVE('E346',#1918,#1920,#1916,.T.);
#1922=ORIENTED_EDGE('',*,*,#1921,.T.);
#1923=DIRECTION('',(0.,-1.,0.));
#1924=VECTOR('',#1923,1.);
#1925=CARTESIAN_POINT('',(-3.75,22.,5.5));
#1926=LINE('',#1925,#1924);
#1927=CARTESIAN_POINT('',(-3.75,16.,5.5));
#1928=VERTEX_POINT('',#1927);
#1929=EDGE_CURVE('E373',#1920,#1928,#1926,.T.);
#1930=ORIENTED_EDGE('',*,*,#1929,.T.);
#1931=DIRECTION('',(0.,0.,-1.));
#1932=VECTOR('',#1931,1.);
#1933=CARTESIAN_POINT('',(-3.75,16.,5.75));
#1934=LINE('',#1933,#1932);
#1935=CARTESIAN_POINT('',(-3.75,16.,5.75));
#1936=VERTEX_POINT('',#1935);
#1937=EDGE_CURVE('E362',#1936,#1928,#1934,.T.);
#1938=ORIENTED_EDGE('',*,*,#1937,.F.);
#1939=DIRECTION('',(0.,-1.,0.));
#1940=VECTOR('',#1939,1.);
#1941=CARTESIAN_POINT('',(-3.75,22.,5.75));
#1942=LINE('',#1941,#1940);
#1943=EDGE_CURVE('E376',#1918,#1936,#1942,.T.);
#1944=ORIENTED_EDGE('',*,*,#1943,.F.);
#1945=EDGE_LOOP('',(#1922,#1930,#1938,#1944));
#1946=FACE_BOUND('',#1945,.T.);
#1947=ADVANCED_FACE('F727',(#1946),#1912,.T.);
#1948=CARTESIAN_POINT('',(-2.25,22.,5.5));
#1949=DIRECTION('',(0.,-1.,0.));
#1950=DIRECTION('',(1.,0.,0.));
#1951=AXIS2_PLACEMENT_3D('',#1948,#1949,#1950);
#1952=CYLINDRICAL_SURFACE('',#1951,1.5);
#1953=CARTESIAN_POINT('',(-2.25,22.,5.5));
#1954=DIRECTION('',(0.,-1.,0.));
#1955=DIRECTION('',(-1.,0.,0.));
#1956=AXIS2_PLACEMENT_3D('',#1953,#1954,#1955);
#1957=CIRCLE('',#1956,1.5);
#1958=EDGE_CURVE('E315',#1920,#1789,#1957,.T.);
#1959=ORIENTED_EDGE('',*,*,#1958,.T.);
#1960=ORIENTED_EDGE('',*,*,#1790,.T.);
#1961=CARTESIAN_POINT('',(-2.25,15.5716114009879,4.));
#1962=CARTESIAN_POINT('',(-2.26476657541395,15.5928080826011,4.00000137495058));
#1963=CARTESIAN_POINT('',(-2.28034962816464,15.6134243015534,4.00021831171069));
#1964=CARTESIAN_POINT('',(-2.31306062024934,15.6533884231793,4.00123628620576));
#1965=CARTESIAN_POINT('',(-2.33018910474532,15.6727358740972,4.00203753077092));
#1966=CARTESIAN_POINT('',(-2.38376245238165,15.7287112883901,4.00554842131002));
#1967=CARTESIAN_POINT('',(-2.42237966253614,15.7632500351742,4.0093655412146));
#1968=CARTESIAN_POINT('',(-2.50420527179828,15.825799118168,4.02111845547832));
#1969=CARTESIAN_POINT('',(-2.54742698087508,15.8537897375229,4.02906646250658));
#1970=CARTESIAN_POINT('',(-2.63664297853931,15.9023968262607,4.04996652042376));
#1971=CARTESIAN_POINT('',(-2.68263269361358,15.9230250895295,4.0629104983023));
#1972=CARTESIAN_POINT('',(-2.7732562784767,15.9559536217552,4.09345071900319));
#1973=CARTESIAN_POINT('',(-2.81784905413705,15.9686065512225,4.11079341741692));
#1974=CARTESIAN_POINT('',(-2.90625872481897,15.9874507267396,4.15030896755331));
#1975=CARTESIAN_POINT('',(-2.95007559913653,15.993641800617,4.172481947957));
#1976=CARTESIAN_POINT('',(-3.00598842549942,15.9980037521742,4.20434785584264));
#1977=CARTESIAN_POINT('',(-3.01907512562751,15.9987603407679,4.21207311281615));
#1978=CARTESIAN_POINT('',(-3.04498944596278,15.9997574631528,4.227906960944));
#1979=CARTESIAN_POINT('',(-3.05781763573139,15.9999992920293,4.23601453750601));
#1980=CARTESIAN_POINT('',(-3.07052447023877,16.,4.2443170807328));
#1981=B_SPLINE_CURVE_WITH_KNOTS('',3,(#1961,#1962,#1963,#1964,#1965,#1966,#1967,#1968,#1969,
#1970,#1971,#1972,#1973,#1974,#1975,#1976,#1977,#1978,#1979,#1980),.UNSPECIFIED.,.F.,.F.,(4,2,2,
2,2,2,2,2,2,4),(0.,0.0774584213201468,0.154944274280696,0.309996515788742,0.465509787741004,
0.620772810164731,0.768572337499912,0.916375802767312,0.962012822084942,1.00753488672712),.UNSPECIFIED.);
#1982=CARTESIAN_POINT('',(-3.07052447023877,16.,4.2443170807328));
#1983=VERTEX_POINT('',#1982);
#1984=EDGE_CURVE('E708',#1781,#1983,#1981,.T.);
#1985=ORIENTED_EDGE('',*,*,#1984,.T.);
#1986=CARTESIAN_POINT('',(-2.25,16.,5.5));
#1987=DIRECTION('',(0.,-1.,0.));
#1988=DIRECTION('',(-1.,0.,0.));
#1989=AXIS2_PLACEMENT_3D('',#1986,#1987,#1988);
#1990=CIRCLE('',#1989,1.5);
#1991=EDGE_CURVE('E296',#1928,#1983,#1990,.T.);
#1992=ORIENTED_EDGE('',*,*,#1991,.F.);
#1993=ORIENTED_EDGE('',*,*,#1929,.F.);
#1994=EDGE_LOOP('',(#1959,#1960,#1985,#1992,#1993));
#1995=FACE_BOUND('',#1994,.T.);
#1996=ADVANCED_FACE('F730',(#1995),#1952,.T.);
#1997=CARTESIAN_POINT('',(0.,22.,5.5));
#1998=DIRECTION('',(0.,0.,1.));
#1999=DIRECTION('',(1.,0.,0.));
#2000=AXIS2_PLACEMENT_3D('',#1997,#1998,#1999);
#2001=TOROIDAL_SURFACE('',#2000,2.25,1.15);
#2002=CARTESIAN_POINT('',(2.25,22.,5.5));
#2003=DIRECTION('',(0.,-1.,0.));
#2004=DIRECTION('',(1.,0.,0.));
#2005=AXIS2_PLACEMENT_3D('',#2002,#2003,#2004);
#2006=CIRCLE('',#2005,1.15);
#2007=CARTESIAN_POINT('',(3.4,22.,5.5));
#2008=VERTEX_POINT('',#2007);
#2009=EDGE_CURVE('E301',#344,#2008,#2006,.T.);
#2010=ORIENTED_EDGE('',*,*,#2009,.T.);
#2011=CARTESIAN_POINT('',(0.,22.,5.5));
#2012=DIRECTION('',(0.,0.,1.));
#2013=DIRECTION('',(1.,0.,0.));
#2014=AXIS2_PLACEMENT_3D('',#2011,#2012,#2013);
#2015=CIRCLE('',#2014,3.4);
#2016=EDGE_CURVE('E285',#2008,#1830,#2015,.T.);
#2017=ORIENTED_EDGE('',*,*,#2016,.T.);
#2018=ORIENTED_EDGE('',*,*,#1831,.F.);
#2019=ORIENTED_EDGE('',*,*,#354,.F.);
#2020=EDGE_LOOP('',(#2010,#2017,#2018,#2019));
#2021=FACE_BOUND('',#2020,.T.);
#2022=ADVANCED_FACE('F303',(#2021),#2001,.F.);
#2023=CARTESIAN_POINT('',(0.,22.,4.35));
#2024=DIRECTION('',(0.,0.,1.));
#2025=DIRECTION('',(1.,0.,0.));
#2026=AXIS2_PLACEMENT_3D('',#2023,#2024,#2025);
#2027=CYLINDRICAL_SURFACE('',#2026,3.4);
#2028=DIRECTION('',(0.,0.,1.));
#2029=VECTOR('',#2028,1.);
#2030=CARTESIAN_POINT('',(3.4,22.,5.5));
#2031=LINE('',#2030,#2029);
#2032=CARTESIAN_POINT('',(3.4,22.,5.75));
#2033=VERTEX_POINT('',#2032);
#2034=EDGE_CURVE('E290',#2008,#2033,#2031,.T.);
#2035=ORIENTED_EDGE('',*,*,#2034,.T.);
#2036=CARTESIAN_POINT('',(0.,22.,5.75));
#2037=DIRECTION('',(0.,0.,1.));
#2038=DIRECTION('',(1.,0.,0.));
#2039=AXIS2_PLACEMENT_3D('',#2036,#2037,#2038);
#2040=CIRCLE('',#2039,3.4);
#2041=EDGE_CURVE('E297',#2033,#1887,#2040,.T.);
#2042=ORIENTED_EDGE('',*,*,#2041,.T.);
#2043=ORIENTED_EDGE('',*,*,#1888,.F.);
#2044=ORIENTED_EDGE('',*,*,#2016,.F.);
#2045=EDGE_LOOP('',(#2035,#2042,#2043,#2044));
#2046=FACE_BOUND('',#2045,.T.);
#2047=ADVANCED_FACE('F287',(#2046),#2027,.F.);
#2048=CARTESIAN_POINT('',(0.,22.,4.35));
#2049=DIRECTION('',(0.,0.,1.));
#2050=DIRECTION('',(1.,0.,0.));
#2051=AXIS2_PLACEMENT_3D('',#2048,#2049,#2050);
#2052=CYLINDRICAL_SURFACE('',#2051,3.75);
#2053=DIRECTION('',(0.,0.,-1.));
#2054=VECTOR('',#2053,1.);
#2055=CARTESIAN_POINT('',(3.75,22.,5.75));
#2056=LINE('',#2055,#2054);
#2057=CARTESIAN_POINT('',(3.75,22.,5.75));
#2058=VERTEX_POINT('',#2057);
#2059=CARTESIAN_POINT('',(3.75,22.,5.5));
#2060=VERTEX_POINT('',#2059);
#2061=EDGE_CURVE('E320',#2058,#2060,#2056,.T.);
#2062=ORIENTED_EDGE('',*,*,#2061,.T.);
#2063=CARTESIAN_POINT('',(0.,22.,5.5));
#2064=DIRECTION('',(0.,0.,1.));
#2065=DIRECTION('',(1.,0.,0.));
#2066=AXIS2_PLACEMENT_3D('',#2063,#2064,#2065);
#2067=CIRCLE('',#2066,3.75);
#2068=EDGE_CURVE('E353',#2060,#1920,#2067,.T.);
#2069=ORIENTED_EDGE('',*,*,#2068,.T.);
#2070=ORIENTED_EDGE('',*,*,#1921,.F.);
#2071=CARTESIAN_POINT('',(0.,22.,5.75));
#2072=DIRECTION('',(0.,0.,1.));
#2073=DIRECTION('',(1.,0.,0.));
#2074=AXIS2_PLACEMENT_3D('',#2071,#2072,#2073);
#2075=CIRCLE('',#2074,3.75);
#2076=EDGE_CURVE('E356',#2058,#1918,#2075,.T.);
#2077=ORIENTED_EDGE('',*,*,#2076,.F.);
#2078=EDGE_LOOP('',(#2062,#2069,#2070,#2077));
#2079=FACE_BOUND('',#2078,.T.);
#2080=ADVANCED_FACE('F740',(#2079),#2052,.T.);
#2081=CARTESIAN_POINT('',(0.,22.,5.5));
#2082=DIRECTION('',(0.,0.,1.));
#2083=DIRECTION('',(1.,0.,0.));
#2084=AXIS2_PLACEMENT_3D('',#2081,#2082,#2083);
#2085=TOROIDAL_SURFACE('',#2084,2.25,1.5);
#2086=CARTESIAN_POINT('',(2.25,22.,5.5));
#2087=DIRECTION('',(0.,1.,0.));
#2088=DIRECTION('',(1.,0.,0.));
#2089=AXIS2_PLACEMENT_3D('',#2086,#2087,#2088);
#2090=CIRCLE('',#2089,1.5);
#2091=EDGE_CURVE('E306',#2060,#1798,#2090,.T.);
#2092=ORIENTED_EDGE('',*,*,#2091,.T.);
#2093=ORIENTED_EDGE('',*,*,#1799,.T.);
#2094=ORIENTED_EDGE('',*,*,#1958,.F.);
#2095=ORIENTED_EDGE('',*,*,#2068,.F.);
#2096=EDGE_LOOP('',(#2092,#2093,#2094,#2095));
#2097=FACE_BOUND('',#2096,.T.);
#2098=ADVANCED_FACE('F743',(#2097),#2085,.T.);
#2099=CARTESIAN_POINT('',(2.25,22.,5.5));
#2100=DIRECTION('',(0.,-1.,0.));
#2101=DIRECTION('',(1.,0.,0.));
#2102=AXIS2_PLACEMENT_3D('',#2099,#2100,#2101);
#2103=CYLINDRICAL_SURFACE('',#2102,1.5);
#2104=CARTESIAN_POINT('',(2.25,16.,5.5));
#2105=DIRECTION('',(0.,1.,0.));
#2106=DIRECTION('',(1.,0.,0.));
#2107=AXIS2_PLACEMENT_3D('',#2104,#2105,#2106);
#2108=CIRCLE('',#2107,1.5);
#2109=CARTESIAN_POINT('',(3.75,16.,5.5));
#2110=VERTEX_POINT('',#2109);
#2111=CARTESIAN_POINT('',(3.07052447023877,16.,4.2443170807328));
#2112=VERTEX_POINT('',#2111);
#2113=EDGE_CURVE('E327',#2110,#2112,#2108,.T.);
#2114=ORIENTED_EDGE('',*,*,#2113,.T.);
#2115=CARTESIAN_POINT('',(3.07052447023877,16.,4.2443170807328));
#2116=CARTESIAN_POINT('',(3.0489507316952,15.9999997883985,4.23021795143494));
#2117=CARTESIAN_POINT('',(3.02701596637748,15.9993008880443,4.2166809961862));
#2118=CARTESIAN_POINT('',(2.98254367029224,15.996372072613,4.1907855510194));
#2119=CARTESIAN_POINT('',(2.96000576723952,15.9941411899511,4.17842781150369));
#2120=CARTESIAN_POINT('',(2.89173135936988,15.9849541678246,4.14324234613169));
#2121=CARTESIAN_POINT('',(2.84531198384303,15.9755039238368,4.12228793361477));
#2122=CARTESIAN_POINT('',(2.75223520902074,15.949231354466,4.08568946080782));
#2123=CARTESIAN_POINT('',(2.70557760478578,15.9323794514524,4.07006715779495));
#2124=CARTESIAN_POINT('',(2.61418097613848,15.8912110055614,4.04410611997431));
#2125=CARTESIAN_POINT('',(2.56943979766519,15.866903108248,4.03376130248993));
#2126=CARTESIAN_POINT('',(2.4858455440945,15.8127169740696,4.0180761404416));
#2127=CARTESIAN_POINT('',(2.44680881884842,15.783184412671,4.01250827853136));
#2128=CARTESIAN_POINT('',(2.3733087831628,15.7185280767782,4.00461982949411));
#2129=CARTESIAN_POINT('',(2.33884405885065,15.6834060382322,4.00229823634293));
#2130=CARTESIAN_POINT('',(2.29704952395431,15.6340214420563,4.00070376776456));
#2131=CARTESIAN_POINT('',(2.28721904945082,15.6218347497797,4.00043135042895));
#2132=CARTESIAN_POINT('',(2.26816114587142,15.5970395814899,4.00007985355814));
#2133=CARTESIAN_POINT('',(2.25893240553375,15.5844321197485,4.00000033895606));
#2134=CARTESIAN_POINT('',(2.25,15.5716114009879,4.));
#2135=B_SPLINE_CURVE_WITH_KNOTS('',3,(#2115,#2116,#2117,#2118,#2119,#2120,#2121,#2122,#2123,
#2124,#2125,#2126,#2127,#2128,#2129,#2130,#2131,#2132,#2133,#2134),.UNSPECIFIED.,.F.,.F.,(4,2,2,
2,2,2,2,2,2,4),(0.,0.0772840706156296,0.154616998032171,0.309204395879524,0.464415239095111,
0.619446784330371,0.766603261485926,0.913714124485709,0.960681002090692,1.00754185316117),.UNSPECIFIED.);
#2136=EDGE_CURVE('E756',#2112,#1806,#2135,.T.);
#2137=ORIENTED_EDGE('',*,*,#2136,.T.);
#2138=ORIENTED_EDGE('',*,*,#1807,.T.);
#2139=ORIENTED_EDGE('',*,*,#2091,.F.);
#2140=DIRECTION('',(0.,-1.,0.));
#2141=VECTOR('',#2140,1.);
#2142=CARTESIAN_POINT('',(3.75,22.,5.5));
#2143=LINE('',#2142,#2141);
#2144=EDGE_CURVE('E323',#2060,#2110,#2143,.T.);
#2145=ORIENTED_EDGE('',*,*,#2144,.T.);
#2146=EDGE_LOOP('',(#2114,#2137,#2138,#2139,#2145));
#2147=FACE_BOUND('',#2146,.T.);
#2148=ADVANCED_FACE('F747',(#2147),#2103,.T.);
#2149=CARTESIAN_POINT('',(2.25,22.,5.5));
#2150=DIRECTION('',(0.,-1.,0.));
#2151=DIRECTION('',(1.,0.,0.));
#2152=AXIS2_PLACEMENT_3D('',#2149,#2150,#2151);
#2153=CYLINDRICAL_SURFACE('',#2152,1.15);
#2154=ORIENTED_EDGE('',*,*,#345,.F.);
#2155=CARTESIAN_POINT('',(2.25,15.5716114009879,4.35));
#2156=CARTESIAN_POINT('',(2.26399631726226,15.5917025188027,4.35000160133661));
#2157=CARTESIAN_POINT('',(2.27872678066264,15.6112727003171,4.35025581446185));
#2158=CARTESIAN_POINT('',(2.30957918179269,15.6492784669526,4.3514400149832));
#2159=CARTESIAN_POINT('',(2.32570186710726,15.6677134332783,4.35237036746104));
#2160=CARTESIAN_POINT('',(2.37610030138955,15.7212308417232,4.3564380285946));
#2161=CARTESIAN_POINT('',(2.4123376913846,15.7544272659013,4.36085359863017));
#2162=CARTESIAN_POINT('',(2.48890644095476,15.8149305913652,4.37441614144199));
#2163=CARTESIAN_POINT('',(2.52925428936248,15.8422122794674,4.38358282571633));
#2164=CARTESIAN_POINT('',(2.61206371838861,15.8899938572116,4.40763668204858));
#2165=CARTESIAN_POINT('',(2.65451878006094,15.9105133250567,4.42250706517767));
#2166=CARTESIAN_POINT('',(2.73659909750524,15.9435667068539,4.45713475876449));
#2167=CARTESIAN_POINT('',(2.77621642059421,15.9565557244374,4.47648165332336));
#2168=CARTESIAN_POINT('',(2.8540340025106,15.9771156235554,4.52038730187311));
#2169=CARTESIAN_POINT('',(2.89223146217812,15.9846762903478,4.54495576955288));
#2170=CARTESIAN_POINT('',(2.95414820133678,15.9935313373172,4.59024767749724));
#2171=CARTESIAN_POINT('',(2.97862579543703,15.9960512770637,4.60972976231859));
#2172=CARTESIAN_POINT('',(3.02587984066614,15.9992822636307,4.65059705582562));
#2173=CARTESIAN_POINT('',(3.04866331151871,16.0000012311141,4.67197350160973));
#2174=CARTESIAN_POINT('',(3.07052447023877,16.,4.69424594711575));
#2175=B_SPLINE_CURVE_WITH_KNOTS('',3,(#2155,#2156,#2157,#2158,#2159,#2160,#2161,#2162,#2163,
#2164,#2165,#2166,#2167,#2168,#2169,#2170,#2171,#2172,#2173,#2174),.UNSPECIFIED.,.F.,.F.,(4,2,2,
2,2,2,2,2,2,4),(0.,0.073421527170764,0.146882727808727,0.294161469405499,0.442056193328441,
0.589518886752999,0.726755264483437,0.864249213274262,0.958258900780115,1.05185440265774),.UNSPECIFIED.);
#2176=CARTESIAN_POINT('',(3.07052447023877,16.,4.69424594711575));
#2177=VERTEX_POINT('',#2176);
#2178=EDGE_CURVE('E775',#336,#2177,#2175,.T.);
#2179=ORIENTED_EDGE('',*,*,#2178,.T.);
#2180=CARTESIAN_POINT('',(2.25,16.,5.5));
#2181=DIRECTION('',(0.,-1.,0.));
#2182=DIRECTION('',(1.,0.,0.));
#2183=AXIS2_PLACEMENT_3D('',#2180,#2181,#2182);
#2184=CIRCLE('',#2183,1.15);
#2185=CARTESIAN_POINT('',(3.4,16.,5.5));
#2186=VERTEX_POINT('',#2185);
#2187=EDGE_CURVE('E312',#2177,#2186,#2184,.T.);
#2188=ORIENTED_EDGE('',*,*,#2187,.T.);
#2189=DIRECTION('',(0.,-1.,0.));
#2190=VECTOR('',#2189,1.);
#2191=CARTESIAN_POINT('',(3.4,22.,5.5));
#2192=LINE('',#2191,#2190);
#2193=EDGE_CURVE('E309',#2008,#2186,#2192,.T.);
#2194=ORIENTED_EDGE('',*,*,#2193,.F.);
#2195=ORIENTED_EDGE('',*,*,#2009,.F.);
#2196=EDGE_LOOP('',(#2154,#2179,#2188,#2194,#2195));
#2197=FACE_BOUND('',#2196,.T.);
#2198=ADVANCED_FACE('F310',(#2197),#2153,.F.);
#2199=CARTESIAN_POINT('',(3.4,22.,5.5));
#2200=DIRECTION('',(1.,0.,0.));
#2201=DIRECTION('',(0.,1.,0.));
#2202=AXIS2_PLACEMENT_3D('',#2199,#2200,#2201);
#2203=PLANE('',#2202);
#2204=DIRECTION('',(0.,0.,1.));
#2205=VECTOR('',#2204,1.);
#2206=CARTESIAN_POINT('',(3.4,16.,5.5));
#2207=LINE('',#2206,#2205);
#2208=CARTESIAN_POINT('',(3.4,16.,5.75));
#2209=VERTEX_POINT('',#2208);
#2210=EDGE_CURVE('E332',#2186,#2209,#2207,.T.);
#2211=ORIENTED_EDGE('',*,*,#2210,.T.);
#2212=DIRECTION('',(0.,-1.,0.));
#2213=VECTOR('',#2212,1.);
#2214=CARTESIAN_POINT('',(3.4,22.,5.75));
#2215=LINE('',#2214,#2213);
#2216=EDGE_CURVE('E316',#2033,#2209,#2215,.T.);
#2217=ORIENTED_EDGE('',*,*,#2216,.F.);
#2218=ORIENTED_EDGE('',*,*,#2034,.F.);
#2219=ORIENTED_EDGE('',*,*,#2193,.T.);
#2220=EDGE_LOOP('',(#2211,#2217,#2218,#2219));
#2221=FACE_BOUND('',#2220,.T.);
#2222=ADVANCED_FACE('F318',(#2221),#2203,.F.);
#2223=CARTESIAN_POINT('',(3.4,22.,5.75));
#2224=DIRECTION('',(0.,0.,-1.));
#2225=DIRECTION('',(-1.,0.,0.));
#2226=AXIS2_PLACEMENT_3D('',#2223,#2224,#2225);
#2227=PLANE('',#2226);
#2228=DIRECTION('',(1.,0.,0.));
#2229=VECTOR('',#2228,1.);
#2230=CARTESIAN_POINT('',(3.4,16.,5.75));
#2231=LINE('',#2230,#2229);
#2232=CARTESIAN_POINT('',(3.75,16.,5.75));
#2233=VERTEX_POINT('',#2232);
#2234=EDGE_CURVE('E334',#2209,#2233,#2231,.T.);
#2235=ORIENTED_EDGE('',*,*,#2234,.T.);
#2236=DIRECTION('',(0.,-1.,0.));
#2237=VECTOR('',#2236,1.);
#2238=CARTESIAN_POINT('',(3.75,22.,5.75));
#2239=LINE('',#2238,#2237);
#2240=EDGE_CURVE('E340',#2058,#2233,#2239,.T.);
#2241=ORIENTED_EDGE('',*,*,#2240,.F.);
#2242=ORIENTED_EDGE('',*,*,#2076,.T.);
#2243=ORIENTED_EDGE('',*,*,#1943,.T.);
#2244=DIRECTION('',(-1.,0.,0.));
#2245=VECTOR('',#2244,1.);
#2246=CARTESIAN_POINT('',(-3.4,16.,5.75));
#2247=LINE('',#2246,#2245);
#2248=EDGE_CURVE('E365',#1895,#1936,#2247,.T.);
#2249=ORIENTED_EDGE('',*,*,#2248,.F.);
#2250=ORIENTED_EDGE('',*,*,#1896,.F.);
#2251=ORIENTED_EDGE('',*,*,#2041,.F.);
#2252=ORIENTED_EDGE('',*,*,#2216,.T.);
#2253=EDGE_LOOP('',(#2235,#2241,#2242,#2243,#2249,#2250,#2251,#2252));
#2254=FACE_BOUND('',#2253,.T.);
#2255=ADVANCED_FACE('F798',(#2254),#2227,.F.);
#2256=CARTESIAN_POINT('',(3.75,22.,5.75));
#2257=DIRECTION('',(-1.,0.,0.));
#2258=DIRECTION('',(0.,-1.,0.));
#2259=AXIS2_PLACEMENT_3D('',#2256,#2257,#2258);
#2260=PLANE('',#2259);
#2261=DIRECTION('',(0.,0.,-1.));
#2262=VECTOR('',#2261,1.);
#2263=CARTESIAN_POINT('',(3.75,16.,5.75));
#2264=LINE('',#2263,#2262);
#2265=EDGE_CURVE('E336',#2233,#2110,#2264,.T.);
#2266=ORIENTED_EDGE('',*,*,#2265,.T.);
#2267=ORIENTED_EDGE('',*,*,#2144,.F.);
#2268=ORIENTED_EDGE('',*,*,#2061,.F.);
#2269=ORIENTED_EDGE('',*,*,#2240,.T.);
#2270=EDGE_LOOP('',(#2266,#2267,#2268,#2269));
#2271=FACE_BOUND('',#2270,.T.);
#2272=ADVANCED_FACE('F804',(#2271),#2260,.F.);
#2273=CARTESIAN_POINT('',(-2.25,16.,5.5));
#2274=DIRECTION('',(0.,1.,0.));
#2275=DIRECTION('',(-1.,0.,0.));
#2276=AXIS2_PLACEMENT_3D('',#2273,#2274,#2275);
#2277=PLANE('',#2276);
#2278=ORIENTED_EDGE('',*,*,#1991,.T.);
#2279=DIRECTION('',(0.,0.,1.));
#2280=VECTOR('',#2279,1.);
#2281=CARTESIAN_POINT('',(-3.07052447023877,16.,4.35));
#2282=LINE('',#2281,#2280);
#2283=EDGE_CURVE('E763',#1983,#1847,#2282,.T.);
#2284=ORIENTED_EDGE('',*,*,#2283,.T.);
#2285=ORIENTED_EDGE('',*,*,#1848,.T.);
#2286=ORIENTED_EDGE('',*,*,#1902,.T.);
#2287=ORIENTED_EDGE('',*,*,#2248,.T.);
#2288=ORIENTED_EDGE('',*,*,#1937,.T.);
#2289=EDGE_LOOP('',(#2278,#2284,#2285,#2286,#2287,#2288));
#2290=FACE_BOUND('',#2289,.T.);
#2291=ADVANCED_FACE('F784',(#2290),#2277,.F.);
#2292=CARTESIAN_POINT('',(2.25,16.,5.5));
#2293=DIRECTION('',(0.,-1.,0.));
#2294=DIRECTION('',(1.,0.,0.));
#2295=AXIS2_PLACEMENT_3D('',#2292,#2293,#2294);
#2296=PLANE('',#2295);
#2297=ORIENTED_EDGE('',*,*,#2187,.F.);
#2298=DIRECTION('',(0.,0.,-1.));
#2299=VECTOR('',#2298,1.);
#2300=CARTESIAN_POINT('',(3.07052447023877,16.,5.5));
#2301=LINE('',#2300,#2299);
#2302=EDGE_CURVE('E669',#2177,#2112,#2301,.T.);
#2303=ORIENTED_EDGE('',*,*,#2302,.T.);
#2304=ORIENTED_EDGE('',*,*,#2113,.F.);
#2305=ORIENTED_EDGE('',*,*,#2265,.F.);
#2306=ORIENTED_EDGE('',*,*,#2234,.F.);
#2307=ORIENTED_EDGE('',*,*,#2210,.F.);
#2308=EDGE_LOOP('',(#2297,#2303,#2304,#2305,#2306,#2307));
#2309=FACE_BOUND('',#2308,.T.);
#2310=ADVANCED_FACE('F769',(#2309),#2296,.T.);
#2311=CARTESIAN_POINT('',(3.07052447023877,15.,4.35));
#2312=DIRECTION('',(0.,0.,-1.));
#2313=DIRECTION('',(-1.,0.,0.));
#2314=AXIS2_PLACEMENT_3D('',#2311,#2312,#2313);
#2315=CYLINDRICAL_SURFACE('',#2314,1.);
#2316=ORIENTED_EDGE('',*,*,#337,.F.);
#2317=ORIENTED_EDGE('',*,*,#1689,.F.);
#2318=ORIENTED_EDGE('',*,*,#1814,.F.);
#2319=ORIENTED_EDGE('',*,*,#2136,.F.);
#2320=ORIENTED_EDGE('',*,*,#2302,.F.);
#2321=ORIENTED_EDGE('',*,*,#2178,.F.);
#2322=EDGE_LOOP('',(#2316,#2317,#2318,#2319,#2320,#2321));
#2323=FACE_BOUND('',#2322,.T.);
#2324=ADVANCED_FACE('F765',(#2323),#2315,.F.);
#2325=CARTESIAN_POINT('',(-3.07052447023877,15.,4.35));
#2326=DIRECTION('',(0.,0.,-1.));
#2327=DIRECTION('',(-1.,0.,0.));
#2328=AXIS2_PLACEMENT_3D('',#2325,#2326,#2327);
#2329=CYLINDRICAL_SURFACE('',#2328,1.);
#2330=ORIENTED_EDGE('',*,*,#1871,.F.);
#2331=ORIENTED_EDGE('',*,*,#2283,.F.);
#2332=ORIENTED_EDGE('',*,*,#1984,.F.);
#2333=ORIENTED_EDGE('',*,*,#1782,.F.);
#2334=ORIENTED_EDGE('',*,*,#1624,.F.);
#2335=ORIENTED_EDGE('',*,*,#369,.F.);
#2336=EDGE_LOOP('',(#2330,#2331,#2332,#2333,#2334,#2335));
#2337=FACE_BOUND('',#2336,.T.);
#2338=ADVANCED_FACE('F446',(#2337),#2329,.F.);
#2339=ORIENTED_EDGE('',*,*,#1661,.F.);
#2340=ORIENTED_EDGE('',*,*,#319,.F.);
#2341=ORIENTED_EDGE('',*,*,#1615,.F.);
#2342=ORIENTED_EDGE('',*,*,#1013,.F.);
#2343=ORIENTED_EDGE('',*,*,#1467,.F.);
#2344=ORIENTED_EDGE('',*,*,#1514,.F.);
#2345=EDGE_LOOP('',(#2339,#2340,#2341,#2342,#2343,#2344));
#2346=FACE_BOUND('',#2345,.T.);
#2347=ADVANCED_FACE('F450',(#2346),#245,.T.);
#2348=ORIENTED_EDGE('',*,*,#1642,.F.);
#2349=ORIENTED_EDGE('',*,*,#1772,.F.);
#2350=ORIENTED_EDGE('',*,*,#1674,.F.);
#2351=ORIENTED_EDGE('',*,*,#1528,.F.);
#2352=ORIENTED_EDGE('',*,*,#1355,.F.);
#2353=ORIENTED_EDGE('',*,*,#1247,.F.);
#2354=EDGE_LOOP('',(#2348,#2349,#2350,#2351,#2352,#2353));
#2355=FACE_BOUND('',#2354,.T.);
#2356=ADVANCED_FACE('F456',(#2355),#1233,.F.);
#2357=CARTESIAN_POINT('',(0.,22.,4.85));
#2358=DIRECTION('',(0.,0.,-1.));
#2359=DIRECTION('',(-1.,0.,0.));
#2360=AXIS2_PLACEMENT_3D('',#2357,#2358,#2359);
#2361=CYLINDRICAL_SURFACE('',#2360,2.);
#2362=CARTESIAN_POINT('',(0.,22.,4.85));
#2363=DIRECTION('',(0.,0.,1.));
#2364=DIRECTION('',(1.,0.,0.));
#2365=AXIS2_PLACEMENT_3D('',#2362,#2363,#2364);
#2366=CIRCLE('',#2365,2.);
#2367=CARTESIAN_POINT('',(2.,22.,4.85));
#2368=VERTEX_POINT('',#2367);
#2369=EDGE_CURVE('E330',#2368,#2368,#2366,.T.);
#2370=ORIENTED_EDGE('',*,*,#2369,.F.);
#2371=EDGE_LOOP('',(#2370));
#2372=FACE_BOUND('',#2371,.T.);
#2373=ORIENTED_EDGE('',*,*,#380,.T.);
#2374=EDGE_LOOP('',(#2373));
#2375=FACE_BOUND('',#2374,.T.);
#2376=ADVANCED_FACE('F488',(#2372,#2375),#2361,.T.);
#2377=CARTESIAN_POINT('',(0.,22.,4.85));
#2378=DIRECTION('',(0.,0.,1.));
#2379=DIRECTION('',(1.,0.,0.));
#2380=AXIS2_PLACEMENT_3D('',#2377,#2378,#2379);
#2381=PLANE('',#2380);
#2382=ORIENTED_EDGE('',*,*,#2369,.T.);
#2383=EDGE_LOOP('',(#2382));
#2384=FACE_BOUND('',#2383,.T.);
#2385=ADVANCED_FACE('F812',(#2384),#2381,.T.);
#2386=CLOSED_SHELL('',(#384,#566,#608,#710,#735,#759,#784,#888,#921,#943,#957,#973,#1262,#1367,
#1474,#1544,#1572,#1589,#1601,#1647,#1693,#1818,#1876,#1907,#1947,#1996,#2022,#2047,#2080,#2098,
#2148,#2198,#2222,#2255,#2272,#2291,#2310,#2324,#2338,#2347,#2356,#2376,#2385));
#2387=MANIFOLD_SOLID_BREP('B2',#2386);
#2388=CARTESIAN_POINT('',(0.,23.3995833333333,0.));
#2389=DIRECTION('',(0.,-1.,0.));
#2390=DIRECTION('',(-1.,0.,0.));
#2391=AXIS2_PLACEMENT_3D('',#2388,#2389,#2390);
#2392=SPHERICAL_SURFACE('',#2391,4.10041666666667);
#2393=CARTESIAN_POINT('',(0.,24.5,0.));
#2394=DIRECTION('',(0.,-1.,0.));
#2395=DIRECTION('',(0.,0.,-1.));
#2396=AXIS2_PLACEMENT_3D('',#2393,#2394,#2395);
#2397=CIRCLE('',#2396,3.95);
#2398=CARTESIAN_POINT('',(-3.74699879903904,24.5,-1.25));
#2399=VERTEX_POINT('',#2398);
#2400=CARTESIAN_POINT('',(3.74699879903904,24.5,-1.25));
#2401=VERTEX_POINT('',#2400);
#2402=EDGE_CURVE('E1462',#2399,#2401,#2397,.T.);
#2403=ORIENTED_EDGE('',*,*,#2402,.F.);
#2404=CARTESIAN_POINT('',(0.,23.3995833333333,-1.25));
#2405=DIRECTION('',(0.,0.,-1.));
#2406=DIRECTION('',(0.,1.,0.));
#2407=AXIS2_PLACEMENT_3D('',#2404,#2405,#2406);
#2408=CIRCLE('',#2407,3.90524222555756);
#2409=EDGE_CURVE('E1450',#2399,#2401,#2408,.T.);
#2410=ORIENTED_EDGE('',*,*,#2409,.T.);
#2411=EDGE_LOOP('',(#2403,#2410));
#2412=FACE_BOUND('',#2411,.T.);
#2413=ADVANCED_FACE('F1377',(#2412),#2392,.T.);
#2414=CARTESIAN_POINT('',(0.,22.,-3.95));
#2415=DIRECTION('',(0.,0.,1.));
#2416=DIRECTION('',(1.,0.,0.));
#2417=AXIS2_PLACEMENT_3D('',#2414,#2415,#2416);
#2418=CYLINDRICAL_SURFACE('',#2417,2.);
#2419=CARTESIAN_POINT('',(0.,22.,-1.25));
#2420=DIRECTION('',(0.,0.,-1.));
#2421=DIRECTION('',(0.,1.,0.));
#2422=AXIS2_PLACEMENT_3D('',#2419,#2420,#2421);
#2423=CIRCLE('',#2422,2.);
#2424=CARTESIAN_POINT('',(0.,24.,-1.25));
#2425=VERTEX_POINT('',#2424);
#2426=EDGE_CURVE('E1441',#2425,#2425,#2423,.F.);
#2427=ORIENTED_EDGE('',*,*,#2426,.T.);
#2428=EDGE_LOOP('',(#2427));
#2429=FACE_BOUND('',#2428,.T.);
#2430=CARTESIAN_POINT('',(0.,24.,-3.95));
#2431=CARTESIAN_POINT('',(-0.104983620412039,23.9999933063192,-3.9499941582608));
#2432=CARTESIAN_POINT('',(-0.210087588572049,23.9916853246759,-3.94576996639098));
#2433=CARTESIAN_POINT('',(-0.417179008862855,23.9588256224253,-3.92928792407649));
#2434=CARTESIAN_POINT('',(-0.519160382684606,23.9342440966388,-3.917015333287));
#2435=CARTESIAN_POINT('',(-0.716696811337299,23.870050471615,-3.88571861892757));
#2436=CARTESIAN_POINT('',(-0.812275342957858,23.8304972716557,-3.86672097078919));
#2437=CARTESIAN_POINT('',(-0.995292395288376,23.7377934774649,-3.82370807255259));
#2438=CARTESIAN_POINT('',(-1.08273142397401,23.6846437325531,-3.79969313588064));
#2439=CARTESIAN_POINT('',(-1.25304361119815,23.5625387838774,-3.74710640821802));
#2440=CARTESIAN_POINT('',(-1.33530406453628,23.4928118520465,-3.71834507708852));
#2441=CARTESIAN_POINT('',(-1.48753011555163,23.3411971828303,-3.66011053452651));
#2442=CARTESIAN_POINT('',(-1.5574860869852,23.2593000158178,-3.63063678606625));
#2443=CARTESIAN_POINT('',(-1.68873758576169,23.0778147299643,-3.57158944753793));
#2444=CARTESIAN_POINT('',(-1.7488917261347,22.9773352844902,-3.54219669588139));
#2445=CARTESIAN_POINT('',(-1.85119389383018,22.7660475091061,-3.48982886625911));
#2446=CARTESIAN_POINT('',(-1.89335501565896,22.6552467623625,-3.46684912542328));
#2447=CARTESIAN_POINT('',(-1.95569231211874,22.4332786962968,-3.43205204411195));
#2448=CARTESIAN_POINT('',(-1.97704409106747,22.3225389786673,-3.41964357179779));
#2449=CARTESIAN_POINT('',(-2.00074426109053,22.0984121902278,-3.40583807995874));
#2450=CARTESIAN_POINT('',(-2.00311231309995,21.9850279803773,-3.4044296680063));
#2451=CARTESIAN_POINT('',(-1.98963915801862,21.7738860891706,-3.41231034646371));
#2452=CARTESIAN_POINT('',(-1.97600909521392,21.6759267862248,-3.4203007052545));
#2453=CARTESIAN_POINT('',(-1.93476738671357,21.483937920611,-3.44379627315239));
#2454=CARTESIAN_POINT('',(-1.90715109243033,21.3899096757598,-3.45930398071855));
#2455=CARTESIAN_POINT('',(-1.83822953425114,21.2057650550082,-3.49642201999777));
#2456=CARTESIAN_POINT('',(-1.7966212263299,21.1157902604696,-3.51816572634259));
#2457=CARTESIAN_POINT('',(-1.70113186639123,20.9436625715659,-3.56531670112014));
#2458=CARTESIAN_POINT('',(-1.64724529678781,20.8615132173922,-3.59072561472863));
#2459=CARTESIAN_POINT('',(-1.52053541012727,20.6960847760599,-3.64634803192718));
#2460=CARTESIAN_POINT('',(-1.44615870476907,20.6140566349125,-3.67675587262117));
#2461=CARTESIAN_POINT('',(-1.28459905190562,20.4631087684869,-3.73627064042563));
#2462=CARTESIAN_POINT('',(-1.19740972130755,20.3941956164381,-3.76537690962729));
#2463=CARTESIAN_POINT('',(-1.00732850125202,20.2682667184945,-3.82073870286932));
#2464=CARTESIAN_POINT('',(-0.903878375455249,20.2119946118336,-3.84678612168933));
#2465=CARTESIAN_POINT('',(-0.687328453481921,20.1181197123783,-3.89130543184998));
#2466=CARTESIAN_POINT('',(-0.57423658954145,20.0805017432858,-3.90978347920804));
#2467=CARTESIAN_POINT('',(-0.351822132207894,20.0281597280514,-3.93575734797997));
#2468=CARTESIAN_POINT('',(-0.242984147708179,20.0117744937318,-3.94404697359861));
#2469=CARTESIAN_POINT('',(-0.0238044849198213,19.9971324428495,-3.95144692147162));
#2470=CARTESIAN_POINT('',(0.0865364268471,19.9988667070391,-3.95056175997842));
#2471=CARTESIAN_POINT('',(0.29620506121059,20.0194774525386,-3.94016577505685));
#2472=CARTESIAN_POINT('',(0.395708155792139,20.0369727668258,-3.93135001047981));
#2473=CARTESIAN_POINT('',(0.590158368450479,20.0864221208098,-3.90689387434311));
#2474=CARTESIAN_POINT('',(0.68510498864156,20.1183777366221,-3.8912527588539));
#2475=CARTESIAN_POINT('',(0.87083865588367,20.1966463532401,-3.85400686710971));
#2476=CARTESIAN_POINT('',(0.961434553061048,20.2433366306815,-3.83224724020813));
#2477=CARTESIAN_POINT('',(1.13379915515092,20.3493189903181,-3.78483853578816));
#2478=CARTESIAN_POINT('',(1.21556412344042,20.4086163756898,-3.75918782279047));
#2479=CARTESIAN_POINT('',(1.37662904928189,20.5449700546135,-3.70342566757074));
#2480=CARTESIAN_POINT('',(1.45486328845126,20.6232097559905,-3.67312471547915));
#2481=CARTESIAN_POINT('',(1.59758608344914,20.7917268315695,-3.61333895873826));
#2482=CARTESIAN_POINT('',(1.66206452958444,20.8820129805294,-3.58385476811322));
#2483=CARTESIAN_POINT('',(1.77860946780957,21.0779393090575,-3.52752862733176));
#2484=CARTESIAN_POINT('',(1.82985992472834,21.1841325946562,-3.50090268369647));
#2485=CARTESIAN_POINT('',(1.91321513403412,21.4054103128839,-3.45606425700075));
#2486=CARTESIAN_POINT('',(1.9453451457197,21.5204827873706,-3.43784068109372));
#2487=CARTESIAN_POINT('',(1.98653546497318,21.7443651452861,-3.41418963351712));
#2488=CARTESIAN_POINT('',(1.99752637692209,21.8527043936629,-3.4076950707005));
#2489=CARTESIAN_POINT('',(2.00172335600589,22.0698256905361,-3.40523392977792));
#2490=CARTESIAN_POINT('',(1.9949378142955,22.1786075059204,-3.40926238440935));
#2491=CARTESIAN_POINT('',(1.9655904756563,22.3820418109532,-3.42624963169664));
#2492=CARTESIAN_POINT('',(1.94467344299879,22.4770197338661,-3.43827551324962));
#2493=CARTESIAN_POINT('',(1.88972755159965,22.6620013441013,-3.46877660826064));
#2494=CARTESIAN_POINT('',(1.85569438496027,22.7520033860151,-3.48725394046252));
#2495=CARTESIAN_POINT('',(1.77294076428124,22.9311628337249,-3.53008279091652));
#2496=CARTESIAN_POINT('',(1.72338921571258,23.0198598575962,-3.55474487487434));
#2497=CARTESIAN_POINT('',(1.61190515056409,23.1882641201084,-3.60666640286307));
#2498=CARTESIAN_POINT('',(1.54996611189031,23.2679665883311,-3.63392721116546));
#2499=CARTESIAN_POINT('',(1.40633937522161,23.4265495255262,-3.69207713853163));
#2500=CARTESIAN_POINT('',(1.32314769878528,23.504066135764,-3.72299141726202));
#2501=CARTESIAN_POINT('',(1.14411263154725,23.6443662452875,-3.78184878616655));
#2502=CARTESIAN_POINT('',(1.04826225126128,23.7071415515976,-3.80979021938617));
#2503=CARTESIAN_POINT('',(0.844990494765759,23.8164355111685,-3.85999433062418));
#2504=CARTESIAN_POINT('',(0.737463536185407,23.8627863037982,-3.8821977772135));
#2505=CARTESIAN_POINT('',(0.514809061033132,23.9361364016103,-3.91791849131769));
#2506=CARTESIAN_POINT('',(0.399703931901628,23.963190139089,-3.93146018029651));
#2507=CARTESIAN_POINT('',(0.236145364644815,23.9865757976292,-3.94321711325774));
#2508=CARTESIAN_POINT('',(0.189101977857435,23.9916023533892,-3.94575368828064));
#2509=CARTESIAN_POINT('',(0.0947138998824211,23.9983160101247,-3.94914647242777));
#2510=CARTESIAN_POINT('',(0.0473692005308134,24.0000030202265,-3.95000263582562));
#2511=CARTESIAN_POINT('',(0.,24.,-3.95));
#2512=B_SPLINE_CURVE_WITH_KNOTS('',3,(#2430,#2431,#2432,#2433,#2434,#2435,#2436,#2437,#2438,
#2439,#2440,#2441,#2442,#2443,#2444,#2445,#2446,#2447,#2448,#2449,#2450,#2451,#2452,#2453,#2454,
#2455,#2456,#2457,#2458,#2459,#2460,#2461,#2462,#2463,#2464,#2465,#2466,#2467,#2468,#2469,#2470,
#2471,#2472,#2473,#2474,#2475,#2476,#2477,#2478,#2479,#2480,#2481,#2482,#2483,#2484,#2485,#2486,
#2487,#2488,#2489,#2490,#2491,#2492,#2493,#2494,#2495,#2496,#2497,#2498,#2499,#2500,#2501,#2502,
#2503,#2504,#2505,#2506,#2507,#2508,#2509,#2510,#2511),.UNSPECIFIED.,.T.,.F.,(4,2,2,2,2,2,2,2,2,
2,2,2,2,2,2,2,2,2,2,2,2,2,2,2,2,2,2,2,2,2,2,2,2,2,2,2,2,2,2,2,4),(0.,0.314758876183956,
0.630095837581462,0.94420492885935,1.25829440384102,1.59172472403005,1.92541474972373,
2.28581398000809,2.64595047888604,2.98430223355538,3.32230352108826,3.61859197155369,
3.91497896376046,4.21824987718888,4.5216573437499,4.86464980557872,5.20781372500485,
5.5677043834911,5.92730176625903,6.25661632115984,6.58576877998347,6.88861378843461,
7.19149181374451,7.50285820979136,7.8143558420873,8.15702917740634,8.49995349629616,
8.86064281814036,9.2208545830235,9.54622942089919,9.87145069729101,10.1641634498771,
10.4569724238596,10.7693944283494,11.0819813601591,11.4338783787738,11.7859705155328,
12.1415637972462,12.4961500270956,12.6381671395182,12.7801881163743),.UNSPECIFIED.);
#2513=CARTESIAN_POINT('',(0.,24.,-3.95));
#2514=VERTEX_POINT('',#2513);
#2515=EDGE_CURVE('E1470',#2514,#2514,#2512,.T.);
#2516=ORIENTED_EDGE('',*,*,#2515,.F.);
#2517=EDGE_LOOP('',(#2516));
#2518=FACE_BOUND('',#2517,.T.);
#2519=ADVANCED_FACE('F1483',(#2429,#2518),#2418,.F.);
#2520=CARTESIAN_POINT('',(3.74699879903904,24.5,1.25));
#2521=VERTEX_POINT('',#2520);
#2522=CARTESIAN_POINT('',(-3.74699879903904,24.5,1.25));
#2523=VERTEX_POINT('',#2522);
#2524=EDGE_CURVE('E1440',#2521,#2523,#2397,.T.);
#2525=ORIENTED_EDGE('',*,*,#2524,.F.);
#2526=CARTESIAN_POINT('',(0.,23.3995833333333,1.25));
#2527=DIRECTION('',(0.,0.,1.));
#2528=DIRECTION('',(0.,-1.,0.));
#2529=AXIS2_PLACEMENT_3D('',#2526,#2527,#2528);
#2530=CIRCLE('',#2529,3.90524222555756);
#2531=EDGE_CURVE('E1396',#2521,#2523,#2530,.T.);
#2532=ORIENTED_EDGE('',*,*,#2531,.T.);
#2533=EDGE_LOOP('',(#2525,#2532));
#2534=FACE_BOUND('',#2533,.T.);
#2535=ADVANCED_FACE('F1379',(#2534),#2392,.T.);
#2536=CARTESIAN_POINT('',(0.,0.,0.));
#2537=DIRECTION('',(0.,-1.,0.));
#2538=DIRECTION('',(0.,0.,-1.));
#2539=AXIS2_PLACEMENT_3D('',#2536,#2537,#2538);
#2540=CYLINDRICAL_SURFACE('',#2539,3.95);
#2541=ORIENTED_EDGE('',*,*,#2515,.T.);
#2542=EDGE_LOOP('',(#2541));
#2543=FACE_BOUND('',#2542,.T.);
#2544=CARTESIAN_POINT('',(2.,22.,3.40624426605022));
#2545=CARTESIAN_POINT('',(1.99999138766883,21.8959935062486,3.40625488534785));
#2546=CARTESIAN_POINT('',(1.99183183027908,21.7918560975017,3.4110812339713));
#2547=CARTESIAN_POINT('',(1.95961443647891,21.5867965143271,3.42968424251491));
#2548=CARTESIAN_POINT('',(1.93552404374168,21.485881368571,3.44347922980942));
#2549=CARTESIAN_POINT('',(1.87276279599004,21.2906188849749,3.47800554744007));
#2550=CARTESIAN_POINT('',(1.83417100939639,21.1962391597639,3.49869919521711));
#2551=CARTESIAN_POINT('',(1.7437438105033,21.0153186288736,3.544632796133));
#2552=CARTESIAN_POINT('',(1.69190739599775,20.9287784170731,3.56987309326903));
#2553=CARTESIAN_POINT('',(1.57131607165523,20.7579026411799,3.62466652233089));
#2554=CARTESIAN_POINT('',(1.50150004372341,20.6743746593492,3.65440387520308));
#2555=CARTESIAN_POINT('',(1.3491360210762,20.5195829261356,3.71335521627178));
#2556=CARTESIAN_POINT('',(1.26658157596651,20.4483254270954,3.74256893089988));
#2557=CARTESIAN_POINT('',(1.08406966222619,20.3152421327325,3.79961099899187));
#2558=CARTESIAN_POINT('',(0.983301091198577,20.254417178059,3.8272016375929));
#2559=CARTESIAN_POINT('',(0.77130241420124,20.1509525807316,3.8754840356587));
#2560=CARTESIAN_POINT('',(0.660079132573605,20.1083011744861,3.89618025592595));
#2561=CARTESIAN_POINT('',(0.438890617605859,20.045617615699,3.92701194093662));
#2562=CARTESIAN_POINT('',(0.32942115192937,20.0241671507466,3.9378054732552));
#2563=CARTESIAN_POINT('',(0.107946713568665,19.9998160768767,3.95007823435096));
#2564=CARTESIAN_POINT('',(-0.00405663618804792,19.9969039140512,3.95156326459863));
#2565=CARTESIAN_POINT('',(-0.216724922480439,20.0091818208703,3.94535695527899));
#2566=CARTESIAN_POINT('',(-0.317510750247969,20.0227817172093,3.93847163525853));
#2567=CARTESIAN_POINT('',(-0.515141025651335,20.0648416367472,3.91752550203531));
#2568=CARTESIAN_POINT('',(-0.611985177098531,20.0933027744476,3.90346415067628));
#2569=CARTESIAN_POINT('',(-0.800646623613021,20.1644420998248,3.86921063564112));
#2570=CARTESIAN_POINT('',(-0.892378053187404,20.2073076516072,3.84893800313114));
#2571=CARTESIAN_POINT('',(-1.06756332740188,20.3057696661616,3.80407642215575));
#2572=CARTESIAN_POINT('',(-1.15101422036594,20.3613706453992,3.77948594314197));
#2573=CARTESIAN_POINT('',(-1.31584591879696,20.4898687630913,3.72549002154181));
#2574=CARTESIAN_POINT('',(-1.39625376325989,20.5639157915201,3.69584894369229));
#2575=CARTESIAN_POINT('',(-1.54404226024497,20.7241366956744,3.63658989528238));
#2576=CARTESIAN_POINT('',(-1.61141244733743,20.8103202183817,3.60697196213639));
#2577=CARTESIAN_POINT('',(-1.73560411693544,20.9993528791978,3.54896962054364));
#2578=CARTESIAN_POINT('',(-1.79142914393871,21.1029283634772,3.52079743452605));
#2579=CARTESIAN_POINT('',(-1.8844450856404,21.3197483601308,3.47190937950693));
#2580=CARTESIAN_POINT('',(-1.92165583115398,21.4329824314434,3.4511855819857));
#2581=CARTESIAN_POINT('',(-1.97332771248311,21.6564160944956,3.42188557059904));
#2582=CARTESIAN_POINT('',(-1.98936785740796,21.7661362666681,3.41247166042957));
#2583=CARTESIAN_POINT('',(-2.00301192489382,21.9870769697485,3.40448540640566));
#2584=CARTESIAN_POINT('',(-2.00062965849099,22.0982963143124,3.40590494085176));
#2585=CARTESIAN_POINT('',(-1.97894594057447,22.3055965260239,3.41853549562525));
#2586=CARTESIAN_POINT('',(-1.96159674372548,22.4019621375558,3.42861617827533));
#2587=CARTESIAN_POINT('',(-1.91339652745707,22.5902208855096,3.45574487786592));
#2588=CARTESIAN_POINT('',(-1.88254098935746,22.6821125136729,3.47279522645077));
#2589=CARTESIAN_POINT('',(-1.80671915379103,22.8636493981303,3.51285881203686));
#2590=CARTESIAN_POINT('',(-1.76116755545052,22.952995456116,3.53611084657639));
#2591=CARTESIAN_POINT('',(-1.65775230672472,23.1232961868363,3.58575597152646));
#2592=CARTESIAN_POINT('',(-1.59988231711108,23.2042465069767,3.61215067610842));
#2593=CARTESIAN_POINT('',(-1.46469117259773,23.3664643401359,3.66922742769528));
#2594=CARTESIAN_POINT('',(-1.38581971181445,23.4464066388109,3.70002095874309));
#2595=CARTESIAN_POINT('',(-1.21532407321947,23.5923514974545,3.75947306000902));
#2596=CARTESIAN_POINT('',(-1.12369525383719,23.6583489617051,3.78813084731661));
#2597=CARTESIAN_POINT('',(-0.926684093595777,23.7761749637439,3.84115169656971));
#2598=CARTESIAN_POINT('',(-0.82098002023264,23.8275372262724,3.86536615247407));
#2599=CARTESIAN_POINT('',(-0.600852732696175,23.9112315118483,3.90563067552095));
#2600=CARTESIAN_POINT('',(-0.486437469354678,23.9435806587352,3.92168808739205));
#2601=CARTESIAN_POINT('',(-0.263646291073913,23.9854772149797,3.94262952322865));
#2602=CARTESIAN_POINT('',(-0.155701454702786,23.9968688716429,3.94841548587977));
#2603=CARTESIAN_POINT('',(0.0606993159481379,24.0020027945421,3.95101326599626));
#2604=CARTESIAN_POINT('',(0.169155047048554,23.9957515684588,3.94782839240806));
#2605=CARTESIAN_POINT('',(0.37564733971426,23.9669802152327,3.93336701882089));
#2606=CARTESIAN_POINT('',(0.473888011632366,23.9456065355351,3.92266108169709));
#2607=CARTESIAN_POINT('',(0.665218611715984,23.8887690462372,3.89478326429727));
#2608=CARTESIAN_POINT('',(0.758307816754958,23.8533032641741,3.8776104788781));
#2609=CARTESIAN_POINT('',(0.941096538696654,23.7677521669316,3.83744235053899));
#2610=CARTESIAN_POINT('',(1.03048939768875,23.7171153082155,3.81423272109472));
#2611=CARTESIAN_POINT('',(1.19987235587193,23.6033494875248,3.7643876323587));
#2612=CARTESIAN_POINT('',(1.27985813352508,23.5402148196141,3.73775061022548));
#2613=CARTESIAN_POINT('',(1.43674092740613,23.3958020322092,3.68048061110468));
#2614=CARTESIAN_POINT('',(1.51249646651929,23.3133317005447,3.64971675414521));
#2615=CARTESIAN_POINT('',(1.64953005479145,23.1364822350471,3.58986806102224));
#2616=CARTESIAN_POINT('',(1.71079472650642,23.0420922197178,3.56078479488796));
#2617=CARTESIAN_POINT('',(1.81900577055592,22.8395350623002,3.50678300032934));
#2618=CARTESIAN_POINT('',(1.86536584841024,22.7309974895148,3.48204923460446));
#2619=CARTESIAN_POINT('',(1.92019117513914,22.5624610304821,3.45192583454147));
#2620=CARTESIAN_POINT('',(1.93600619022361,22.5053810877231,3.44305242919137));
#2621=CARTESIAN_POINT('',(1.96255706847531,22.3897192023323,3.42798857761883));
#2622=CARTESIAN_POINT('',(1.97329645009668,22.3311383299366,3.4217962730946));
#2623=CARTESIAN_POINT('',(1.98758230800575,22.2271094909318,3.41351241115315));
#2624=CARTESIAN_POINT('',(1.99223311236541,22.1818593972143,3.41079522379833));
#2625=CARTESIAN_POINT('',(1.99844394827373,22.0910812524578,3.40715876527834));
#2626=CARTESIAN_POINT('',(2.00000377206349,22.0455531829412,3.40623961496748));
#2627=CARTESIAN_POINT('',(2.,22.,3.40624426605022));
#2628=B_SPLINE_CURVE_WITH_KNOTS('',3,(#2544,#2545,#2546,#2547,#2548,#2549,#2550,#2551,#2552,
#2553,#2554,#2555,#2556,#2557,#2558,#2559,#2560,#2561,#2562,#2563,#2564,#2565,#2566,#2567,#2568,
#2569,#2570,#2571,#2572,#2573,#2574,#2575,#2576,#2577,#2578,#2579,#2580,#2581,#2582,#2583,#2584,
#2585,#2586,#2587,#2588,#2589,#2590,#2591,#2592,#2593,#2594,#2595,#2596,#2597,#2598,#2599,#2600,
#2601,#2602,#2603,#2604,#2605,#2606,#2607,#2608,#2609,#2610,#2611,#2612,#2613,#2614,#2615,#2616,
#2617,#2618,#2619,#2620,#2621,#2622,#2623,#2624,#2625,#2626,#2627),.UNSPECIFIED.,.T.,.F.,(4,2,2,
2,2,2,2,2,2,2,2,2,2,2,2,2,2,2,2,2,2,2,2,2,2,2,2,2,2,2,2,2,2,2,2,2,2,2,2,2,2,4),(0.,
0.311835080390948,0.624309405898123,0.935104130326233,1.24592237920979,1.58306695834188,
1.92038282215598,2.28116212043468,2.64170753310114,2.97605627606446,3.31019661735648,
3.61455776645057,3.91894174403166,4.22744896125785,4.5360657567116,4.87439748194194,
5.21299967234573,5.57406748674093,5.93474981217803,6.26663789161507,6.59827718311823,
6.89225189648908,7.18632503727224,7.49396459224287,7.80176284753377,8.14955094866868,
8.49746591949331,8.85546796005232,9.21314707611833,9.53748798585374,9.86170927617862,
10.1636703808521,10.4656737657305,10.7803634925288,11.0951972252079,11.4420506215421,
11.7892229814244,12.1487345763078,12.3281679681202,12.5074767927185,12.6440463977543,
12.7806251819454),.UNSPECIFIED.);
#2629=CARTESIAN_POINT('',(2.,22.,3.40624426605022));
#2630=VERTEX_POINT('',#2629);
#2631=EDGE_CURVE('E1464',#2630,#2630,#2628,.T.);
#2632=ORIENTED_EDGE('',*,*,#2631,.T.);
#2633=EDGE_LOOP('',(#2632));
#2634=FACE_BOUND('',#2633,.T.);
#2635=CARTESIAN_POINT('',(0.,7.25455173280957,0.));
#2636=DIRECTION('',(0.,-1.,0.));
#2637=DIRECTION('',(0.,0.,-1.));
#2638=AXIS2_PLACEMENT_3D('',#2635,#2636,#2637);
#2639=CIRCLE('',#2638,3.95);
#2640=CARTESIAN_POINT('',(0.,7.25455173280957,-3.95));
#2641=VERTEX_POINT('',#2640);
#2642=EDGE_CURVE('E1459',#2641,#2641,#2639,.T.);
#2643=ORIENTED_EDGE('',*,*,#2642,.F.);
#2644=EDGE_LOOP('',(#2643));
#2645=FACE_BOUND('',#2644,.T.);
#2646=ORIENTED_EDGE('',*,*,#2402,.T.);
#2647=DIRECTION('',(0.,-1.,0.));
#2648=VECTOR('',#2647,1.);
#2649=CARTESIAN_POINT('',(3.74699879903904,0.,-1.25));
#2650=LINE('',#2649,#2648);
#2651=CARTESIAN_POINT('',(3.74699879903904,14.75,-1.25));
#2652=VERTEX_POINT('',#2651);
#2653=EDGE_CURVE('E1404',#2401,#2652,#2650,.T.);
#2654=ORIENTED_EDGE('',*,*,#2653,.T.);
#2655=CARTESIAN_POINT('',(3.74699879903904,14.75,-1.25));
#2656=CARTESIAN_POINT('',(3.74699565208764,14.7157812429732,-1.2500008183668));
#2657=CARTESIAN_POINT('',(3.74746813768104,14.6815798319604,-1.24859398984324));
#2658=CARTESIAN_POINT('',(3.74933230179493,14.6134401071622,-1.24298847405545));
#2659=CARTESIAN_POINT('',(3.75072375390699,14.5795017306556,-1.23879047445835));
#2660=CARTESIAN_POINT('',(3.75621558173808,14.4786416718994,-1.22208412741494));
#2661=CARTESIAN_POINT('',(3.76163389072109,14.4124247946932,-1.20546303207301));
#2662=CARTESIAN_POINT('',(3.77533367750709,14.2839085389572,-1.16183920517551));
#2663=CARTESIAN_POINT('',(3.78361387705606,14.2216074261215,-1.13484110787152));
#2664=CARTESIAN_POINT('',(3.80209842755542,14.102369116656,-1.07127965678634));
#2665=CARTESIAN_POINT('',(3.812303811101,14.0454348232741,-1.03471116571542));
#2666=CARTESIAN_POINT('',(3.83388796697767,13.9365889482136,-0.95168073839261));
#2667=CARTESIAN_POINT('',(3.84529371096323,13.8848943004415,-0.904941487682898));
#2668=CARTESIAN_POINT('',(3.86776491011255,13.7899280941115,-0.803486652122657));
#2669=CARTESIAN_POINT('',(3.87883030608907,13.7466579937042,-0.748769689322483));
#2670=CARTESIAN_POINT('',(3.8996847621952,13.6688042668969,-0.631340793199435));
#2671=CARTESIAN_POINT('',(3.90943815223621,13.6344460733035,-0.568472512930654));
#2672=CARTESIAN_POINT('',(3.92625185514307,13.5768779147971,-0.437490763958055));
#2673=CARTESIAN_POINT('',(3.93331292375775,13.5536648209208,-0.369378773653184));
#2674=CARTESIAN_POINT('',(3.94375496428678,13.5197740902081,-0.232124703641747));
#2675=CARTESIAN_POINT('',(3.94724515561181,13.5087235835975,-0.163083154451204));
#2676=CARTESIAN_POINT('',(3.9505383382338,13.4982894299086,-0.0240421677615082));
#2677=CARTESIAN_POINT('',(3.95034211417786,13.4989033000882,0.0459570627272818));
#2678=CARTESIAN_POINT('',(3.94636010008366,13.5115372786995,0.182296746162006));
#2679=CARTESIAN_POINT('',(3.94270162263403,13.5231528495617,0.248679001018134));
#2680=CARTESIAN_POINT('',(3.93236342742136,13.5567955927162,0.378497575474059));
#2681=CARTESIAN_POINT('',(3.92568354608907,13.5788233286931,0.441933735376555));
#2682=CARTESIAN_POINT('',(3.90988377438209,13.6329207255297,0.564985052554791));
#2683=CARTESIAN_POINT('',(3.90073458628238,13.6651118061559,0.624542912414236));
#2684=CARTESIAN_POINT('',(3.88095817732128,13.7385241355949,0.737535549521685));
#2685=CARTESIAN_POINT('',(3.87033059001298,13.7797476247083,0.790968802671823));
#2686=CARTESIAN_POINT('',(3.84819208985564,13.8721193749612,0.892602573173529));
#2687=CARTESIAN_POINT('',(3.83666283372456,13.9236155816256,0.94048326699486));
#2688=CARTESIAN_POINT('',(3.8144071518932,14.0340252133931,1.027034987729));
#2689=CARTESIAN_POINT('',(3.80368097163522,14.0929408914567,1.06570320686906));
#2690=CARTESIAN_POINT('',(3.78414899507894,14.2174524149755,1.13312300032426));
#2691=CARTESIAN_POINT('',(3.77536829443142,14.2831211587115,1.16174748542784));
#2692=CARTESIAN_POINT('',(3.76102057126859,14.4186575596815,1.20739641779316));
#2693=CARTESIAN_POINT('',(3.75544856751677,14.4885185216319,1.22443885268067));
#2694=CARTESIAN_POINT('',(3.75024252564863,14.5908727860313,1.24024270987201));
#2695=CARTESIAN_POINT('',(3.74902916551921,14.6225972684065,1.24390077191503));
#2696=CARTESIAN_POINT('',(3.74740699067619,14.6862089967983,1.24877749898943));
#2697=CARTESIAN_POINT('',(3.74699705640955,14.7180959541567,1.24999955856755));
#2698=CARTESIAN_POINT('',(3.74699879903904,14.75,1.25));
#2699=B_SPLINE_CURVE_WITH_KNOTS('',3,(#2655,#2656,#2657,#2658,#2659,#2660,#2661,#2662,#2663,
#2664,#2665,#2666,#2667,#2668,#2669,#2670,#2671,#2672,#2673,#2674,#2675,#2676,#2677,#2678,#2679,
#2680,#2681,#2682,#2683,#2684,#2685,#2686,#2687,#2688,#2689,#2690,#2691,#2692,#2693,#2694,#2695,
#2696,#2697,#2698),.UNSPECIFIED.,.F.,.F.,(4,2,2,2,2,2,2,2,2,2,2,2,2,2,2,2,2,2,2,2,2,4),(0.,
0.102590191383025,0.20515511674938,0.40954413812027,0.613841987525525,0.818249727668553,
1.02914905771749,1.24008485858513,1.45592653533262,1.67170757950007,1.88067132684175,
2.08959059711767,2.29111435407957,2.49264902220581,2.69668880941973,2.90077926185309,
3.11356272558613,3.32641095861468,3.54186281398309,3.75697929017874,3.85276532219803,
3.94841778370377),.UNSPECIFIED.);
#2700=CARTESIAN_POINT('',(3.74699879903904,14.75,1.25));
#2701=VERTEX_POINT('',#2700);
#2702=EDGE_CURVE('E1389',#2652,#2701,#2699,.T.);
#2703=ORIENTED_EDGE('',*,*,#2702,.T.);
#2704=DIRECTION('',(0.,-1.,0.));
#2705=VECTOR('',#2704,1.);
#2706=CARTESIAN_POINT('',(3.74699879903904,0.,1.25));
#2707=LINE('',#2706,#2705);
#2708=EDGE_CURVE('E1433',#2701,#2521,#2707,.F.);
#2709=ORIENTED_EDGE('',*,*,#2708,.T.);
#2710=ORIENTED_EDGE('',*,*,#2524,.T.);
#2711=DIRECTION('',(0.,-1.,0.));
#2712=VECTOR('',#2711,1.);
#2713=CARTESIAN_POINT('',(-3.74699879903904,0.,1.25));
#2714=LINE('',#2713,#2712);
#2715=CARTESIAN_POINT('',(-3.74699879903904,14.75,1.25));
#2716=VERTEX_POINT('',#2715);
#2717=EDGE_CURVE('E1432',#2523,#2716,#2714,.T.);
#2718=ORIENTED_EDGE('',*,*,#2717,.T.);
#2719=CARTESIAN_POINT('',(-3.74699879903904,14.75,1.25));
#2720=CARTESIAN_POINT('',(-3.74699565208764,14.7157812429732,1.2500008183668));
#2721=CARTESIAN_POINT('',(-3.74746813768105,14.6815798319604,1.24859398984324));
#2722=CARTESIAN_POINT('',(-3.74933230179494,14.6134401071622,1.24298847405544));
#2723=CARTESIAN_POINT('',(-3.75072375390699,14.5795017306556,1.23879047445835));
#2724=CARTESIAN_POINT('',(-3.75621558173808,14.4786416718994,1.22208412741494));
#2725=CARTESIAN_POINT('',(-3.7616338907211,14.4124247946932,1.20546303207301));
#2726=CARTESIAN_POINT('',(-3.77533367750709,14.2839085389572,1.1618392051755));
#2727=CARTESIAN_POINT('',(-3.78361387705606,14.2216074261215,1.13484110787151));
#2728=CARTESIAN_POINT('',(-3.80209842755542,14.102369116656,1.07127965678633));
#2729=CARTESIAN_POINT('',(-3.812303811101,14.0454348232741,1.03471116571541));
#2730=CARTESIAN_POINT('',(-3.83388796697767,13.9365889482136,0.951680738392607));
#2731=CARTESIAN_POINT('',(-3.84529371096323,13.8848943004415,0.904941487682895));
#2732=CARTESIAN_POINT('',(-3.86776491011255,13.7899280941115,0.803486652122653));
#2733=CARTESIAN_POINT('',(-3.87883030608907,13.7466579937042,0.74876968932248));
#2734=CARTESIAN_POINT('',(-3.8996847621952,13.6688042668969,0.631340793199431));
#2735=CARTESIAN_POINT('',(-3.90943815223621,13.6344460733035,0.56847251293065));
#2736=CARTESIAN_POINT('',(-3.92625185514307,13.5768779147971,0.437490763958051));
#2737=CARTESIAN_POINT('',(-3.93331292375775,13.5536648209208,0.369378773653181));
#2738=CARTESIAN_POINT('',(-3.94375496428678,13.5197740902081,0.232124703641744));
#2739=CARTESIAN_POINT('',(-3.94724515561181,13.5087235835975,0.1630831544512));
#2740=CARTESIAN_POINT('',(-3.9505383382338,13.4982894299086,0.0240421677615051));
#2741=CARTESIAN_POINT('',(-3.95034211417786,13.4989033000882,-0.0459570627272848));
#2742=CARTESIAN_POINT('',(-3.94636010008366,13.5115372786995,-0.182296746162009));
#2743=CARTESIAN_POINT('',(-3.94270162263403,13.5231528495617,-0.248679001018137));
#2744=CARTESIAN_POINT('',(-3.93236342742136,13.5567955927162,-0.378497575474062));
#2745=CARTESIAN_POINT('',(-3.92568354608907,13.5788233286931,-0.441933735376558));
#2746=CARTESIAN_POINT('',(-3.90988377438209,13.6329207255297,-0.564985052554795));
#2747=CARTESIAN_POINT('',(-3.90073458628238,13.6651118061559,-0.62454291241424));
#2748=CARTESIAN_POINT('',(-3.88095817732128,13.7385241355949,-0.737535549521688));
#2749=CARTESIAN_POINT('',(-3.87033059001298,13.7797476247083,-0.790968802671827));
#2750=CARTESIAN_POINT('',(-3.84819208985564,13.8721193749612,-0.892602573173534));
#2751=CARTESIAN_POINT('',(-3.83666283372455,13.9236155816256,-0.940483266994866));
#2752=CARTESIAN_POINT('',(-3.8144071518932,14.0340252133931,-1.02703498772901));
#2753=CARTESIAN_POINT('',(-3.80368097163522,14.0929408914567,-1.06570320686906));
#2754=CARTESIAN_POINT('',(-3.78414899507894,14.2174524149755,-1.13312300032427));
#2755=CARTESIAN_POINT('',(-3.77536829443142,14.2831211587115,-1.16174748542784));
#2756=CARTESIAN_POINT('',(-3.76102057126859,14.4186575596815,-1.20739641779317));
#2757=CARTESIAN_POINT('',(-3.75544856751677,14.4885185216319,-1.22443885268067));
#2758=CARTESIAN_POINT('',(-3.75024252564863,14.5908727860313,-1.24024270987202));
#2759=CARTESIAN_POINT('',(-3.74902916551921,14.6225972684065,-1.24390077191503));
#2760=CARTESIAN_POINT('',(-3.74740699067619,14.6862089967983,-1.24877749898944));
#2761=CARTESIAN_POINT('',(-3.74699705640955,14.7180959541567,-1.24999955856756));
#2762=CARTESIAN_POINT('',(-3.74699879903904,14.75,-1.25));
#2763=B_SPLINE_CURVE_WITH_KNOTS('',3,(#2719,#2720,#2721,#2722,#2723,#2724,#2725,#2726,#2727,
#2728,#2729,#2730,#2731,#2732,#2733,#2734,#2735,#2736,#2737,#2738,#2739,#2740,#2741,#2742,#2743,
#2744,#2745,#2746,#2747,#2748,#2749,#2750,#2751,#2752,#2753,#2754,#2755,#2756,#2757,#2758,#2759,
#2760,#2761,#2762),.UNSPECIFIED.,.F.,.F.,(4,2,2,2,2,2,2,2,2,2,2,2,2,2,2,2,2,2,2,2,2,4),(0.,
0.102590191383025,0.20515511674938,0.40954413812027,0.613841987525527,0.818249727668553,
1.02914905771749,1.24008485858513,1.45592653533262,1.67170757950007,1.88067132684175,
2.08959059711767,2.29111435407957,2.49264902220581,2.69668880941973,2.90077926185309,
3.11356272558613,3.32641095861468,3.54186281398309,3.75697929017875,3.85276532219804,
3.94841778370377),.UNSPECIFIED.);
#2764=CARTESIAN_POINT('',(-3.74699879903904,14.75,-1.25));
#2765=VERTEX_POINT('',#2764);
#2766=EDGE_CURVE('E62',#2716,#2765,#2763,.T.);
#2767=ORIENTED_EDGE('',*,*,#2766,.T.);
#2768=DIRECTION('',(0.,-1.,0.));
#2769=VECTOR('',#2768,1.);
#2770=CARTESIAN_POINT('',(-3.74699879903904,0.,-1.25));
#2771=LINE('',#2770,#2769);
#2772=EDGE_CURVE('E1444',#2765,#2399,#2771,.F.);
#2773=ORIENTED_EDGE('',*,*,#2772,.T.);
#2774=EDGE_LOOP('',(#2646,#2654,#2703,#2709,#2710,#2718,#2767,#2773));
#2775=FACE_BOUND('',#2774,.T.);
#2776=ADVANCED_FACE('F1438',(#2543,#2634,#2645,#2775),#2540,.T.);
#2777=CARTESIAN_POINT('',(0.,7.25455173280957,0.));
#2778=DIRECTION('',(0.,1.,0.));
#2779=DIRECTION('',(0.,0.,1.));
#2780=AXIS2_PLACEMENT_3D('',#2777,#2778,#2779);
#2781=CONICAL_SURFACE('',#2780,3.95,1.30899693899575);
#2782=CARTESIAN_POINT('',(0.,7.,0.));
#2783=DIRECTION('',(0.,-1.,0.));
#2784=DIRECTION('',(0.,0.,-1.));
#2785=AXIS2_PLACEMENT_3D('',#2782,#2783,#2784);
#2786=CIRCLE('',#2785,3.);
#2787=CARTESIAN_POINT('',(0.,7.,-3.));
#2788=VERTEX_POINT('',#2787);
#2789=EDGE_CURVE('E1456',#2788,#2788,#2786,.T.);
#2790=ORIENTED_EDGE('',*,*,#2789,.F.);
#2791=EDGE_LOOP('',(#2790));
#2792=FACE_BOUND('',#2791,.T.);
#2793=ORIENTED_EDGE('',*,*,#2642,.T.);
#2794=EDGE_LOOP('',(#2793));
#2795=FACE_BOUND('',#2794,.T.);
#2796=ADVANCED_FACE('F1490',(#2792,#2795),#2781,.T.);
#2797=CARTESIAN_POINT('',(0.,0.,0.));
#2798=DIRECTION('',(0.,-1.,0.));
#2799=DIRECTION('',(0.,0.,-1.));
#2800=AXIS2_PLACEMENT_3D('',#2797,#2798,#2799);
#2801=CYLINDRICAL_SURFACE('',#2800,3.);
#2802=CARTESIAN_POINT('',(0.,0.,0.));
#2803=DIRECTION('',(0.,-1.,0.));
#2804=DIRECTION('',(0.,0.,-1.));
#2805=AXIS2_PLACEMENT_3D('',#2802,#2803,#2804);
#2806=CIRCLE('',#2805,3.);
#2807=CARTESIAN_POINT('',(0.,0.,-3.));
#2808=VERTEX_POINT('',#2807);
#2809=EDGE_CURVE('E1453',#2808,#2808,#2806,.T.);
#2810=ORIENTED_EDGE('',*,*,#2809,.F.);
#2811=EDGE_LOOP('',(#2810));
#2812=FACE_BOUND('',#2811,.T.);
#2813=ORIENTED_EDGE('',*,*,#2789,.T.);
#2814=EDGE_LOOP('',(#2813));
#2815=FACE_BOUND('',#2814,.T.);
#2816=ADVANCED_FACE('F1487',(#2812,#2815),#2801,.T.);
#2817=CARTESIAN_POINT('',(0.,0.,0.));
#2818=DIRECTION('',(0.,1.,0.));
#2819=DIRECTION('',(0.,0.,1.));
#2820=AXIS2_PLACEMENT_3D('',#2817,#2818,#2819);
#2821=PLANE('',#2820);
#2822=CARTESIAN_POINT('',(0.,0.,0.));
#2823=DIRECTION('',(0.,-1.,0.));
#2824=DIRECTION('',(0.,0.,-1.));
#2825=AXIS2_PLACEMENT_3D('',#2822,#2823,#2824);
#2826=CIRCLE('',#2825,2.);
#2827=CARTESIAN_POINT('',(0.,0.,-2.));
#2828=VERTEX_POINT('',#2827);
#2829=EDGE_CURVE('E1593',#2828,#2828,#2826,.T.);
#2830=ORIENTED_EDGE('',*,*,#2829,.F.);
#2831=EDGE_LOOP('',(#2830));
#2832=FACE_BOUND('',#2831,.T.);
#2833=ORIENTED_EDGE('',*,*,#2809,.T.);
#2834=EDGE_LOOP('',(#2833));
#2835=FACE_BOUND('',#2834,.T.);
#2836=ADVANCED_FACE('F1481',(#2832,#2835),#2821,.F.);
#2837=CARTESIAN_POINT('',(0.,22.,1.25));
#2838=DIRECTION('',(0.,0.,1.));
#2839=DIRECTION('',(0.,-1.,0.));
#2840=AXIS2_PLACEMENT_3D('',#2837,#2838,#2839);
#2841=CIRCLE('',#2840,2.);
#2842=CARTESIAN_POINT('',(0.,20.,1.25));
#2843=VERTEX_POINT('',#2842);
#2844=EDGE_CURVE('E1588',#2843,#2843,#2841,.F.);
#2845=ORIENTED_EDGE('',*,*,#2844,.T.);
#2846=EDGE_LOOP('',(#2845));
#2847=FACE_BOUND('',#2846,.T.);
#2848=ORIENTED_EDGE('',*,*,#2631,.F.);
#2849=EDGE_LOOP('',(#2848));
#2850=FACE_BOUND('',#2849,.T.);
#2851=ADVANCED_FACE('F1476',(#2847,#2850),#2418,.F.);
#2852=CARTESIAN_POINT('',(-3.95,14.75,0.));
#2853=DIRECTION('',(1.,0.,0.));
#2854=DIRECTION('',(0.,0.,-1.));
#2855=AXIS2_PLACEMENT_3D('',#2852,#2853,#2854);
#2856=CYLINDRICAL_SURFACE('',#2855,1.25);
#2857=DIRECTION('',(1.,0.,0.));
#2858=VECTOR('',#2857,1.);
#2859=CARTESIAN_POINT('',(-3.95,14.75,-1.25));
#2860=LINE('',#2859,#2858);
#2861=EDGE_CURVE('E1427',#2765,#2652,#2860,.T.);
#2862=ORIENTED_EDGE('',*,*,#2861,.F.);
#2863=ORIENTED_EDGE('',*,*,#2766,.F.);
#2864=DIRECTION('',(1.,0.,0.));
#2865=VECTOR('',#2864,1.);
#2866=CARTESIAN_POINT('',(-3.95,14.75,1.25));
#2867=LINE('',#2866,#2865);
#2868=EDGE_CURVE('E1425',#2716,#2701,#2867,.T.);
#2869=ORIENTED_EDGE('',*,*,#2868,.T.);
#2870=ORIENTED_EDGE('',*,*,#2702,.F.);
#2871=EDGE_LOOP('',(#2862,#2863,#2869,#2870));
#2872=FACE_BOUND('',#2871,.T.);
#2873=ADVANCED_FACE('F1424',(#2872),#2856,.F.);
#2874=CARTESIAN_POINT('',(-3.95,27.5,-1.25));
#2875=DIRECTION('',(0.,0.,-1.));
#2876=DIRECTION('',(0.,1.,0.));
#2877=AXIS2_PLACEMENT_3D('',#2874,#2875,#2876);
#2878=PLANE('',#2877);
#2879=ORIENTED_EDGE('',*,*,#2426,.F.);
#2880=EDGE_LOOP('',(#2879));
#2881=FACE_BOUND('',#2880,.T.);
#2882=ORIENTED_EDGE('',*,*,#2409,.F.);
#2883=ORIENTED_EDGE('',*,*,#2772,.F.);
#2884=ORIENTED_EDGE('',*,*,#2861,.T.);
#2885=ORIENTED_EDGE('',*,*,#2653,.F.);
#2886=EDGE_LOOP('',(#2882,#2883,#2884,#2885));
#2887=FACE_BOUND('',#2886,.T.);
#2888=ADVANCED_FACE('F1535',(#2881,#2887),#2878,.F.);
#2889=CARTESIAN_POINT('',(-3.95,27.5,1.25));
#2890=DIRECTION('',(0.,0.,1.));
#2891=DIRECTION('',(0.,-1.,0.));
#2892=AXIS2_PLACEMENT_3D('',#2889,#2890,#2891);
#2893=PLANE('',#2892);
#2894=ORIENTED_EDGE('',*,*,#2844,.F.);
#2895=EDGE_LOOP('',(#2894));
#2896=FACE_BOUND('',#2895,.T.);
#2897=ORIENTED_EDGE('',*,*,#2531,.F.);
#2898=ORIENTED_EDGE('',*,*,#2708,.F.);
#2899=ORIENTED_EDGE('',*,*,#2868,.F.);
#2900=ORIENTED_EDGE('',*,*,#2717,.F.);
#2901=EDGE_LOOP('',(#2897,#2898,#2899,#2900));
#2902=FACE_BOUND('',#2901,.T.);
#2903=ADVANCED_FACE('F1431',(#2896,#2902),#2893,.F.);
#2904=CARTESIAN_POINT('',(0.,10.,0.));
#2905=DIRECTION('',(0.,-1.,0.));
#2906=DIRECTION('',(0.,0.,-1.));
#2907=AXIS2_PLACEMENT_3D('',#2904,#2905,#2906);
#2908=CYLINDRICAL_SURFACE('',#2907,2.);
#2909=CARTESIAN_POINT('',(0.,10.,0.));
#2910=DIRECTION('',(0.,-1.,0.));
#2911=DIRECTION('',(0.,0.,-1.));
#2912=AXIS2_PLACEMENT_3D('',#2909,#2910,#2911);
#2913=CIRCLE('',#2912,2.);
#2914=CARTESIAN_POINT('',(0.,10.,-2.));
#2915=VERTEX_POINT('',#2914);
#2916=EDGE_CURVE('E1434',#2915,#2915,#2913,.T.);
#2917=ORIENTED_EDGE('',*,*,#2916,.F.);
#2918=EDGE_LOOP('',(#2917));
#2919=FACE_BOUND('',#2918,.T.);
#2920=ORIENTED_EDGE('',*,*,#2829,.T.);
#2921=EDGE_LOOP('',(#2920));
#2922=FACE_BOUND('',#2921,.T.);
#2923=ADVANCED_FACE('F1553',(#2919,#2922),#2908,.F.);
#2924=CARTESIAN_POINT('',(0.,10.,0.));
#2925=DIRECTION('',(0.,-1.,0.));
#2926=DIRECTION('',(0.,0.,-1.));
#2927=AXIS2_PLACEMENT_3D('',#2924,#2925,#2926);
#2928=PLANE('',#2927);
#2929=ORIENTED_EDGE('',*,*,#2916,.T.);
#2930=EDGE_LOOP('',(#2929));
#2931=FACE_BOUND('',#2930,.T.);
#2932=ADVANCED_FACE('F1568',(#2931),#2928,.T.);
#2933=CLOSED_SHELL('',(#2413,#2519,#2535,#2776,#2796,#2816,#2836,#2851,#2873,#2888,#2903,#2923,#2932));
#2934=MANIFOLD_SOLID_BREP('B7',#2933);
#2935=ADVANCED_BREP_SHAPE_REPRESENTATION('',(#18,#2387,#2934),#14);
#2936=SHAPE_DEFINITION_REPRESENTATION(#9,#2935);
ENDSEC;
END-ISO-10303-21;
